VERSION 5.8 ;
BUSBITCHARS "[]" ;
DIVIDERCHAR "/" ;

UNITS
  DATABASE MICRONS 1000 ;
END UNITS
MANUFACTURINGGRID 0.001 ;

SITE NSFET
  CLASS CORE ;
  SIZE 0.050 BY 0.168 ;
  SYMMETRY X Y ;
END NSFET

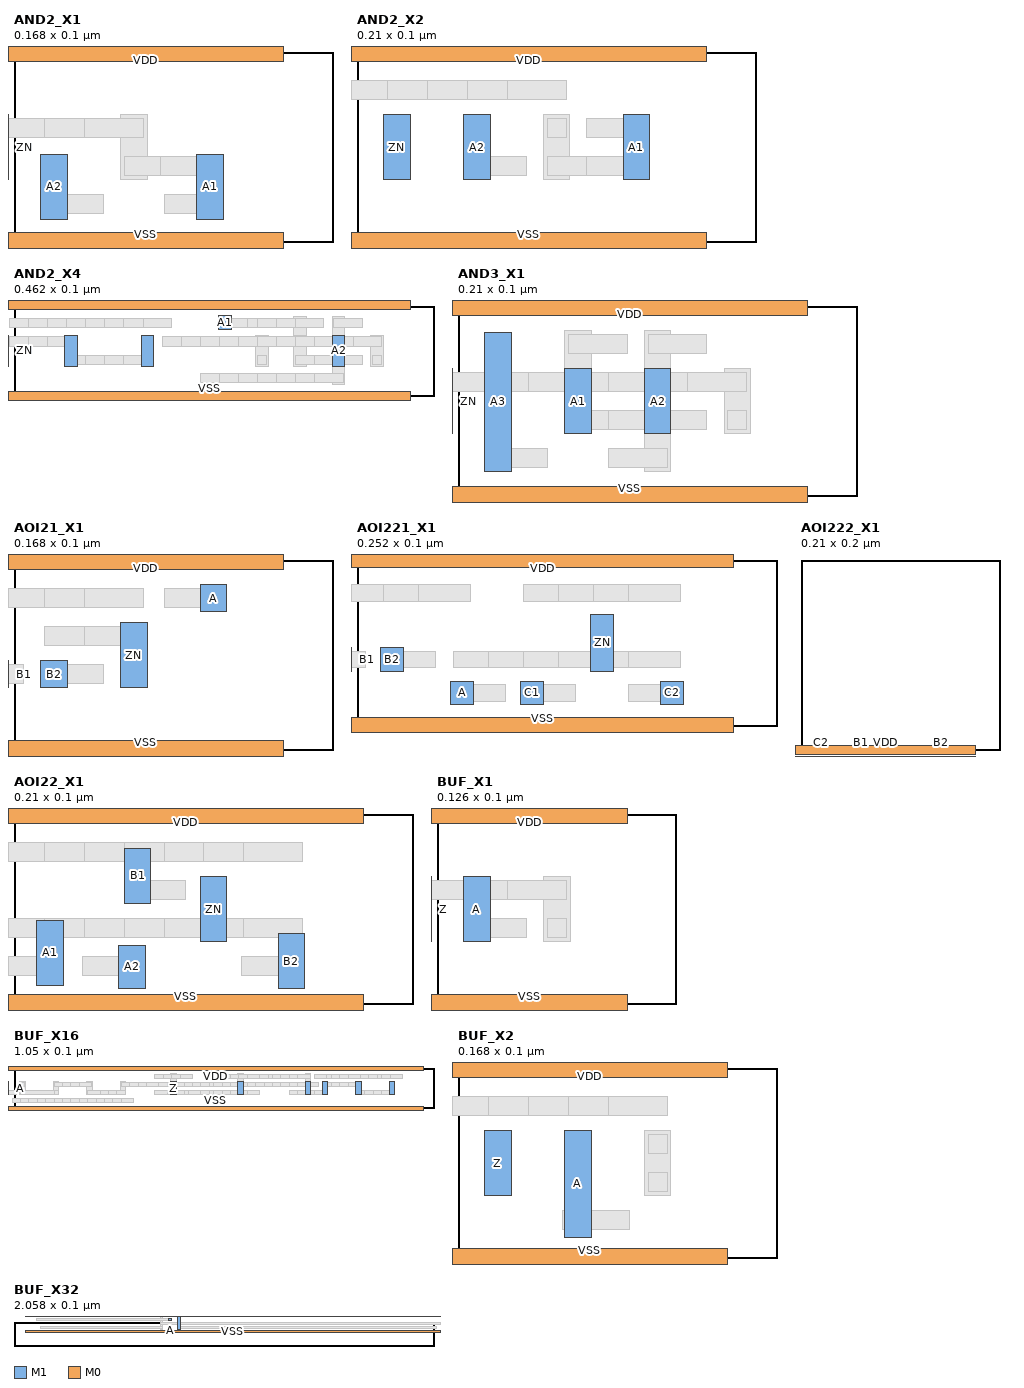
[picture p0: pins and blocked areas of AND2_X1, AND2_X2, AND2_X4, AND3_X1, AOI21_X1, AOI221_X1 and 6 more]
MACRO AND2_X1
  CLASS CORE ;
  FOREIGN AND2_X1 0 0 ;
  ORIGIN -0.0210 0.0000 ;
  SIZE 0.1680 BY 0.1000 ;
  SITE NSFET ;
  SYMMETRY X Y ;
  PIN ZN
    DIRECTION OUTPUT ;
    USE SIGNAL ;
    PORT
      LAYER M1 ;
        RECT -0.0070 0.0330 0.0070 0.0670 ;
    END
  END ZN
  PIN A1
    DIRECTION INPUT ;
    USE SIGNAL ;
    PORT
      LAYER M1 ;
        RECT 0.1170 0.0120 0.1310 0.0460 ;
    END
  END A1
  PIN A2
    DIRECTION INPUT ;
    USE SIGNAL ;
    PORT
      LAYER M1 ;
        RECT 0.0350 0.0120 0.0490 0.0460 ;
    END
  END A2
  PIN VDD
    DIRECTION INOUT ;
    USE POWER ;
    PORT
      LAYER M0 ;
        RECT -0.0370 0.0950 0.1630 0.1050 ;
    END
  END VDD
  PIN VSS
    DIRECTION INOUT ;
    USE GROUND ;
    PORT
      LAYER M0 ;
        RECT -0.0370 -0.0050 0.1630 0.0050 ;
    END
  END VSS
  OBS
    LAYER M1 ;
      RECT 0.0770 0.0330 0.0910 0.0670 ;
    LAYER M0 ;
      RECT 0.0160 0.0550 0.0470 0.0650 ;
      RECT 0.0370 0.0550 0.0680 0.0650 ;
      RECT 0.0580 0.0550 0.0890 0.0650 ;
      RECT 0.0790 0.0350 0.1100 0.0450 ;
      RECT 0.1000 0.0350 0.1310 0.0450 ;
      RECT -0.0050 0.0550 0.0050 0.0650 ;
      RECT -0.0050 0.0350 0.0050 0.0450 ;
      RECT 0.0370 0.0150 0.0680 0.0250 ;
      RECT 0.0980 0.0350 0.1290 0.0450 ;
      RECT 0.1000 0.0150 0.1310 0.0250 ;
  END
END AND2_X1

MACRO AND2_X2
  CLASS CORE ;
  FOREIGN AND2_X2 0 0 ;
  ORIGIN -0.0210 0.0000 ;
  SIZE 0.2100 BY 0.1000 ;
  SITE NSFET ;
  SYMMETRY X Y ;
  PIN A1
    DIRECTION INPUT ;
    USE SIGNAL ;
    PORT
      LAYER M1 ;
        RECT 0.1610 0.0330 0.1750 0.0670 ;
    END
  END A1
  PIN A2
    DIRECTION INPUT ;
    USE SIGNAL ;
    PORT
      LAYER M1 ;
        RECT 0.0770 0.0330 0.0910 0.0670 ;
    END
  END A2
  PIN ZN
    DIRECTION OUTPUT ;
    USE SIGNAL ;
    PORT
      LAYER M1 ;
        RECT 0.0350 0.0330 0.0490 0.0670 ;
    END
  END ZN
  PIN VSS
    DIRECTION INOUT ;
    USE GROUND ;
    PORT
      LAYER M0 ;
        RECT -0.0370 -0.0050 0.2050 0.0050 ;
    END
  END VSS
  PIN VDD
    DIRECTION INOUT ;
    USE POWER ;
    PORT
      LAYER M0 ;
        RECT -0.0370 0.0950 0.2050 0.1050 ;
    END
  END VDD
  OBS
    LAYER M1 ;
      RECT 0.1190 0.0330 0.1330 0.0670 ;
    LAYER M0 ;
      RECT 0.0160 0.0750 0.0470 0.0850 ;
      RECT 0.0370 0.0750 0.0680 0.0850 ;
      RECT 0.0580 0.0750 0.0890 0.0850 ;
      RECT 0.0790 0.0750 0.1100 0.0850 ;
      RECT 0.1000 0.0750 0.1310 0.0850 ;
      RECT 0.1210 0.0350 0.1520 0.0450 ;
      RECT 0.1420 0.0350 0.1730 0.0450 ;
      RECT 0.0370 0.0550 0.0470 0.0650 ;
      RECT 0.0370 0.0350 0.0470 0.0450 ;
      RECT 0.1210 0.0550 0.1310 0.0650 ;
      RECT 0.1420 0.0550 0.1730 0.0650 ;
      RECT 0.0790 0.0350 0.1100 0.0450 ;
  END
END AND2_X2

MACRO AND2_X4
  CLASS CORE ;
  FOREIGN AND2_X4 0 0 ;
  ORIGIN -0.0210 0.0000 ;
  SIZE 0.4620 BY 0.1000 ;
  SITE NSFET ;
  SYMMETRY X Y ;
  PIN ZN
    DIRECTION OUTPUT ;
    USE SIGNAL ;
    PORT
      LAYER M1 ;
        RECT -0.0070 0.0330 0.0070 0.0670 ;
        RECT 0.0770 0.0330 0.0910 0.0670 ;
        RECT 0.1610 0.0330 0.1750 0.0670 ;
    END
  END ZN
  PIN A1
    DIRECTION INPUT ;
    USE SIGNAL ;
    PORT
      LAYER M1 ;
        RECT 0.2460 0.0730 0.2600 0.0890 ;
    END
  END A1
  PIN A2
    DIRECTION INPUT ;
    USE SIGNAL ;
    PORT
      LAYER M1 ;
        RECT 0.3710 0.0330 0.3850 0.0670 ;
    END
  END A2
  PIN VDD
    DIRECTION INOUT ;
    USE POWER ;
    PORT
      LAYER M0 ;
        RECT -0.0370 0.0950 0.4570 0.1050 ;
    END
  END VDD
  PIN VSS
    DIRECTION INOUT ;
    USE GROUND ;
    PORT
      LAYER M0 ;
        RECT -0.0370 -0.0050 0.4570 0.0050 ;
    END
  END VSS
  OBS
    LAYER M1 ;
      RECT 0.2870 0.0330 0.3010 0.0670 ;
      RECT 0.4130 0.0330 0.4270 0.0670 ;
      RECT 0.3290 0.0530 0.3430 0.0870 ;
      RECT 0.3290 0.0330 0.3430 0.0670 ;
      RECT 0.3710 0.0530 0.3850 0.0870 ;
      RECT 0.3710 0.0130 0.3850 0.0470 ;
    LAYER M0 ;
      RECT -0.0050 0.0550 0.0260 0.0650 ;
      RECT 0.0160 0.0550 0.0470 0.0650 ;
      RECT 0.0370 0.0550 0.0680 0.0650 ;
      RECT 0.0580 0.0550 0.0890 0.0650 ;
      RECT 0.0790 0.0350 0.1100 0.0450 ;
      RECT 0.1000 0.0350 0.1310 0.0450 ;
      RECT 0.1210 0.0350 0.1520 0.0450 ;
      RECT 0.1420 0.0350 0.1730 0.0450 ;
      RECT 0.0160 0.0750 0.0470 0.0850 ;
      RECT 0.0370 0.0750 0.0680 0.0850 ;
      RECT 0.0580 0.0750 0.0890 0.0850 ;
      RECT 0.0790 0.0750 0.1100 0.0850 ;
      RECT 0.1000 0.0750 0.1310 0.0850 ;
      RECT 0.1210 0.0750 0.1520 0.0850 ;
      RECT 0.1420 0.0750 0.1730 0.0850 ;
      RECT 0.1630 0.0750 0.1940 0.0850 ;
      RECT 0.1840 0.0550 0.2150 0.0650 ;
      RECT 0.2050 0.0550 0.2360 0.0650 ;
      RECT 0.2260 0.0550 0.2570 0.0650 ;
      RECT 0.2470 0.0550 0.2780 0.0650 ;
      RECT 0.2680 0.0550 0.2990 0.0650 ;
      RECT 0.2890 0.0550 0.3200 0.0650 ;
      RECT 0.3100 0.0550 0.3410 0.0650 ;
      RECT 0.3310 0.0550 0.3620 0.0650 ;
      RECT 0.3520 0.0550 0.3830 0.0650 ;
      RECT 0.3730 0.0550 0.4040 0.0650 ;
      RECT 0.3940 0.0550 0.4250 0.0650 ;
      RECT 0.2680 0.0750 0.2990 0.0850 ;
      RECT 0.2890 0.0750 0.3200 0.0850 ;
      RECT 0.3100 0.0750 0.3410 0.0850 ;
      RECT 0.3310 0.0750 0.3620 0.0850 ;
      RECT 0.3310 0.0350 0.3620 0.0450 ;
      RECT 0.3520 0.0350 0.3830 0.0450 ;
      RECT 0.3730 0.0350 0.4040 0.0450 ;
      RECT 0.3730 0.0750 0.4040 0.0850 ;
      RECT 0.2260 0.0150 0.2570 0.0250 ;
      RECT 0.2470 0.0150 0.2780 0.0250 ;
      RECT 0.2680 0.0150 0.2990 0.0250 ;
      RECT 0.2890 0.0150 0.3200 0.0250 ;
      RECT 0.3100 0.0150 0.3410 0.0250 ;
      RECT 0.3310 0.0150 0.3620 0.0250 ;
      RECT 0.3520 0.0150 0.3830 0.0250 ;
      RECT 0.1630 0.0550 0.1730 0.0650 ;
      RECT -0.0050 0.0350 0.0050 0.0450 ;
      RECT 0.2890 0.0350 0.2990 0.0450 ;
      RECT 0.4150 0.0350 0.4250 0.0450 ;
      RECT 0.2470 0.0750 0.2780 0.0850 ;
  END
END AND2_X4

MACRO AND3_X1
  CLASS CORE ;
  FOREIGN AND3_X1 0 0 ;
  ORIGIN -0.0210 0.0000 ;
  SIZE 0.2100 BY 0.1000 ;
  SITE NSFET ;
  SYMMETRY X Y ;
  PIN A3
    DIRECTION INPUT ;
    USE SIGNAL ;
    PORT
      LAYER M1 ;
        RECT 0.0350 0.0130 0.0490 0.0860 ;
    END
  END A3
  PIN ZN
    DIRECTION OUTPUT ;
    USE SIGNAL ;
    PORT
      LAYER M1 ;
        RECT -0.0070 0.0330 0.0070 0.0670 ;
    END
  END ZN
  PIN A2
    DIRECTION INPUT ;
    USE SIGNAL ;
    PORT
      LAYER M1 ;
        RECT 0.1190 0.0330 0.1330 0.0670 ;
    END
  END A2
  PIN A1
    DIRECTION INPUT ;
    USE SIGNAL ;
    PORT
      LAYER M1 ;
        RECT 0.0770 0.0330 0.0910 0.0670 ;
    END
  END A1
  PIN VDD
    DIRECTION INOUT ;
    USE POWER ;
    PORT
      LAYER M0 ;
        RECT -0.0370 0.0950 0.2050 0.1050 ;
    END
  END VDD
  PIN VSS
    DIRECTION INOUT ;
    USE GROUND ;
    PORT
      LAYER M0 ;
        RECT -0.0370 -0.0050 0.2050 0.0050 ;
    END
  END VSS
  OBS
    LAYER M1 ;
      RECT 0.1610 0.0330 0.1750 0.0670 ;
      RECT 0.0770 0.0530 0.0910 0.0870 ;
      RECT 0.1190 0.0530 0.1330 0.0870 ;
      RECT 0.1190 0.0130 0.1330 0.0470 ;
    LAYER M0 ;
      RECT 0.0160 0.0550 0.0470 0.0650 ;
      RECT 0.0370 0.0550 0.0680 0.0650 ;
      RECT 0.0580 0.0550 0.0890 0.0650 ;
      RECT 0.0790 0.0550 0.1100 0.0650 ;
      RECT 0.1000 0.0550 0.1310 0.0650 ;
      RECT 0.1210 0.0550 0.1520 0.0650 ;
      RECT 0.1420 0.0550 0.1730 0.0650 ;
      RECT 0.0790 0.0750 0.1100 0.0850 ;
      RECT 0.0790 0.0350 0.1100 0.0450 ;
      RECT 0.1000 0.0350 0.1310 0.0450 ;
      RECT 0.1210 0.0350 0.1520 0.0450 ;
      RECT 0.1210 0.0750 0.1520 0.0850 ;
      RECT 0.1000 0.0150 0.1310 0.0250 ;
      RECT -0.0050 0.0550 0.0050 0.0650 ;
      RECT -0.0050 0.0350 0.0050 0.0450 ;
      RECT 0.1630 0.0350 0.1730 0.0450 ;
      RECT 0.0370 0.0150 0.0680 0.0250 ;
  END
END AND3_X1

MACRO AOI21_X1
  CLASS CORE ;
  FOREIGN AOI21_X1 0 0 ;
  ORIGIN -0.0210 0.0000 ;
  SIZE 0.1680 BY 0.1000 ;
  SITE NSFET ;
  SYMMETRY X Y ;
  PIN B1
    DIRECTION INPUT ;
    USE SIGNAL ;
    PORT
      LAYER M1 ;
        RECT -0.0070 0.0330 0.0070 0.0470 ;
    END
  END B1
  PIN B2
    DIRECTION INPUT ;
    USE SIGNAL ;
    PORT
      LAYER M1 ;
        RECT 0.0350 0.0330 0.0490 0.0470 ;
    END
  END B2
  PIN ZN
    DIRECTION OUTPUT ;
    USE SIGNAL ;
    PORT
      LAYER M1 ;
        RECT 0.0770 0.0330 0.0910 0.0670 ;
    END
  END ZN
  PIN A
    DIRECTION INPUT ;
    USE SIGNAL ;
    PORT
      LAYER M1 ;
        RECT 0.1190 0.0730 0.1330 0.0870 ;
    END
  END A
  PIN VDD
    DIRECTION INOUT ;
    USE POWER ;
    PORT
      LAYER M0 ;
        RECT -0.0370 0.0950 0.1630 0.1050 ;
    END
  END VDD
  PIN VSS
    DIRECTION INOUT ;
    USE GROUND ;
    PORT
      LAYER M0 ;
        RECT -0.0370 -0.0050 0.1630 0.0050 ;
    END
  END VSS
  OBS
    LAYER M0 ;
      RECT -0.0050 0.0750 0.0260 0.0850 ;
      RECT 0.0160 0.0750 0.0470 0.0850 ;
      RECT 0.0370 0.0750 0.0680 0.0850 ;
      RECT 0.0580 0.0750 0.0890 0.0850 ;
      RECT 0.0370 0.0550 0.0680 0.0650 ;
      RECT 0.0580 0.0550 0.0890 0.0650 ;
      RECT 0.0790 0.0350 0.0890 0.0450 ;
      RECT -0.0050 0.0350 0.0260 0.0450 ;
      RECT 0.0370 0.0350 0.0680 0.0450 ;
      RECT 0.1000 0.0750 0.1310 0.0850 ;
  END
END AOI21_X1

MACRO AOI221_X1
  CLASS CORE ;
  FOREIGN AOI221_X1 0 0 ;
  ORIGIN -0.0210 0.0000 ;
  SIZE 0.2520 BY 0.1000 ;
  SITE NSFET ;
  SYMMETRY X Y ;
  PIN B1
    DIRECTION INPUT ;
    USE SIGNAL ;
    PORT
      LAYER M1 ;
        RECT -0.0070 0.0330 0.0070 0.0470 ;
    END
  END B1
  PIN B2
    DIRECTION INPUT ;
    USE SIGNAL ;
    PORT
      LAYER M1 ;
        RECT 0.0350 0.0330 0.0490 0.0470 ;
    END
  END B2
  PIN ZN
    DIRECTION OUTPUT ;
    USE SIGNAL ;
    PORT
      LAYER M1 ;
        RECT 0.1610 0.0330 0.1750 0.0670 ;
    END
  END ZN
  PIN A
    DIRECTION INPUT ;
    USE SIGNAL ;
    PORT
      LAYER M1 ;
        RECT 0.0770 0.0130 0.0910 0.0270 ;
    END
  END A
  PIN C1
    DIRECTION INPUT ;
    USE SIGNAL ;
    PORT
      LAYER M1 ;
        RECT 0.1190 0.0130 0.1330 0.0270 ;
    END
  END C1
  PIN C2
    DIRECTION INPUT ;
    USE SIGNAL ;
    PORT
      LAYER M1 ;
        RECT 0.2030 0.0130 0.2170 0.0270 ;
    END
  END C2
  PIN VSS
    DIRECTION INOUT ;
    USE GROUND ;
    PORT
      LAYER M0 ;
        RECT -0.0370 -0.0050 0.2470 0.0050 ;
    END
  END VSS
  PIN VDD
    DIRECTION INOUT ;
    USE POWER ;
    PORT
      LAYER M0 ;
        RECT -0.0370 0.0950 0.2470 0.1050 ;
    END
  END VDD
  OBS
    LAYER M0 ;
      RECT -0.0050 0.0750 0.0260 0.0850 ;
      RECT 0.0160 0.0750 0.0470 0.0850 ;
      RECT 0.0370 0.0750 0.0680 0.0850 ;
      RECT 0.0580 0.0750 0.0890 0.0850 ;
      RECT 0.1210 0.0750 0.1520 0.0850 ;
      RECT 0.1420 0.0750 0.1730 0.0850 ;
      RECT 0.1630 0.0750 0.1940 0.0850 ;
      RECT 0.1840 0.0750 0.2150 0.0850 ;
      RECT 0.0790 0.0350 0.1100 0.0450 ;
      RECT 0.1000 0.0350 0.1310 0.0450 ;
      RECT 0.1210 0.0350 0.1520 0.0450 ;
      RECT 0.1420 0.0350 0.1730 0.0450 ;
      RECT 0.1630 0.0350 0.1940 0.0450 ;
      RECT 0.1840 0.0350 0.2150 0.0450 ;
      RECT 0.1630 0.0550 0.1730 0.0650 ;
      RECT -0.0050 0.0350 0.0260 0.0450 ;
      RECT 0.0370 0.0350 0.0680 0.0450 ;
      RECT 0.0790 0.0150 0.1100 0.0250 ;
      RECT 0.1210 0.0150 0.1520 0.0250 ;
      RECT 0.1840 0.0150 0.2150 0.0250 ;
  END
END AOI221_X1

MACRO AOI222_X1
  CLASS CORE ;
  FOREIGN AOI222_X1 0 0 ;
  ORIGIN -0.0210 -0.1000 ;
  SIZE 0.2100 BY 0.2000 ;
  SITE NSFET ;
  SYMMETRY X Y ;
  PIN ZN
    DIRECTION OUTPUT ;
    USE SIGNAL ;
    PORT
      LAYER M1 ;
        RECT 0.0350 -0.0070 0.0490 0.0270 ;
        RECT 0.0350 -0.0270 0.0490 0.0070 ;
    END
  END ZN
  PIN A2
    DIRECTION INPUT ;
    USE SIGNAL ;
    PORT
      LAYER M1 ;
        RECT -0.0070 -0.0470 0.0070 -0.0130 ;
    END
  END A2
  PIN A1
    DIRECTION INPUT ;
    USE SIGNAL ;
    PORT
      LAYER M1 ;
        RECT 0.1610 -0.0470 0.1750 -0.0130 ;
    END
  END A1
  PIN C1
    DIRECTION INPUT ;
    USE SIGNAL ;
    PORT
      LAYER M1 ;
        RECT -0.0070 0.0520 0.0070 0.0860 ;
    END
  END C1
  PIN C2
    DIRECTION INPUT ;
    USE SIGNAL ;
    PORT
      LAYER M1 ;
        RECT 0.0350 0.0520 0.0490 0.0860 ;
    END
  END C2
  PIN B1
    DIRECTION INPUT ;
    USE SIGNAL ;
    PORT
      LAYER M1 ;
        RECT 0.0770 0.0520 0.0910 0.0860 ;
    END
  END B1
  PIN B2
    DIRECTION INPUT ;
    USE SIGNAL ;
    PORT
      LAYER M1 ;
        RECT 0.1610 0.0520 0.1750 0.0860 ;
    END
  END B2
  PIN VSS
    DIRECTION INOUT ;
    USE GROUND ;
    PORT
      LAYER M0 ;
        RECT -0.0370 -0.0050 0.2050 0.0050 ;
    END
  END VSS
  PIN VDD
    DIRECTION INOUT ;
    USE POWER ;
    PORT
      LAYER M0 ;
        RECT -0.0370 -0.1050 0.2050 -0.0950 ;
    END
  END VDD
  PIN VDD
    DIRECTION INOUT ;
    USE POWER ;
    PORT
      LAYER M0 ;
        RECT -0.0370 0.0950 0.2050 0.1050 ;
    END
  END VDD
  OBS
    LAYER M1 ;
      RECT 0.1190 0.0330 0.1330 0.0670 ;
      RECT 0.1190 0.0130 0.1330 0.0470 ;
      RECT 0.1190 -0.0070 0.1330 0.0270 ;
      RECT 0.1190 -0.0270 0.1330 0.0070 ;
      RECT 0.1190 -0.0470 0.1330 -0.0130 ;
      RECT 0.1190 -0.0670 0.1330 -0.0330 ;
      RECT 0.0350 -0.0470 0.0490 -0.0130 ;
      RECT 0.0350 -0.0670 0.0490 -0.0330 ;
      RECT 0.0350 -0.0870 0.0490 -0.0530 ;
    LAYER M0 ;
      RECT -0.0050 0.0750 0.0260 0.0850 ;
      RECT 0.0160 0.0750 0.0470 0.0850 ;
      RECT 0.0370 0.0750 0.0680 0.0850 ;
      RECT 0.0580 0.0750 0.0890 0.0850 ;
      RECT 0.0790 0.0750 0.1100 0.0850 ;
      RECT 0.1000 0.0750 0.1310 0.0850 ;
      RECT 0.1210 0.0750 0.1520 0.0850 ;
      RECT 0.1420 0.0750 0.1730 0.0850 ;
      RECT 0.0370 -0.0650 0.0680 -0.0550 ;
      RECT 0.0580 -0.0650 0.0890 -0.0550 ;
      RECT 0.0790 -0.0650 0.1100 -0.0550 ;
      RECT 0.1000 -0.0650 0.1310 -0.0550 ;
      RECT -0.0050 0.0150 0.0260 0.0250 ;
      RECT 0.0160 0.0150 0.0470 0.0250 ;
      RECT 0.0370 0.0150 0.0680 0.0250 ;
      RECT 0.0580 0.0150 0.0890 0.0250 ;
      RECT 0.0790 0.0150 0.1100 0.0250 ;
      RECT 0.1000 0.0150 0.1310 0.0250 ;
      RECT 0.1210 0.0150 0.1520 0.0250 ;
      RECT 0.1420 0.0150 0.1730 0.0250 ;
      RECT 0.0370 -0.0850 0.0680 -0.0750 ;
      RECT 0.0580 -0.0850 0.0890 -0.0750 ;
      RECT 0.1210 0.0550 0.1310 0.0650 ;
      RECT 0.0370 -0.0250 0.0470 -0.0150 ;
      RECT -0.0060 0.0550 0.0260 0.0650 ;
      RECT 0.0360 0.0550 0.0680 0.0650 ;
      RECT 0.1420 0.0550 0.1740 0.0650 ;
      RECT 0.0780 0.0550 0.1100 0.0650 ;
      RECT -0.0070 -0.0450 0.0690 -0.0350 ;
      RECT 0.0990 -0.0450 0.1750 -0.0350 ;
  END
END AOI222_X1

MACRO AOI22_X1
  CLASS CORE ;
  FOREIGN AOI22_X1 0 0 ;
  ORIGIN -0.0210 0.0000 ;
  SIZE 0.2100 BY 0.1000 ;
  SITE NSFET ;
  SYMMETRY X Y ;
  PIN A1
    DIRECTION INPUT ;
    USE SIGNAL ;
    PORT
      LAYER M1 ;
        RECT 0.0330 0.0100 0.0470 0.0440 ;
    END
  END A1
  PIN A2
    DIRECTION INPUT ;
    USE SIGNAL ;
    PORT
      LAYER M1 ;
        RECT 0.0760 0.0080 0.0900 0.0310 ;
    END
  END A2
  PIN B1
    DIRECTION INPUT ;
    USE SIGNAL ;
    PORT
      LAYER M1 ;
        RECT 0.0790 0.0530 0.0930 0.0820 ;
    END
  END B1
  PIN B2
    DIRECTION INPUT ;
    USE SIGNAL ;
    PORT
      LAYER M1 ;
        RECT 0.1600 0.0080 0.1740 0.0370 ;
    END
  END B2
  PIN ZN
    DIRECTION OUTPUT ;
    USE SIGNAL ;
    PORT
      LAYER M1 ;
        RECT 0.1190 0.0330 0.1330 0.0670 ;
    END
  END ZN
  PIN VSS
    DIRECTION INOUT ;
    USE GROUND ;
    PORT
      LAYER M0 ;
        RECT -0.0370 -0.0050 0.2050 0.0050 ;
    END
  END VSS
  PIN VDD
    DIRECTION INOUT ;
    USE POWER ;
    PORT
      LAYER M0 ;
        RECT -0.0370 0.0950 0.2050 0.1050 ;
    END
  END VDD
  OBS
    LAYER M0 ;
      RECT -0.0050 0.0750 0.0260 0.0850 ;
      RECT 0.0160 0.0750 0.0470 0.0850 ;
      RECT 0.0370 0.0750 0.0680 0.0850 ;
      RECT 0.0580 0.0750 0.0890 0.0850 ;
      RECT 0.0790 0.0750 0.1100 0.0850 ;
      RECT 0.1000 0.0750 0.1310 0.0850 ;
      RECT 0.1210 0.0750 0.1520 0.0850 ;
      RECT 0.1420 0.0750 0.1730 0.0850 ;
      RECT -0.0050 0.0350 0.0260 0.0450 ;
      RECT 0.0160 0.0350 0.0470 0.0450 ;
      RECT 0.0370 0.0350 0.0680 0.0450 ;
      RECT 0.0580 0.0350 0.0890 0.0450 ;
      RECT 0.0790 0.0350 0.1100 0.0450 ;
      RECT 0.1000 0.0350 0.1310 0.0450 ;
      RECT 0.1210 0.0350 0.1520 0.0450 ;
      RECT 0.1420 0.0350 0.1730 0.0450 ;
      RECT 0.1210 0.0550 0.1310 0.0650 ;
      RECT 0.0140 0.0150 0.0460 0.0250 ;
      RECT 0.0570 0.0150 0.0890 0.0250 ;
      RECT 0.1410 0.0150 0.1730 0.0250 ;
      RECT 0.0790 0.0550 0.1110 0.0650 ;
  END
END AOI22_X1

MACRO BUF_X1
  CLASS CORE ;
  FOREIGN BUF_X1 0 0 ;
  ORIGIN -0.0210 0.0000 ;
  SIZE 0.1260 BY 0.1000 ;
  SITE NSFET ;
  SYMMETRY X Y ;
  PIN Z
    DIRECTION OUTPUT ;
    USE SIGNAL ;
    PORT
      LAYER M1 ;
        RECT -0.0070 0.0330 0.0070 0.0670 ;
    END
  END Z
  PIN A
    DIRECTION INPUT ;
    USE SIGNAL ;
    PORT
      LAYER M1 ;
        RECT 0.0350 0.0330 0.0490 0.0670 ;
    END
  END A
  PIN VSS
    DIRECTION INOUT ;
    USE GROUND ;
    PORT
      LAYER M0 ;
        RECT -0.0370 -0.0050 0.1210 0.0050 ;
    END
  END VSS
  PIN VDD
    DIRECTION INOUT ;
    USE POWER ;
    PORT
      LAYER M0 ;
        RECT -0.0370 0.0950 0.1210 0.1050 ;
    END
  END VDD
  OBS
    LAYER M1 ;
      RECT 0.0770 0.0330 0.0910 0.0670 ;
    LAYER M0 ;
      RECT 0.0160 0.0550 0.0470 0.0650 ;
      RECT 0.0370 0.0550 0.0680 0.0650 ;
      RECT 0.0580 0.0550 0.0890 0.0650 ;
      RECT -0.0050 0.0550 0.0050 0.0650 ;
      RECT -0.0050 0.0350 0.0050 0.0450 ;
      RECT 0.0790 0.0350 0.0890 0.0450 ;
      RECT 0.0370 0.0350 0.0680 0.0450 ;
  END
END BUF_X1

MACRO BUF_X16
  CLASS CORE ;
  FOREIGN BUF_X16 0 0 ;
  ORIGIN -0.0210 0.0000 ;
  SIZE 1.0500 BY 0.1000 ;
  SITE NSFET ;
  SYMMETRY X Y ;
  PIN Z
    DIRECTION OUTPUT ;
    USE SIGNAL ;
    PORT
      LAYER M1 ;
        RECT 0.4130 0.0330 0.4270 0.0670 ;
        RECT 0.5810 0.0330 0.5950 0.0670 ;
        RECT 0.7490 0.0330 0.7630 0.0670 ;
        RECT 0.7910 0.0330 0.8050 0.0670 ;
        RECT 0.8750 0.0330 0.8890 0.0670 ;
        RECT 0.9590 0.0330 0.9730 0.0670 ;
        RECT 0.4130 0.0330 0.4270 0.0670 ;
        RECT 0.5810 0.0330 0.5950 0.0670 ;
        RECT 0.7490 0.0330 0.7630 0.0670 ;
        RECT 0.7910 0.0330 0.8050 0.0670 ;
        RECT 0.8750 0.0330 0.8890 0.0670 ;
        RECT 0.9590 0.0330 0.9730 0.0670 ;
    END
  END Z
  PIN A
    DIRECTION INPUT ;
    USE SIGNAL ;
    PORT
      LAYER M1 ;
        RECT -0.0070 0.0330 0.0070 0.0670 ;
    END
  END A
  PIN VSS
    DIRECTION INOUT ;
    USE GROUND ;
    PORT
      LAYER M0 ;
        RECT -0.0370 -0.0050 1.0450 0.0050 ;
    END
  END VSS
  PIN VDD
    DIRECTION INOUT ;
    USE POWER ;
    PORT
      LAYER M0 ;
        RECT -0.0370 0.0950 1.0450 0.1050 ;
    END
  END VDD
  OBS
    LAYER M1 ;
      RECT 0.0350 0.0330 0.0490 0.0670 ;
      RECT 0.1190 0.0330 0.1330 0.0670 ;
      RECT 0.2030 0.0330 0.2170 0.0670 ;
      RECT 0.2870 0.0330 0.3010 0.0670 ;
      RECT 0.4130 0.0530 0.4270 0.0870 ;
      RECT 0.5810 0.0530 0.5950 0.0870 ;
      RECT 0.7490 0.0530 0.7630 0.0870 ;
      RECT 0.0350 0.0330 0.0490 0.0670 ;
      RECT 0.1190 0.0330 0.1330 0.0670 ;
      RECT 0.2030 0.0330 0.2170 0.0670 ;
      RECT 0.2870 0.0330 0.3010 0.0670 ;
      RECT 0.4130 0.0530 0.4270 0.0870 ;
      RECT 0.5810 0.0530 0.5950 0.0870 ;
      RECT 0.7490 0.0530 0.7630 0.0870 ;
    LAYER M0 ;
      RECT 0.7720 0.0750 0.8030 0.0850 ;
      RECT 0.7930 0.0750 0.8240 0.0850 ;
      RECT 0.8140 0.0750 0.8450 0.0850 ;
      RECT 0.8350 0.0750 0.8660 0.0850 ;
      RECT 0.8560 0.0750 0.8870 0.0850 ;
      RECT 0.8770 0.0750 0.9080 0.0850 ;
      RECT 0.8980 0.0750 0.9290 0.0850 ;
      RECT 0.9190 0.0750 0.9500 0.0850 ;
      RECT 0.9400 0.0750 0.9710 0.0850 ;
      RECT 0.9610 0.0750 0.9920 0.0850 ;
      RECT 0.1210 0.0550 0.1520 0.0650 ;
      RECT 0.1420 0.0550 0.1730 0.0650 ;
      RECT 0.1630 0.0550 0.1940 0.0650 ;
      RECT 0.1840 0.0550 0.2150 0.0650 ;
      RECT 0.2890 0.0550 0.3200 0.0650 ;
      RECT 0.3100 0.0550 0.3410 0.0650 ;
      RECT 0.3310 0.0550 0.3620 0.0650 ;
      RECT 0.3520 0.0550 0.3830 0.0650 ;
      RECT 0.3730 0.0550 0.4040 0.0650 ;
      RECT 0.3940 0.0550 0.4250 0.0650 ;
      RECT 0.4150 0.0550 0.4460 0.0650 ;
      RECT 0.4360 0.0550 0.4670 0.0650 ;
      RECT 0.4570 0.0550 0.4880 0.0650 ;
      RECT 0.4780 0.0550 0.5090 0.0650 ;
      RECT 0.4990 0.0550 0.5300 0.0650 ;
      RECT 0.5200 0.0550 0.5510 0.0650 ;
      RECT 0.5410 0.0550 0.5720 0.0650 ;
      RECT 0.5620 0.0550 0.5930 0.0650 ;
      RECT 0.5830 0.0550 0.6140 0.0650 ;
      RECT 0.6040 0.0550 0.6350 0.0650 ;
      RECT 0.6250 0.0550 0.6560 0.0650 ;
      RECT 0.6460 0.0550 0.6770 0.0650 ;
      RECT 0.6670 0.0550 0.6980 0.0650 ;
      RECT 0.6880 0.0550 0.7190 0.0650 ;
      RECT 0.7090 0.0550 0.7400 0.0650 ;
      RECT 0.7300 0.0550 0.7610 0.0650 ;
      RECT 0.7510 0.0550 0.7820 0.0650 ;
      RECT 0.2050 0.0350 0.2360 0.0450 ;
      RECT 0.2260 0.0350 0.2570 0.0450 ;
      RECT 0.2470 0.0350 0.2780 0.0450 ;
      RECT 0.2680 0.0350 0.2990 0.0450 ;
      RECT 0.3730 0.0750 0.4040 0.0850 ;
      RECT 0.3940 0.0750 0.4250 0.0850 ;
      RECT 0.4150 0.0750 0.4460 0.0850 ;
      RECT 0.4360 0.0750 0.4670 0.0850 ;
      RECT 0.5410 0.0750 0.5720 0.0850 ;
      RECT 0.5620 0.0750 0.5930 0.0850 ;
      RECT 0.5830 0.0750 0.6140 0.0850 ;
      RECT 0.6040 0.0750 0.6350 0.0850 ;
      RECT 0.6250 0.0750 0.6560 0.0850 ;
      RECT 0.6460 0.0750 0.6770 0.0850 ;
      RECT 0.6670 0.0750 0.6980 0.0850 ;
      RECT 0.6880 0.0750 0.7190 0.0850 ;
      RECT 0.7090 0.0750 0.7400 0.0850 ;
      RECT 0.7300 0.0750 0.7610 0.0850 ;
      RECT 0.7930 0.0550 0.8240 0.0650 ;
      RECT 0.8140 0.0550 0.8450 0.0650 ;
      RECT 0.8350 0.0550 0.8660 0.0650 ;
      RECT 0.8560 0.0550 0.8870 0.0650 ;
      RECT 0.3730 0.0350 0.4040 0.0450 ;
      RECT 0.3940 0.0350 0.4250 0.0450 ;
      RECT 0.4150 0.0350 0.4460 0.0450 ;
      RECT 0.4360 0.0350 0.4670 0.0450 ;
      RECT 0.4570 0.0350 0.4880 0.0450 ;
      RECT 0.4780 0.0350 0.5090 0.0450 ;
      RECT 0.4990 0.0350 0.5300 0.0450 ;
      RECT 0.5200 0.0350 0.5510 0.0450 ;
      RECT 0.5410 0.0350 0.5720 0.0450 ;
      RECT 0.5620 0.0350 0.5930 0.0450 ;
      RECT 0.5830 0.0350 0.6140 0.0450 ;
      RECT 0.6040 0.0350 0.6350 0.0450 ;
      RECT 0.7090 0.0350 0.7400 0.0450 ;
      RECT 0.7300 0.0350 0.7610 0.0450 ;
      RECT 0.7510 0.0350 0.7820 0.0450 ;
      RECT 0.7720 0.0350 0.8030 0.0450 ;
      RECT 0.8770 0.0350 0.9080 0.0450 ;
      RECT 0.8980 0.0350 0.9290 0.0450 ;
      RECT 0.9190 0.0350 0.9500 0.0450 ;
      RECT 0.9400 0.0350 0.9710 0.0450 ;
      RECT 0.0160 0.0150 0.0470 0.0250 ;
      RECT 0.0370 0.0150 0.0680 0.0250 ;
      RECT 0.0580 0.0150 0.0890 0.0250 ;
      RECT 0.0790 0.0150 0.1100 0.0250 ;
      RECT 0.1000 0.0150 0.1310 0.0250 ;
      RECT 0.1210 0.0150 0.1520 0.0250 ;
      RECT 0.1420 0.0150 0.1730 0.0250 ;
      RECT 0.1630 0.0150 0.1940 0.0250 ;
      RECT 0.1840 0.0150 0.2150 0.0250 ;
      RECT 0.2050 0.0150 0.2360 0.0250 ;
      RECT 0.2260 0.0150 0.2570 0.0250 ;
      RECT 0.2470 0.0150 0.2780 0.0250 ;
      RECT 0.2680 0.0150 0.2990 0.0250 ;
      RECT 0.2890 0.0150 0.3200 0.0250 ;
      RECT 0.0370 0.0550 0.0470 0.0650 ;
      RECT 0.0370 0.0350 0.0470 0.0450 ;
      RECT 0.1210 0.0350 0.1310 0.0450 ;
      RECT 0.9610 0.0550 0.9710 0.0650 ;
      RECT 0.9190 0.0750 0.9500 0.0850 ;
      RECT 0.9400 0.0750 0.9710 0.0850 ;
      RECT 0.9610 0.0750 0.9920 0.0850 ;
      RECT 0.4990 0.0550 0.5300 0.0650 ;
      RECT 0.5200 0.0550 0.5510 0.0650 ;
      RECT 0.5410 0.0550 0.5720 0.0650 ;
      RECT 0.5620 0.0550 0.5930 0.0650 ;
      RECT 0.5830 0.0550 0.6140 0.0650 ;
      RECT 0.6040 0.0550 0.6350 0.0650 ;
      RECT 0.6250 0.0550 0.6560 0.0650 ;
      RECT 0.6460 0.0550 0.6770 0.0650 ;
      RECT 0.6670 0.0550 0.6980 0.0650 ;
      RECT 0.6880 0.0550 0.7190 0.0650 ;
      RECT 0.7090 0.0550 0.7400 0.0650 ;
      RECT 0.7300 0.0550 0.7610 0.0650 ;
      RECT 0.7510 0.0550 0.7820 0.0650 ;
      RECT 0.5410 0.0750 0.5720 0.0850 ;
      RECT 0.5620 0.0750 0.5930 0.0850 ;
      RECT 0.5830 0.0750 0.6140 0.0850 ;
      RECT 0.7930 0.0750 0.8240 0.0850 ;
      RECT 0.7720 0.0750 0.8030 0.0850 ;
      RECT 0.3730 0.0750 0.4040 0.0850 ;
      RECT 0.3940 0.0750 0.4250 0.0850 ;
      RECT 0.4150 0.0750 0.4460 0.0850 ;
      RECT 0.4360 0.0750 0.4670 0.0850 ;
      RECT 0.0370 0.0550 0.0470 0.0650 ;
      RECT 0.8140 0.0750 0.8450 0.0850 ;
      RECT 0.8350 0.0750 0.8660 0.0850 ;
      RECT 0.4780 0.0550 0.5090 0.0650 ;
      RECT 0.4570 0.0550 0.4880 0.0650 ;
      RECT 0.4360 0.0550 0.4670 0.0650 ;
      RECT 0.4150 0.0550 0.4460 0.0650 ;
      RECT 0.3940 0.0550 0.4250 0.0650 ;
      RECT 0.3730 0.0550 0.4040 0.0650 ;
      RECT 0.0370 0.0350 0.1320 0.0450 ;
      RECT -0.0090 0.0350 0.0270 0.0450 ;
      RECT 0.4990 0.0350 0.5300 0.0450 ;
      RECT 0.5200 0.0350 0.5510 0.0450 ;
      RECT 0.5410 0.0350 0.5720 0.0450 ;
      RECT 0.5620 0.0350 0.5930 0.0450 ;
      RECT 0.5830 0.0350 0.6140 0.0450 ;
      RECT 0.6040 0.0350 0.6350 0.0450 ;
      RECT 0.7090 0.0350 0.7400 0.0450 ;
      RECT 0.7300 0.0350 0.7610 0.0450 ;
      RECT 0.7510 0.0350 0.7820 0.0450 ;
      RECT 0.7720 0.0350 0.8030 0.0450 ;
      RECT 0.8770 0.0350 0.9080 0.0450 ;
      RECT 0.8980 0.0350 0.9290 0.0450 ;
      RECT 0.9190 0.0350 0.9500 0.0450 ;
      RECT 0.9400 0.0350 0.9710 0.0450 ;
      RECT 0.0160 0.0150 0.0470 0.0250 ;
      RECT 0.0370 0.0150 0.0680 0.0250 ;
      RECT 0.0580 0.0150 0.0890 0.0250 ;
      RECT 0.0790 0.0150 0.1100 0.0250 ;
      RECT 0.1000 0.0150 0.1310 0.0250 ;
      RECT 0.1210 0.0150 0.1520 0.0250 ;
      RECT 0.1420 0.0150 0.1730 0.0250 ;
      RECT 0.1630 0.0150 0.1940 0.0250 ;
      RECT 0.1840 0.0150 0.2150 0.0250 ;
      RECT 0.2050 0.0150 0.2360 0.0250 ;
      RECT 0.2260 0.0150 0.2570 0.0250 ;
      RECT 0.2470 0.0150 0.2780 0.0250 ;
      RECT 0.2680 0.0150 0.2990 0.0250 ;
      RECT 0.2890 0.0150 0.3200 0.0250 ;
      RECT 0.1210 0.0350 0.1310 0.0450 ;
      RECT 0.4360 0.0350 0.4670 0.0450 ;
      RECT 0.4150 0.0350 0.4460 0.0450 ;
      RECT 0.3940 0.0350 0.4250 0.0450 ;
      RECT 0.3730 0.0350 0.4040 0.0450 ;
      RECT 0.6460 0.0750 0.6770 0.0850 ;
      RECT 0.6670 0.0750 0.6980 0.0850 ;
      RECT 0.6880 0.0750 0.7190 0.0850 ;
      RECT 0.7090 0.0750 0.7400 0.0850 ;
      RECT 0.7300 0.0750 0.7610 0.0850 ;
      RECT 0.7930 0.0550 0.8240 0.0650 ;
      RECT 0.8140 0.0550 0.8450 0.0650 ;
      RECT 0.8350 0.0550 0.8660 0.0650 ;
      RECT 0.8560 0.0550 0.8870 0.0650 ;
      RECT 0.9610 0.0550 0.9710 0.0650 ;
      RECT 0.8980 0.0750 0.9290 0.0850 ;
      RECT 0.8770 0.0750 0.9080 0.0850 ;
      RECT 0.8560 0.0750 0.8870 0.0850 ;
      RECT 0.1210 0.0550 0.1520 0.0650 ;
      RECT 0.1420 0.0550 0.1730 0.0650 ;
      RECT 0.1630 0.0550 0.1940 0.0650 ;
      RECT 0.1840 0.0550 0.2150 0.0650 ;
      RECT 0.2890 0.0550 0.3200 0.0650 ;
      RECT 0.2680 0.0350 0.2990 0.0450 ;
      RECT 0.2470 0.0350 0.2780 0.0450 ;
      RECT 0.2260 0.0350 0.2570 0.0450 ;
      RECT 0.2050 0.0350 0.2360 0.0450 ;
      RECT 0.3100 0.0550 0.3410 0.0650 ;
      RECT 0.3310 0.0550 0.3620 0.0650 ;
      RECT 0.6250 0.0750 0.6560 0.0850 ;
      RECT 0.4780 0.0350 0.5090 0.0450 ;
      RECT 0.3520 0.0550 0.3830 0.0650 ;
      RECT 0.6040 0.0750 0.6350 0.0850 ;
      RECT 0.4570 0.0350 0.4880 0.0450 ;
  END
END BUF_X16

MACRO BUF_X2
  CLASS CORE ;
  FOREIGN BUF_X2 0 0 ;
  ORIGIN -0.0210 0.0000 ;
  SIZE 0.1680 BY 0.1000 ;
  SITE NSFET ;
  SYMMETRY X Y ;
  PIN Z
    DIRECTION OUTPUT ;
    USE SIGNAL ;
    PORT
      LAYER M1 ;
        RECT 0.0350 0.0330 0.0490 0.0670 ;
    END
  END Z
  PIN A
    DIRECTION INPUT ;
    USE SIGNAL ;
    PORT
      LAYER M1 ;
        RECT 0.0770 0.0110 0.0910 0.0670 ;
    END
  END A
  PIN VDD
    DIRECTION INOUT ;
    USE POWER ;
    PORT
      LAYER M0 ;
        RECT -0.0370 0.0950 0.1630 0.1050 ;
    END
  END VDD
  PIN VSS
    DIRECTION INOUT ;
    USE GROUND ;
    PORT
      LAYER M0 ;
        RECT -0.0370 -0.0050 0.1630 0.0050 ;
    END
  END VSS
  OBS
    LAYER M1 ;
      RECT 0.1190 0.0330 0.1330 0.0670 ;
    LAYER M0 ;
      RECT 0.0160 0.0750 0.0470 0.0850 ;
      RECT 0.0370 0.0750 0.0680 0.0850 ;
      RECT 0.0580 0.0750 0.0890 0.0850 ;
      RECT 0.0790 0.0750 0.1100 0.0850 ;
      RECT 0.1000 0.0750 0.1310 0.0850 ;
      RECT 0.0370 0.0550 0.0470 0.0650 ;
      RECT 0.0370 0.0350 0.0470 0.0450 ;
      RECT 0.1210 0.0550 0.1310 0.0650 ;
      RECT 0.1210 0.0350 0.1310 0.0450 ;
      RECT 0.0370 0.0550 0.0470 0.0650 ;
      RECT 0.0370 0.0350 0.0470 0.0450 ;
      RECT 0.1210 0.0350 0.1310 0.0450 ;
      RECT 0.0760 0.0150 0.1110 0.0250 ;
  END
END BUF_X2

MACRO BUF_X32
  CLASS CORE ;
  FOREIGN BUF_X32 0 0 ;
  ORIGIN 0.0360 0.0350 ;
  SIZE 2.0580 BY 0.1000 ;
  SITE NSFET ;
  SYMMETRY X Y ;
  PIN A
    DIRECTION INPUT ;
    USE SIGNAL ;
    PORT
      LAYER M1 ;
        RECT 0.7220 0.0880 0.7360 0.1020 ;
    END
  END A
  PIN Z
    DIRECTION OUTPUT ;
    USE SIGNAL ;
    PORT
      LAYER M1 ;
        RECT 0.7640 0.0480 0.7780 0.1220 ;
    END
  END Z
  PIN VDD
    DIRECTION INOUT ;
    USE POWER ;
    PORT
      LAYER M0 ;
        RECT 0.0200 0.1300 2.1100 0.1400 ;
    END
  END VDD
  PIN VSS
    DIRECTION INOUT ;
    USE GROUND ;
    PORT
      LAYER M0 ;
        RECT 0.0200 0.0300 2.1100 0.0400 ;
    END
  END VSS
  OBS
    LAYER M1 ;
      RECT 0.6800 0.0480 0.6940 0.1230 ;
    LAYER M0 ;
      RECT 0.7660 0.0500 2.0360 0.0600 ;
      RECT 0.0730 0.0900 0.7340 0.1000 ;
      RECT 0.6800 0.0700 2.0570 0.0800 ;
      RECT 0.7660 0.1100 2.0360 0.1200 ;
      RECT 0.0940 0.0500 0.6920 0.0600 ;
      RECT 0.0940 0.1100 0.6920 0.1200 ;
  END
END BUF_X32

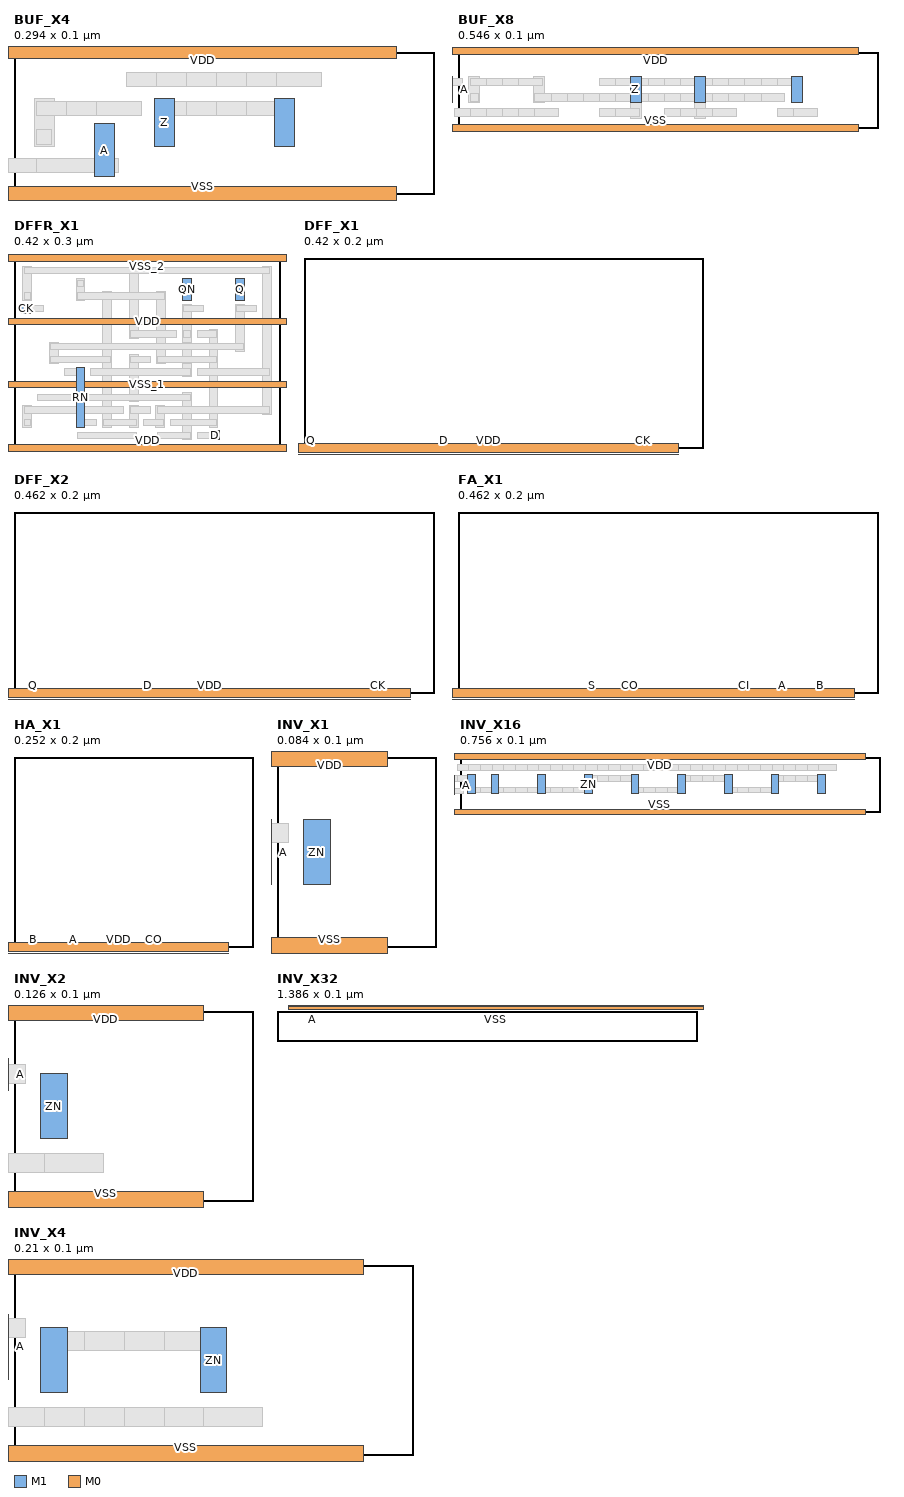
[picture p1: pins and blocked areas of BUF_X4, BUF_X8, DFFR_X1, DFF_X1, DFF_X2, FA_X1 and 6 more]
MACRO BUF_X4
  CLASS CORE ;
  FOREIGN BUF_X4 0 0 ;
  ORIGIN -0.0210 0.0000 ;
  SIZE 0.2940 BY 0.1000 ;
  SITE NSFET ;
  SYMMETRY X Y ;
  PIN Z
    DIRECTION OUTPUT ;
    USE SIGNAL ;
    PORT
      LAYER M1 ;
        RECT 0.1190 0.0330 0.1330 0.0670 ;
        RECT 0.2030 0.0330 0.2170 0.0670 ;
    END
  END Z
  PIN A
    DIRECTION INPUT ;
    USE SIGNAL ;
    PORT
      LAYER M1 ;
        RECT 0.0770 0.0120 0.0910 0.0490 ;
    END
  END A
  PIN VSS
    DIRECTION INOUT ;
    USE GROUND ;
    PORT
      LAYER M0 ;
        RECT -0.0370 -0.0050 0.2890 0.0050 ;
    END
  END VSS
  PIN VDD
    DIRECTION INOUT ;
    USE POWER ;
    PORT
      LAYER M0 ;
        RECT -0.0370 0.0950 0.2890 0.1050 ;
    END
  END VDD
  OBS
    LAYER M1 ;
      RECT 0.0350 0.0330 0.0490 0.0670 ;
    LAYER M0 ;
      RECT 0.1000 0.0750 0.1310 0.0850 ;
      RECT 0.1210 0.0750 0.1520 0.0850 ;
      RECT 0.1420 0.0750 0.1730 0.0850 ;
      RECT 0.1630 0.0750 0.1940 0.0850 ;
      RECT 0.1840 0.0750 0.2150 0.0850 ;
      RECT 0.2050 0.0750 0.2360 0.0850 ;
      RECT 0.0370 0.0550 0.0680 0.0650 ;
      RECT 0.0580 0.0550 0.0890 0.0650 ;
      RECT 0.0790 0.0550 0.1100 0.0650 ;
      RECT 0.1210 0.0550 0.1520 0.0650 ;
      RECT 0.1420 0.0550 0.1730 0.0650 ;
      RECT 0.1630 0.0550 0.1940 0.0650 ;
      RECT 0.1840 0.0550 0.2150 0.0650 ;
      RECT 0.0160 0.0150 0.0470 0.0250 ;
      RECT 0.0370 0.0150 0.0680 0.0250 ;
      RECT 0.0370 0.0350 0.0470 0.0450 ;
      RECT 0.1210 0.0350 0.1310 0.0450 ;
      RECT 0.2050 0.0350 0.2150 0.0450 ;
      RECT 0.0160 0.0150 0.0470 0.0250 ;
      RECT 0.0370 0.0150 0.0940 0.0250 ;
  END
END BUF_X4

MACRO BUF_X8
  CLASS CORE ;
  FOREIGN BUF_X8 0 0 ;
  ORIGIN -0.0210 0.0000 ;
  SIZE 0.5460 BY 0.1000 ;
  SITE NSFET ;
  SYMMETRY X Y ;
  PIN Z
    DIRECTION OUTPUT ;
    USE SIGNAL ;
    PORT
      LAYER M1 ;
        RECT 0.2450 0.0330 0.2590 0.0670 ;
        RECT 0.3290 0.0330 0.3430 0.0670 ;
        RECT 0.4550 0.0330 0.4690 0.0670 ;
        RECT 0.2450 0.0330 0.2590 0.0670 ;
        RECT 0.3290 0.0330 0.3430 0.0670 ;
        RECT 0.4550 0.0330 0.4690 0.0670 ;
    END
  END Z
  PIN A
    DIRECTION INPUT ;
    USE SIGNAL ;
    PORT
      LAYER M1 ;
        RECT -0.0070 0.0330 0.0070 0.0670 ;
    END
  END A
  PIN VSS
    DIRECTION INOUT ;
    USE GROUND ;
    PORT
      LAYER M0 ;
        RECT -0.0370 -0.0050 0.5410 0.0050 ;
    END
  END VSS
  PIN VDD
    DIRECTION INOUT ;
    USE POWER ;
    PORT
      LAYER M0 ;
        RECT -0.0370 0.0950 0.5410 0.1050 ;
    END
  END VDD
  OBS
    LAYER M1 ;
      RECT 0.0350 0.0330 0.0490 0.0670 ;
      RECT 0.1190 0.0330 0.1330 0.0670 ;
      RECT 0.2450 0.0130 0.2590 0.0470 ;
      RECT 0.3290 0.0130 0.3430 0.0470 ;
      RECT 0.2450 0.0130 0.2590 0.0470 ;
      RECT 0.3290 0.0130 0.3430 0.0470 ;
    LAYER M0 ;
      RECT 0.0370 0.0550 0.0680 0.0650 ;
      RECT 0.0580 0.0550 0.0890 0.0650 ;
      RECT 0.0790 0.0550 0.1100 0.0650 ;
      RECT 0.1000 0.0550 0.1310 0.0650 ;
      RECT 0.1210 0.0350 0.1520 0.0450 ;
      RECT 0.1420 0.0350 0.1730 0.0450 ;
      RECT 0.1630 0.0350 0.1940 0.0450 ;
      RECT 0.1840 0.0350 0.2150 0.0450 ;
      RECT 0.2050 0.0350 0.2360 0.0450 ;
      RECT 0.2260 0.0350 0.2570 0.0450 ;
      RECT 0.2470 0.0350 0.2780 0.0450 ;
      RECT 0.2680 0.0350 0.2990 0.0450 ;
      RECT 0.2890 0.0350 0.3200 0.0450 ;
      RECT 0.3100 0.0350 0.3410 0.0450 ;
      RECT 0.3310 0.0350 0.3620 0.0450 ;
      RECT 0.3520 0.0350 0.3830 0.0450 ;
      RECT 0.3730 0.0350 0.4040 0.0450 ;
      RECT 0.3940 0.0350 0.4250 0.0450 ;
      RECT 0.4150 0.0350 0.4460 0.0450 ;
      RECT 0.4360 0.0150 0.4670 0.0250 ;
      RECT 0.4570 0.0150 0.4880 0.0250 ;
      RECT 0.2050 0.0550 0.2360 0.0650 ;
      RECT 0.2260 0.0550 0.2570 0.0650 ;
      RECT 0.2470 0.0550 0.2780 0.0650 ;
      RECT 0.2680 0.0550 0.2990 0.0650 ;
      RECT 0.2890 0.0550 0.3200 0.0650 ;
      RECT 0.3100 0.0550 0.3410 0.0650 ;
      RECT 0.3310 0.0550 0.3620 0.0650 ;
      RECT 0.3520 0.0550 0.3830 0.0650 ;
      RECT 0.3730 0.0550 0.4040 0.0650 ;
      RECT 0.3940 0.0550 0.4250 0.0650 ;
      RECT 0.4150 0.0550 0.4460 0.0650 ;
      RECT 0.4360 0.0550 0.4670 0.0650 ;
      RECT 0.2050 0.0150 0.2360 0.0250 ;
      RECT 0.2260 0.0150 0.2570 0.0250 ;
      RECT 0.2890 0.0150 0.3200 0.0250 ;
      RECT 0.3100 0.0150 0.3410 0.0250 ;
      RECT 0.3310 0.0150 0.3620 0.0250 ;
      RECT 0.3520 0.0150 0.3830 0.0250 ;
      RECT 0.0160 0.0150 0.0470 0.0250 ;
      RECT 0.0370 0.0150 0.0680 0.0250 ;
      RECT 0.0580 0.0150 0.0890 0.0250 ;
      RECT 0.0790 0.0150 0.1100 0.0250 ;
      RECT 0.1000 0.0150 0.1310 0.0250 ;
      RECT 0.1210 0.0150 0.1520 0.0250 ;
      RECT 0.0370 0.0350 0.0470 0.0450 ;
      RECT 0.4570 0.0350 0.4670 0.0450 ;
      RECT -0.0060 0.0550 0.0270 0.0650 ;
      RECT 0.2050 0.0550 0.2360 0.0650 ;
      RECT 0.2260 0.0550 0.2570 0.0650 ;
      RECT 0.2470 0.0550 0.2780 0.0650 ;
      RECT 0.2680 0.0550 0.2990 0.0650 ;
      RECT 0.2890 0.0550 0.3200 0.0650 ;
      RECT 0.3100 0.0550 0.3410 0.0650 ;
      RECT 0.3310 0.0550 0.3620 0.0650 ;
      RECT 0.3520 0.0550 0.3830 0.0650 ;
      RECT 0.3730 0.0550 0.4040 0.0650 ;
      RECT 0.3940 0.0550 0.4250 0.0650 ;
      RECT 0.4150 0.0550 0.4460 0.0650 ;
      RECT 0.4360 0.0550 0.4670 0.0650 ;
      RECT 0.4570 0.0350 0.4670 0.0450 ;
  END
END BUF_X8

MACRO DFFR_X1
  CLASS CORE ;
  FOREIGN DFFR_X1 0 0 ;
  ORIGIN 0.0000 0.0000 ;
  SIZE 0.4200 BY 0.3000 ;
  SITE NSFET ;
  SYMMETRY X Y ;
  PIN D
    DIRECTION INPUT ;
    USE SIGNAL ;
    PORT
      LAYER M1 ;
        RECT 0.3100 0.0130 0.3240 0.0270 ;
    END
  END D
  PIN RN
    DIRECTION INPUT ;
    USE SIGNAL ;
    PORT
      LAYER M1 ;
        RECT 0.0980 0.0330 0.1120 0.1270 ;
    END
  END RN
  PIN Q
    DIRECTION OUTPUT ;
    USE SIGNAL ;
    PORT
      LAYER M1 ;
        RECT 0.3500 0.2330 0.3640 0.2670 ;
    END
  END Q
  PIN QN
    DIRECTION OUTPUT ;
    USE SIGNAL ;
    PORT
      LAYER M1 ;
        RECT 0.2660 0.2330 0.2800 0.2670 ;
    END
  END QN
  PIN CK
    DIRECTION INPUT ;
    USE CLOCK ;
    PORT
      LAYER M1 ;
        RECT 0.0120 0.2130 0.0260 0.2270 ;
    END
  END CK
  PIN VSS_2
    DIRECTION INOUT ;
    USE GROUND ;
    PORT
      LAYER M0 ;
        RECT -0.0160 0.2950 0.4360 0.3050 ;
    END
  END VSS_2
  PIN VDD
    DIRECTION INOUT ;
    USE POWER ;
    PORT
      LAYER M0 ;
        RECT -0.0160 0.1950 0.4360 0.2050 ;
    END
  END VDD
  PIN VDD
    DIRECTION INOUT ;
    USE POWER ;
    PORT
      LAYER M0 ;
        RECT -0.0160 -0.0050 0.4360 0.0050 ;
    END
  END VDD
  PIN VSS_1
    DIRECTION INOUT ;
    USE GROUND ;
    PORT
      LAYER M0 ;
        RECT -0.0160 0.0950 0.4360 0.1050 ;
    END
  END VSS_1
  OBS
    LAYER M1 ;
      RECT 0.1400 0.0330 0.1540 0.2470 ;
      RECT 0.2660 0.1130 0.2800 0.2270 ;
      RECT 0.0560 0.1330 0.0700 0.1670 ;
      RECT 0.2660 0.1330 0.2800 0.1670 ;
      RECT 0.3500 0.1530 0.3640 0.2270 ;
      RECT 0.2250 0.1330 0.2390 0.2470 ;
      RECT 0.1820 0.1730 0.1960 0.2870 ;
      RECT 0.3080 0.0330 0.3220 0.1870 ;
      RECT 0.1820 0.0330 0.1960 0.0670 ;
      RECT 0.1820 0.0730 0.1960 0.1470 ;
      RECT 0.3920 0.0530 0.4060 0.2870 ;
      RECT 0.0140 0.0330 0.0280 0.0670 ;
      RECT 0.0140 0.2330 0.0280 0.2870 ;
      RECT 0.2240 0.0330 0.2380 0.0670 ;
      RECT 0.2660 0.0130 0.2800 0.0870 ;
      RECT 0.0980 0.2330 0.1120 0.2670 ;
    LAYER M0 ;
      RECT 0.2890 0.0150 0.3220 0.0250 ;
      RECT 0.1420 0.0350 0.1940 0.0450 ;
      RECT 0.2680 0.1750 0.2780 0.1850 ;
      RECT 0.1210 0.1150 0.2780 0.1250 ;
      RECT 0.0580 0.1350 0.1520 0.1450 ;
      RECT 0.1840 0.1750 0.2570 0.1850 ;
      RECT 0.2270 0.1350 0.3200 0.1450 ;
      RECT 0.2890 0.1750 0.3200 0.1850 ;
      RECT 0.0790 0.1150 0.1100 0.1250 ;
      RECT 0.3520 0.2150 0.3830 0.2250 ;
      RECT 0.0580 0.1550 0.3620 0.1650 ;
      RECT 0.1840 0.1350 0.2150 0.1450 ;
      RECT 0.2890 0.1150 0.4040 0.1250 ;
      RECT 0.0160 0.0550 0.1730 0.0650 ;
      RECT 0.0160 0.0350 0.0260 0.0450 ;
      RECT 0.2680 0.2150 0.2990 0.2250 ;
      RECT 0.0980 0.0350 0.1310 0.0450 ;
      RECT 0.1840 0.0550 0.2150 0.0650 ;
      RECT 0.2470 0.0350 0.3200 0.0450 ;
      RECT 0.3520 0.2550 0.3620 0.2650 ;
      RECT 0.2680 0.2350 0.2780 0.2450 ;
      RECT 0.3520 0.2350 0.3620 0.2450 ;
      RECT 0.2680 0.2550 0.2780 0.2650 ;
      RECT 0.0160 0.2350 0.0260 0.2450 ;
      RECT 0.2260 0.0150 0.2780 0.0250 ;
      RECT 0.1000 0.2550 0.1100 0.2650 ;
      RECT 0.2050 0.0350 0.2360 0.0450 ;
      RECT 0.2260 0.0550 0.4040 0.0650 ;
      RECT 0.0140 0.2150 0.0470 0.2250 ;
      RECT 0.1000 0.2350 0.2370 0.2450 ;
      RECT 0.0160 0.2750 0.4040 0.2850 ;
      RECT 0.0370 0.0750 0.2780 0.0850 ;
      RECT 0.1000 0.0150 0.1940 0.0250 ;
  END
END DFFR_X1

MACRO DFF_X1
  CLASS CORE ;
  FOREIGN DFF_X1 0 0 ;
  ORIGIN -0.0210 -0.1000 ;
  SIZE 0.4200 BY 0.2000 ;
  SITE NSFET ;
  SYMMETRY X Y ;
  PIN Q
    DIRECTION OUTPUT ;
    USE SIGNAL ;
    PORT
      LAYER M1 ;
        RECT -0.0070 0.0330 0.0070 0.0670 ;
        RECT -0.0070 0.0330 0.0070 0.0670 ;
    END
  END Q
  PIN QN
    DIRECTION OUTPUT ;
    USE SIGNAL ;
    PORT
      LAYER M1 ;
        RECT -0.0070 -0.0670 0.0070 -0.0330 ;
        RECT -0.0070 -0.0670 0.0070 -0.0330 ;
    END
  END QN
  PIN D
    DIRECTION INPUT ;
    USE SIGNAL ;
    PORT
      LAYER M1 ;
        RECT 0.1610 0.0490 0.1750 0.0830 ;
    END
  END D
  PIN CK
    DIRECTION INPUT ;
    USE CLOCK ;
    PORT
      LAYER M1 ;
        RECT 0.3710 -0.0870 0.3850 -0.0730 ;
    END
  END CK
  PIN VDD
    DIRECTION INOUT ;
    USE POWER ;
    PORT
      LAYER M0 ;
        RECT -0.0370 0.0950 0.4150 0.1050 ;
    END
  END VDD
  PIN VDD
    DIRECTION INOUT ;
    USE POWER ;
    PORT
      LAYER M0 ;
        RECT -0.0370 -0.1050 0.4150 -0.0950 ;
    END
  END VDD
  PIN VSS
    DIRECTION INOUT ;
    USE GROUND ;
    PORT
      LAYER M0 ;
        RECT -0.0370 -0.0050 0.4150 0.0050 ;
    END
  END VSS
  OBS
    LAYER M1 ;
      RECT 0.0770 0.0330 0.0910 0.0670 ;
      RECT 0.0770 0.0130 0.0910 0.0470 ;
      RECT 0.0770 -0.0070 0.0910 0.0270 ;
      RECT 0.0770 -0.0270 0.0910 0.0070 ;
      RECT 0.0350 -0.0070 0.0490 0.0270 ;
      RECT 0.0350 -0.0270 0.0490 0.0070 ;
      RECT 0.0350 -0.0470 0.0490 -0.0130 ;
      RECT 0.1610 -0.0670 0.1750 -0.0330 ;
      RECT 0.2030 0.0330 0.2170 0.0670 ;
      RECT 0.2030 0.0130 0.2170 0.0470 ;
      RECT 0.2030 -0.0070 0.2170 0.0270 ;
      RECT 0.2030 -0.0270 0.2170 0.0070 ;
      RECT 0.2030 -0.0470 0.2170 -0.0130 ;
      RECT 0.2030 -0.0670 0.2170 -0.0330 ;
      RECT 0.2030 -0.0870 0.2170 -0.0530 ;
      RECT 0.2870 -0.0670 0.3010 -0.0330 ;
      RECT 0.1610 -0.0070 0.1750 0.0270 ;
      RECT 0.1610 -0.0270 0.1750 0.0070 ;
      RECT 0.2450 0.0330 0.2590 0.0670 ;
      RECT 0.2450 0.0130 0.2590 0.0470 ;
      RECT 0.2450 -0.0070 0.2590 0.0270 ;
      RECT 0.2450 -0.0270 0.2590 0.0070 ;
      RECT 0.2450 -0.0470 0.2590 -0.0130 ;
      RECT 0.2450 -0.0670 0.2590 -0.0330 ;
      RECT 0.3710 -0.0470 0.3850 -0.0130 ;
      RECT 0.3710 -0.0670 0.3850 -0.0330 ;
      RECT 0.2870 0.0530 0.3010 0.0870 ;
      RECT 0.2870 0.0330 0.3010 0.0670 ;
      RECT 0.2870 0.0130 0.3010 0.0470 ;
      RECT 0.3290 -0.0070 0.3430 0.0270 ;
      RECT 0.3290 -0.0270 0.3430 0.0070 ;
      RECT 0.3290 -0.0470 0.3430 -0.0130 ;
      RECT 0.3290 -0.0670 0.3430 -0.0330 ;
      RECT 0.3290 -0.0870 0.3430 -0.0530 ;
      RECT 0.3710 0.0330 0.3850 0.0670 ;
      RECT 0.0770 0.0330 0.0910 0.0670 ;
      RECT 0.0770 0.0130 0.0910 0.0470 ;
      RECT 0.0770 -0.0070 0.0910 0.0270 ;
      RECT 0.0770 -0.0270 0.0910 0.0070 ;
      RECT 0.0350 -0.0070 0.0490 0.0270 ;
      RECT 0.0350 -0.0270 0.0490 0.0070 ;
      RECT 0.0350 -0.0470 0.0490 -0.0130 ;
      RECT 0.1610 -0.0670 0.1750 -0.0330 ;
      RECT 0.2030 0.0330 0.2170 0.0670 ;
      RECT 0.2030 0.0130 0.2170 0.0470 ;
      RECT 0.2030 -0.0070 0.2170 0.0270 ;
      RECT 0.2030 -0.0270 0.2170 0.0070 ;
      RECT 0.2030 -0.0470 0.2170 -0.0130 ;
      RECT 0.2030 -0.0670 0.2170 -0.0330 ;
      RECT 0.2030 -0.0870 0.2170 -0.0530 ;
      RECT 0.2870 -0.0670 0.3010 -0.0330 ;
      RECT 0.1610 -0.0070 0.1750 0.0270 ;
      RECT 0.1610 -0.0270 0.1750 0.0070 ;
      RECT 0.2450 0.0330 0.2590 0.0670 ;
      RECT 0.2450 0.0130 0.2590 0.0470 ;
      RECT 0.2450 -0.0070 0.2590 0.0270 ;
      RECT 0.2450 -0.0270 0.2590 0.0070 ;
      RECT 0.2450 -0.0470 0.2590 -0.0130 ;
      RECT 0.2450 -0.0670 0.2590 -0.0330 ;
      RECT 0.3710 -0.0470 0.3850 -0.0130 ;
      RECT 0.3710 -0.0670 0.3850 -0.0330 ;
      RECT 0.2870 0.0530 0.3010 0.0870 ;
      RECT 0.2870 0.0330 0.3010 0.0670 ;
      RECT 0.2870 0.0130 0.3010 0.0470 ;
      RECT 0.3290 -0.0070 0.3430 0.0270 ;
      RECT 0.3290 -0.0270 0.3430 0.0070 ;
      RECT 0.3290 -0.0470 0.3430 -0.0130 ;
      RECT 0.3290 -0.0670 0.3430 -0.0330 ;
      RECT 0.3290 -0.0870 0.3430 -0.0530 ;
      RECT 0.3710 0.0330 0.3850 0.0670 ;
    LAYER M0 ;
      RECT 0.0160 0.0550 0.0470 0.0650 ;
      RECT 0.0370 0.0550 0.0680 0.0650 ;
      RECT 0.0580 0.0550 0.0890 0.0650 ;
      RECT 0.0790 -0.0250 0.1100 -0.0150 ;
      RECT 0.0370 0.0150 0.0680 0.0250 ;
      RECT 0.0160 -0.0450 0.0470 -0.0350 ;
      RECT 0.0370 -0.0450 0.0680 -0.0350 ;
      RECT 0.0580 -0.0450 0.0890 -0.0350 ;
      RECT 0.0790 -0.0450 0.1100 -0.0350 ;
      RECT 0.1000 -0.0450 0.1310 -0.0350 ;
      RECT 0.1210 -0.0450 0.1520 -0.0350 ;
      RECT 0.1420 -0.0450 0.1730 -0.0350 ;
      RECT 0.1840 0.0550 0.2150 0.0650 ;
      RECT 0.2050 0.0350 0.2360 0.0450 ;
      RECT 0.1840 -0.0450 0.2150 -0.0350 ;
      RECT 0.2050 -0.0450 0.2360 -0.0350 ;
      RECT 0.2260 -0.0450 0.2570 -0.0350 ;
      RECT 0.2470 -0.0450 0.2780 -0.0350 ;
      RECT 0.2680 -0.0450 0.2990 -0.0350 ;
      RECT 0.1420 -0.0850 0.1730 -0.0750 ;
      RECT 0.1630 -0.0850 0.1940 -0.0750 ;
      RECT 0.1840 -0.0850 0.2150 -0.0750 ;
      RECT 0.2260 0.0550 0.2570 0.0650 ;
      RECT 0.1630 0.0150 0.1940 0.0250 ;
      RECT 0.1420 -0.0250 0.1730 -0.0150 ;
      RECT 0.1630 -0.0250 0.1940 -0.0150 ;
      RECT 0.1840 -0.0250 0.2150 -0.0150 ;
      RECT 0.2050 -0.0250 0.2360 -0.0150 ;
      RECT 0.2260 -0.0250 0.2570 -0.0150 ;
      RECT 0.2470 -0.0250 0.2780 -0.0150 ;
      RECT 0.2680 -0.0250 0.2990 -0.0150 ;
      RECT 0.2890 -0.0250 0.3200 -0.0150 ;
      RECT 0.3100 -0.0250 0.3410 -0.0150 ;
      RECT 0.3310 -0.0250 0.3620 -0.0150 ;
      RECT 0.3520 -0.0250 0.3830 -0.0150 ;
      RECT 0.1840 -0.0650 0.2150 -0.0550 ;
      RECT 0.2050 -0.0650 0.2360 -0.0550 ;
      RECT 0.2260 -0.0650 0.2570 -0.0550 ;
      RECT 0.2050 0.0750 0.2360 0.0850 ;
      RECT 0.2260 0.0750 0.2570 0.0850 ;
      RECT 0.2470 0.0750 0.2780 0.0850 ;
      RECT 0.2680 0.0750 0.2990 0.0850 ;
      RECT 0.2050 0.0150 0.2360 0.0250 ;
      RECT 0.2260 0.0150 0.2570 0.0250 ;
      RECT 0.2470 0.0150 0.2780 0.0250 ;
      RECT 0.2680 0.0150 0.2990 0.0250 ;
      RECT 0.2890 0.0150 0.3200 0.0250 ;
      RECT 0.3100 0.0150 0.3410 0.0250 ;
      RECT 0.3310 0.0150 0.3620 0.0250 ;
      RECT 0.2260 -0.0850 0.2570 -0.0750 ;
      RECT 0.2470 -0.0850 0.2780 -0.0750 ;
      RECT 0.2680 -0.0850 0.2990 -0.0750 ;
      RECT 0.2890 -0.0850 0.3200 -0.0750 ;
      RECT 0.3100 -0.0850 0.3410 -0.0750 ;
      RECT 0.2680 0.0550 0.2990 0.0650 ;
      RECT 0.2890 0.0550 0.3200 0.0650 ;
      RECT 0.3100 0.0550 0.3410 0.0650 ;
      RECT 0.3310 0.0550 0.3620 0.0650 ;
      RECT 0.3520 0.0550 0.3830 0.0650 ;
      RECT 0.0790 0.0350 0.0890 0.0450 ;
      RECT 0.0790 0.0150 0.0890 0.0250 ;
      RECT 0.1630 -0.0650 0.1730 -0.0550 ;
      RECT 0.2890 -0.0650 0.2990 -0.0550 ;
      RECT 0.3730 -0.0450 0.3830 -0.0350 ;
      RECT 0.3730 -0.0650 0.3830 -0.0550 ;
      RECT 0.3730 0.0350 0.3830 0.0450 ;
      RECT -0.0050 0.0550 0.0050 0.0650 ;
      RECT -0.0050 0.0350 0.0050 0.0450 ;
      RECT -0.0050 -0.0450 0.0050 -0.0350 ;
      RECT -0.0050 -0.0650 0.0050 -0.0550 ;
      RECT 0.0160 0.0550 0.0470 0.0650 ;
      RECT 0.0370 0.0550 0.0680 0.0650 ;
      RECT 0.0580 0.0550 0.0890 0.0650 ;
      RECT 0.0370 0.0150 0.0680 0.0250 ;
      RECT 0.1840 0.0550 0.2150 0.0650 ;
      RECT 0.2050 0.0350 0.2360 0.0450 ;
      RECT 0.2260 0.0550 0.2570 0.0650 ;
      RECT 0.1630 0.0150 0.1940 0.0250 ;
      RECT 0.2050 0.0750 0.2360 0.0850 ;
      RECT 0.2260 0.0750 0.2570 0.0850 ;
      RECT 0.2470 0.0750 0.2780 0.0850 ;
      RECT 0.2680 0.0750 0.2990 0.0850 ;
      RECT 0.2050 0.0150 0.2360 0.0250 ;
      RECT 0.2260 0.0150 0.2570 0.0250 ;
      RECT 0.2470 0.0150 0.2780 0.0250 ;
      RECT 0.2680 0.0150 0.2990 0.0250 ;
      RECT 0.2890 0.0150 0.3200 0.0250 ;
      RECT 0.3100 0.0150 0.3410 0.0250 ;
      RECT 0.3310 0.0150 0.3620 0.0250 ;
      RECT 0.3510 -0.0850 0.3850 -0.0750 ;
      RECT 0.2470 -0.0450 0.2780 -0.0350 ;
      RECT 0.2680 -0.0450 0.2990 -0.0350 ;
      RECT 0.1420 -0.0850 0.1730 -0.0750 ;
      RECT 0.1630 -0.0850 0.1940 -0.0750 ;
      RECT 0.1840 -0.0850 0.2150 -0.0750 ;
      RECT 0.1420 -0.0250 0.1730 -0.0150 ;
      RECT 0.1630 -0.0250 0.1940 -0.0150 ;
      RECT 0.1840 -0.0250 0.2150 -0.0150 ;
      RECT 0.2050 -0.0250 0.2360 -0.0150 ;
      RECT 0.2260 -0.0250 0.2570 -0.0150 ;
      RECT 0.2470 -0.0250 0.2780 -0.0150 ;
      RECT 0.2680 -0.0250 0.2990 -0.0150 ;
      RECT 0.2890 -0.0250 0.3200 -0.0150 ;
      RECT 0.3100 -0.0250 0.3410 -0.0150 ;
      RECT 0.3310 -0.0250 0.3620 -0.0150 ;
      RECT 0.3520 -0.0250 0.3830 -0.0150 ;
      RECT 0.1840 -0.0650 0.2150 -0.0550 ;
      RECT 0.2050 -0.0650 0.2360 -0.0550 ;
      RECT 0.2260 -0.0650 0.2570 -0.0550 ;
      RECT 0.2260 -0.0850 0.2570 -0.0750 ;
      RECT 0.2470 -0.0850 0.2780 -0.0750 ;
      RECT 0.2680 -0.0850 0.2990 -0.0750 ;
      RECT 0.2890 -0.0850 0.3200 -0.0750 ;
      RECT 0.3100 -0.0850 0.3410 -0.0750 ;
      RECT 0.1630 -0.0650 0.1730 -0.0550 ;
      RECT 0.2890 -0.0650 0.2990 -0.0550 ;
      RECT 0.3730 -0.0450 0.3830 -0.0350 ;
      RECT 0.3730 -0.0650 0.3830 -0.0550 ;
      RECT -0.0050 -0.0450 0.0050 -0.0350 ;
      RECT -0.0050 -0.0650 0.0050 -0.0550 ;
      RECT 0.2050 -0.0450 0.2360 -0.0350 ;
      RECT 0.1840 -0.0450 0.2150 -0.0350 ;
      RECT 0.1420 -0.0450 0.1730 -0.0350 ;
      RECT 0.1210 -0.0450 0.1520 -0.0350 ;
      RECT 0.0580 -0.0450 0.1310 -0.0350 ;
      RECT 0.0790 -0.0450 0.1100 -0.0350 ;
      RECT 0.0580 -0.0450 0.0890 -0.0350 ;
      RECT 0.0370 -0.0450 0.0680 -0.0350 ;
      RECT 0.0160 -0.0450 0.0470 -0.0350 ;
      RECT 0.0790 -0.0250 0.1100 -0.0150 ;
      RECT -0.0050 0.0350 0.0050 0.0450 ;
      RECT -0.0050 0.0550 0.0050 0.0650 ;
      RECT 0.3730 0.0350 0.3830 0.0450 ;
      RECT 0.0790 0.0150 0.0890 0.0250 ;
      RECT 0.0790 0.0350 0.0890 0.0450 ;
      RECT 0.1420 0.0550 0.1730 0.0650 ;
      RECT 0.3520 0.0550 0.3830 0.0650 ;
      RECT 0.3310 0.0550 0.3620 0.0650 ;
      RECT 0.3100 0.0550 0.3410 0.0650 ;
      RECT 0.2890 0.0550 0.3200 0.0650 ;
      RECT 0.2680 0.0550 0.2990 0.0650 ;
      RECT 0.2260 -0.0450 0.2570 -0.0350 ;
  END
END DFF_X1

MACRO DFF_X2
  CLASS CORE ;
  FOREIGN DFF_X2 0 0 ;
  ORIGIN -0.0210 -0.1000 ;
  SIZE 0.4620 BY 0.2000 ;
  SITE NSFET ;
  SYMMETRY X Y ;
  PIN D
    DIRECTION INPUT ;
    USE SIGNAL ;
    PORT
      LAYER M1 ;
        RECT 0.1610 0.0330 0.1750 0.0670 ;
    END
  END D
  PIN Q
    DIRECTION OUTPUT ;
    USE SIGNAL ;
    PORT
      LAYER M1 ;
        RECT 0.0350 0.0330 0.0490 0.0670 ;
    END
  END Q
  PIN QN
    DIRECTION OUTPUT ;
    USE SIGNAL ;
    PORT
      LAYER M1 ;
        RECT 0.0350 -0.0670 0.0490 -0.0330 ;
    END
  END QN
  PIN CK
    DIRECTION INPUT ;
    USE CLOCK ;
    PORT
      LAYER M1 ;
        RECT 0.4140 -0.0270 0.4280 -0.0130 ;
    END
  END CK
  PIN VDD
    DIRECTION INOUT ;
    USE POWER ;
    PORT
      LAYER M0 ;
        RECT -0.0370 -0.1050 0.4570 -0.0950 ;
    END
  END VDD
  PIN VDD
    DIRECTION INOUT ;
    USE POWER ;
    PORT
      LAYER M0 ;
        RECT -0.0370 0.0950 0.4570 0.1050 ;
    END
  END VDD
  PIN VSS
    DIRECTION INOUT ;
    USE GROUND ;
    PORT
      LAYER M0 ;
        RECT -0.0370 -0.0050 0.4570 0.0050 ;
    END
  END VSS
  OBS
    LAYER M1 ;
      RECT 0.0770 -0.0070 0.0910 0.0270 ;
      RECT 0.0770 -0.0270 0.0910 0.0070 ;
      RECT 0.0770 -0.0470 0.0910 -0.0130 ;
      RECT 0.2030 -0.0670 0.2170 -0.0330 ;
      RECT 0.2450 0.0330 0.2590 0.0670 ;
      RECT 0.2450 0.0130 0.2590 0.0470 ;
      RECT 0.2450 -0.0070 0.2590 0.0270 ;
      RECT 0.2450 -0.0270 0.2590 0.0070 ;
      RECT 0.2450 -0.0470 0.2590 -0.0130 ;
      RECT 0.2450 -0.0670 0.2590 -0.0330 ;
      RECT 0.2450 -0.0870 0.2590 -0.0530 ;
      RECT 0.3290 -0.0670 0.3430 -0.0330 ;
      RECT 0.2030 -0.0070 0.2170 0.0270 ;
      RECT 0.2030 -0.0270 0.2170 0.0070 ;
      RECT 0.2870 0.0330 0.3010 0.0670 ;
      RECT 0.2870 0.0130 0.3010 0.0470 ;
      RECT 0.2870 -0.0070 0.3010 0.0270 ;
      RECT 0.2870 -0.0270 0.3010 0.0070 ;
      RECT 0.2870 -0.0470 0.3010 -0.0130 ;
      RECT 0.2870 -0.0670 0.3010 -0.0330 ;
      RECT 0.4130 -0.0670 0.4270 -0.0330 ;
      RECT 0.3290 0.0530 0.3430 0.0870 ;
      RECT 0.3290 0.0330 0.3430 0.0670 ;
      RECT 0.3710 0.0130 0.3850 0.0470 ;
      RECT 0.3710 -0.0070 0.3850 0.0270 ;
      RECT 0.3710 -0.0270 0.3850 0.0070 ;
      RECT 0.3710 -0.0470 0.3850 -0.0130 ;
      RECT 0.3710 -0.0670 0.3850 -0.0330 ;
      RECT 0.3710 -0.0870 0.3850 -0.0530 ;
      RECT 0.4130 0.0330 0.4270 0.0670 ;
      RECT 0.1190 0.0330 0.1330 0.0670 ;
      RECT 0.1190 0.0130 0.1330 0.0470 ;
      RECT 0.1190 -0.0070 0.1330 0.0270 ;
      RECT 0.1190 -0.0270 0.1330 0.0070 ;
    LAYER M0 ;
      RECT 0.0790 0.0150 0.1100 0.0250 ;
      RECT 0.0160 -0.0250 0.0470 -0.0150 ;
      RECT 0.0370 -0.0250 0.0680 -0.0150 ;
      RECT 0.0580 -0.0250 0.0890 -0.0150 ;
      RECT 0.0790 -0.0450 0.1100 -0.0350 ;
      RECT 0.1000 -0.0450 0.1310 -0.0350 ;
      RECT 0.1210 -0.0450 0.1520 -0.0350 ;
      RECT 0.1420 -0.0450 0.1730 -0.0350 ;
      RECT 0.1630 -0.0450 0.1940 -0.0350 ;
      RECT 0.1840 -0.0450 0.2150 -0.0350 ;
      RECT 0.2260 0.0550 0.2570 0.0650 ;
      RECT 0.2470 0.0150 0.2780 0.0250 ;
      RECT 0.2260 -0.0450 0.2570 -0.0350 ;
      RECT 0.2470 -0.0450 0.2780 -0.0350 ;
      RECT 0.2680 -0.0450 0.2990 -0.0350 ;
      RECT 0.2890 -0.0450 0.3200 -0.0350 ;
      RECT 0.3100 -0.0450 0.3410 -0.0350 ;
      RECT 0.1840 -0.0850 0.2150 -0.0750 ;
      RECT 0.2050 -0.0850 0.2360 -0.0750 ;
      RECT 0.2260 -0.0850 0.2570 -0.0750 ;
      RECT 0.2680 0.0550 0.2990 0.0650 ;
      RECT 0.2050 0.0150 0.2360 0.0250 ;
      RECT 0.1840 -0.0250 0.2150 -0.0150 ;
      RECT 0.2050 -0.0250 0.2360 -0.0150 ;
      RECT 0.2260 -0.0250 0.2570 -0.0150 ;
      RECT 0.2470 -0.0250 0.2780 -0.0150 ;
      RECT 0.2680 -0.0250 0.2990 -0.0150 ;
      RECT 0.2890 -0.0250 0.3200 -0.0150 ;
      RECT 0.3100 -0.0250 0.3410 -0.0150 ;
      RECT 0.3310 -0.0250 0.3620 -0.0150 ;
      RECT 0.3520 -0.0450 0.3830 -0.0350 ;
      RECT 0.3730 -0.0450 0.4040 -0.0350 ;
      RECT 0.3940 -0.0450 0.4250 -0.0350 ;
      RECT 0.2260 -0.0650 0.2570 -0.0550 ;
      RECT 0.2470 -0.0650 0.2780 -0.0550 ;
      RECT 0.2680 -0.0650 0.2990 -0.0550 ;
      RECT 0.2470 0.0750 0.2780 0.0850 ;
      RECT 0.2680 0.0750 0.2990 0.0850 ;
      RECT 0.2890 0.0750 0.3200 0.0850 ;
      RECT 0.3100 0.0750 0.3410 0.0850 ;
      RECT 0.2470 0.0350 0.2780 0.0450 ;
      RECT 0.2680 0.0350 0.2990 0.0450 ;
      RECT 0.2890 0.0350 0.3200 0.0450 ;
      RECT 0.3100 0.0350 0.3410 0.0450 ;
      RECT 0.3310 0.0350 0.3620 0.0450 ;
      RECT 0.3520 0.0350 0.3830 0.0450 ;
      RECT 0.3730 0.0350 0.4040 0.0450 ;
      RECT 0.2680 -0.0850 0.2990 -0.0750 ;
      RECT 0.2890 -0.0850 0.3200 -0.0750 ;
      RECT 0.3100 -0.0850 0.3410 -0.0750 ;
      RECT 0.3310 -0.0850 0.3620 -0.0750 ;
      RECT 0.3520 -0.0850 0.3830 -0.0750 ;
      RECT 0.3100 0.0550 0.3410 0.0650 ;
      RECT 0.3310 0.0550 0.3620 0.0650 ;
      RECT 0.3520 0.0550 0.3830 0.0650 ;
      RECT 0.3730 0.0550 0.4040 0.0650 ;
      RECT 0.3940 0.0550 0.4250 0.0650 ;
      RECT 0.0160 0.0750 0.0470 0.0850 ;
      RECT 0.0370 0.0750 0.0680 0.0850 ;
      RECT 0.0580 0.0750 0.0890 0.0850 ;
      RECT 0.0790 0.0750 0.1100 0.0850 ;
      RECT 0.1000 0.0750 0.1310 0.0850 ;
      RECT 0.1210 -0.0250 0.1520 -0.0150 ;
      RECT 0.2050 -0.0650 0.2150 -0.0550 ;
      RECT 0.3310 -0.0650 0.3410 -0.0550 ;
      RECT 0.4150 -0.0650 0.4250 -0.0550 ;
      RECT 0.4150 0.0350 0.4250 0.0450 ;
      RECT 0.1210 0.0550 0.1310 0.0650 ;
      RECT 0.1210 0.0150 0.1310 0.0250 ;
      RECT 0.0370 0.0550 0.0470 0.0650 ;
      RECT 0.0370 0.0350 0.0470 0.0450 ;
      RECT 0.0370 -0.0450 0.0470 -0.0350 ;
      RECT 0.0370 -0.0650 0.0470 -0.0550 ;
      RECT 0.1630 0.0550 0.1940 0.0650 ;
      RECT 0.3940 -0.0250 0.4280 -0.0150 ;
  END
END DFF_X2

MACRO FA_X1
  CLASS CORE ;
  FOREIGN FA_X1 0 0 ;
  ORIGIN -0.0210 -0.1000 ;
  SIZE 0.4620 BY 0.2000 ;
  SITE NSFET ;
  SYMMETRY X Y ;
  PIN B
    DIRECTION INPUT ;
    USE SIGNAL ;
    PORT
      LAYER M1 ;
        RECT 0.0350 -0.0070 0.0490 0.0270 ;
        RECT 0.4130 0.0130 0.4270 0.0470 ;
        RECT 0.4130 -0.0070 0.4270 0.0270 ;
        RECT 0.0350 -0.0070 0.0490 0.0270 ;
        RECT 0.4130 0.0130 0.4270 0.0470 ;
        RECT 0.4130 -0.0070 0.4270 0.0270 ;
    END
  END B
  PIN CI
    DIRECTION INPUT ;
    USE SIGNAL ;
    PORT
      LAYER M1 ;
        RECT 0.3290 0.0130 0.3430 0.0470 ;
        RECT 0.3290 0.0130 0.3430 0.0470 ;
    END
  END CI
  PIN A
    DIRECTION INPUT ;
    USE SIGNAL ;
    PORT
      LAYER M1 ;
        RECT 0.0770 -0.0070 0.0910 0.0270 ;
        RECT 0.0770 -0.0270 0.0910 0.0070 ;
        RECT 0.3710 -0.0070 0.3850 0.0270 ;
        RECT 0.3710 -0.0270 0.3850 0.0070 ;
        RECT 0.0770 -0.0070 0.0910 0.0270 ;
        RECT 0.0770 -0.0270 0.0910 0.0070 ;
        RECT 0.3710 -0.0070 0.3850 0.0270 ;
        RECT 0.3710 -0.0270 0.3850 0.0070 ;
    END
  END A
  PIN S
    DIRECTION OUTPUT ;
    USE SIGNAL ;
    PORT
      LAYER M1 ;
        RECT 0.1610 0.0330 0.1750 0.0670 ;
        RECT 0.1610 0.0330 0.1750 0.0670 ;
    END
  END S
  PIN CO
    DIRECTION OUTPUT ;
    USE SIGNAL ;
    PORT
      LAYER M1 ;
        RECT 0.2030 -0.0670 0.2170 -0.0330 ;
        RECT 0.2030 -0.0670 0.2170 -0.0330 ;
    END
  END CO
  PIN VDD
    DIRECTION INOUT ;
    USE POWER ;
    PORT
      LAYER M0 ;
        RECT -0.0370 0.0950 0.4570 0.1050 ;
    END
  END VDD
  PIN VSS
    DIRECTION INOUT ;
    USE GROUND ;
    PORT
      LAYER M0 ;
        RECT -0.0370 -0.0050 0.4570 0.0050 ;
    END
  END VSS
  PIN VDD
    DIRECTION INOUT ;
    USE POWER ;
    PORT
      LAYER M0 ;
        RECT -0.0370 -0.1050 0.4570 -0.0950 ;
    END
  END VDD
  OBS
    LAYER M1 ;
      RECT 0.0350 0.0530 0.0490 0.0870 ;
      RECT 0.0350 0.0330 0.0490 0.0670 ;
      RECT 0.0350 0.0130 0.0490 0.0470 ;
      RECT 0.0350 -0.0270 0.0490 0.0070 ;
      RECT 0.0350 -0.0470 0.0490 -0.0130 ;
      RECT 0.4130 -0.0270 0.4270 0.0070 ;
      RECT 0.4130 -0.0470 0.4270 -0.0130 ;
      RECT 0.4130 -0.0670 0.4270 -0.0330 ;
      RECT -0.0070 0.0130 0.0070 0.0470 ;
      RECT -0.0070 -0.0070 0.0070 0.0270 ;
      RECT -0.0070 -0.0270 0.0070 0.0070 ;
      RECT -0.0070 -0.0470 0.0070 -0.0130 ;
      RECT -0.0070 -0.0670 0.0070 -0.0330 ;
      RECT 0.1190 0.0330 0.1330 0.0670 ;
      RECT 0.1190 -0.0670 0.1330 -0.0330 ;
      RECT 0.1190 -0.0870 0.1330 -0.0530 ;
      RECT 0.2450 0.0330 0.2590 0.0670 ;
      RECT 0.2450 -0.0670 0.2590 -0.0330 ;
      RECT 0.2870 0.0130 0.3010 0.0470 ;
      RECT 0.2870 -0.0070 0.3010 0.0270 ;
      RECT 0.2870 -0.0270 0.3010 0.0070 ;
      RECT 0.2870 -0.0470 0.3010 -0.0130 ;
      RECT 0.2870 -0.0670 0.3010 -0.0330 ;
      RECT 0.3290 0.0330 0.3430 0.0670 ;
      RECT 0.3290 -0.0070 0.3430 0.0270 ;
      RECT 0.3290 -0.0270 0.3430 0.0070 ;
      RECT 0.0350 0.0530 0.0490 0.0870 ;
      RECT 0.0350 0.0330 0.0490 0.0670 ;
      RECT 0.0350 0.0130 0.0490 0.0470 ;
      RECT 0.0350 -0.0270 0.0490 0.0070 ;
      RECT 0.0350 -0.0470 0.0490 -0.0130 ;
      RECT 0.4130 -0.0270 0.4270 0.0070 ;
      RECT 0.4130 -0.0470 0.4270 -0.0130 ;
      RECT 0.4130 -0.0670 0.4270 -0.0330 ;
      RECT -0.0070 0.0130 0.0070 0.0470 ;
      RECT -0.0070 -0.0070 0.0070 0.0270 ;
      RECT -0.0070 -0.0270 0.0070 0.0070 ;
      RECT -0.0070 -0.0470 0.0070 -0.0130 ;
      RECT -0.0070 -0.0670 0.0070 -0.0330 ;
      RECT 0.1190 0.0330 0.1330 0.0670 ;
      RECT 0.1190 -0.0670 0.1330 -0.0330 ;
      RECT 0.1190 -0.0870 0.1330 -0.0530 ;
      RECT 0.2450 0.0330 0.2590 0.0670 ;
      RECT 0.2450 -0.0670 0.2590 -0.0330 ;
      RECT 0.2870 0.0130 0.3010 0.0470 ;
      RECT 0.2870 -0.0070 0.3010 0.0270 ;
      RECT 0.2870 -0.0270 0.3010 0.0070 ;
      RECT 0.2870 -0.0470 0.3010 -0.0130 ;
      RECT 0.2870 -0.0670 0.3010 -0.0330 ;
      RECT 0.3290 0.0330 0.3430 0.0670 ;
      RECT 0.3290 -0.0070 0.3430 0.0270 ;
      RECT 0.3290 -0.0270 0.3430 0.0070 ;
      RECT 0.0770 -0.0470 0.0910 -0.0130 ;
    LAYER M0 ;
      RECT 0.0580 -0.0460 0.0890 -0.0360 ;
      RECT 0.0790 0.0150 0.1100 0.0250 ;
      RECT 0.1000 0.0150 0.1310 0.0250 ;
      RECT 0.1210 0.0150 0.1520 0.0250 ;
      RECT 0.1420 0.0150 0.1730 0.0250 ;
      RECT 0.1630 0.0150 0.1940 0.0250 ;
      RECT 0.1840 0.0150 0.2150 0.0250 ;
      RECT 0.2050 0.0150 0.2360 0.0250 ;
      RECT 0.2260 0.0150 0.2570 0.0250 ;
      RECT 0.2470 0.0150 0.2780 0.0250 ;
      RECT 0.2680 0.0150 0.2990 0.0250 ;
      RECT 0.2890 0.0150 0.3200 0.0250 ;
      RECT 0.3100 0.0150 0.3410 0.0250 ;
      RECT 0.3310 0.0150 0.3620 0.0250 ;
      RECT 0.3520 0.0150 0.3830 0.0250 ;
      RECT -0.0050 -0.0250 0.0260 -0.0150 ;
      RECT 0.0160 -0.0250 0.0470 -0.0150 ;
      RECT 0.0370 -0.0250 0.0680 -0.0150 ;
      RECT 0.0580 -0.0250 0.0890 -0.0150 ;
      RECT 0.3730 -0.0250 0.4040 -0.0150 ;
      RECT 0.0370 0.0750 0.0680 0.0850 ;
      RECT 0.0580 0.0750 0.0890 0.0850 ;
      RECT 0.0790 0.0750 0.1100 0.0850 ;
      RECT 0.1000 0.0750 0.1310 0.0850 ;
      RECT 0.1210 0.0750 0.1520 0.0850 ;
      RECT 0.1420 0.0750 0.1730 0.0850 ;
      RECT 0.1630 0.0750 0.1940 0.0850 ;
      RECT 0.1840 0.0750 0.2150 0.0850 ;
      RECT 0.2050 0.0750 0.2360 0.0850 ;
      RECT 0.2260 0.0750 0.2570 0.0850 ;
      RECT 0.2470 0.0750 0.2780 0.0850 ;
      RECT 0.2680 0.0750 0.2990 0.0850 ;
      RECT 0.2890 0.0750 0.3200 0.0850 ;
      RECT 0.3100 0.0350 0.3410 0.0450 ;
      RECT 0.3310 0.0350 0.3620 0.0450 ;
      RECT 0.3520 0.0350 0.3830 0.0450 ;
      RECT 0.3730 0.0350 0.4040 0.0450 ;
      RECT 0.3940 0.0350 0.4250 0.0450 ;
      RECT 0.0160 -0.0450 0.0470 -0.0350 ;
      RECT 0.2890 -0.0450 0.3200 -0.0350 ;
      RECT 0.3100 -0.0450 0.3410 -0.0350 ;
      RECT 0.3310 -0.0450 0.3620 -0.0350 ;
      RECT 0.3520 -0.0450 0.3830 -0.0350 ;
      RECT 0.3730 -0.0650 0.4040 -0.0550 ;
      RECT 0.3940 -0.0650 0.4250 -0.0550 ;
      RECT -0.0050 0.0350 0.0260 0.0450 ;
      RECT 0.0160 0.0350 0.0470 0.0450 ;
      RECT 0.0370 0.0350 0.0680 0.0450 ;
      RECT 0.0580 0.0350 0.0890 0.0450 ;
      RECT 0.0790 0.0350 0.1100 0.0450 ;
      RECT 0.1000 0.0350 0.1310 0.0450 ;
      RECT -0.0050 -0.0650 0.0260 -0.0550 ;
      RECT 0.0160 -0.0650 0.0470 -0.0550 ;
      RECT 0.0370 -0.0650 0.0680 -0.0550 ;
      RECT 0.0580 -0.0650 0.0890 -0.0550 ;
      RECT 0.0790 -0.0650 0.1100 -0.0550 ;
      RECT 0.1000 -0.0650 0.1310 -0.0550 ;
      RECT 0.1210 -0.0850 0.1520 -0.0750 ;
      RECT 0.1420 -0.0850 0.1730 -0.0750 ;
      RECT 0.1630 -0.0850 0.1940 -0.0750 ;
      RECT 0.1840 -0.0850 0.2150 -0.0750 ;
      RECT 0.2050 -0.0850 0.2360 -0.0750 ;
      RECT 0.2260 -0.0850 0.2570 -0.0750 ;
      RECT 0.2470 -0.0850 0.2780 -0.0750 ;
      RECT 0.1840 0.0550 0.2150 0.0650 ;
      RECT 0.2050 0.0550 0.2360 0.0650 ;
      RECT 0.2260 0.0550 0.2570 0.0650 ;
      RECT 0.2470 0.0350 0.2780 0.0450 ;
      RECT 0.2680 0.0350 0.2990 0.0450 ;
      RECT 0.2470 -0.0650 0.2780 -0.0550 ;
      RECT 0.2680 -0.0650 0.2990 -0.0550 ;
      RECT 0.2890 -0.0850 0.3200 -0.0750 ;
      RECT 0.3100 -0.0850 0.3410 -0.0750 ;
      RECT 0.3310 -0.0850 0.3620 -0.0750 ;
      RECT 0.3520 -0.0850 0.3830 -0.0750 ;
      RECT -0.0050 -0.0850 0.0260 -0.0750 ;
      RECT 0.0160 -0.0850 0.0470 -0.0750 ;
      RECT 0.0370 -0.0850 0.0680 -0.0750 ;
      RECT 0.0580 -0.0850 0.0890 -0.0750 ;
      RECT 0.2680 0.0550 0.2990 0.0650 ;
      RECT 0.2890 0.0550 0.3200 0.0650 ;
      RECT 0.3100 0.0550 0.3410 0.0650 ;
      RECT 0.1000 -0.0250 0.1310 -0.0150 ;
      RECT 0.1210 -0.0250 0.1520 -0.0150 ;
      RECT 0.1420 -0.0250 0.1730 -0.0150 ;
      RECT 0.1630 -0.0250 0.1940 -0.0150 ;
      RECT 0.1840 -0.0250 0.2150 -0.0150 ;
      RECT 0.2050 -0.0250 0.2360 -0.0150 ;
      RECT 0.2260 -0.0250 0.2570 -0.0150 ;
      RECT 0.2470 -0.0250 0.2780 -0.0150 ;
      RECT 0.2680 -0.0250 0.2990 -0.0150 ;
      RECT 0.2890 -0.0250 0.3200 -0.0150 ;
      RECT 0.3100 -0.0250 0.3410 -0.0150 ;
      RECT 0.2050 -0.0450 0.2150 -0.0350 ;
      RECT 0.2050 -0.0650 0.2150 -0.0550 ;
      RECT 0.1210 0.0550 0.1310 0.0650 ;
      RECT 0.1210 -0.0450 0.1310 -0.0350 ;
      RECT 0.2470 -0.0450 0.2570 -0.0350 ;
      RECT 0.1630 0.0550 0.1730 0.0650 ;
      RECT 0.1630 0.0350 0.1730 0.0450 ;
      RECT 0.1210 0.0750 0.1520 0.0850 ;
      RECT 0.1420 0.0750 0.1730 0.0850 ;
      RECT 0.1630 0.0750 0.1940 0.0850 ;
      RECT 0.1840 0.0750 0.2150 0.0850 ;
      RECT 0.2050 0.0750 0.2360 0.0850 ;
      RECT 0.2260 0.0750 0.2570 0.0850 ;
      RECT 0.2470 0.0750 0.2780 0.0850 ;
      RECT 0.2680 0.0750 0.2990 0.0850 ;
      RECT 0.2890 0.0750 0.3200 0.0850 ;
      RECT 0.3100 0.0350 0.3410 0.0450 ;
      RECT 0.3310 0.0350 0.3620 0.0450 ;
      RECT 0.3520 0.0350 0.3830 0.0450 ;
      RECT 0.3730 0.0350 0.4040 0.0450 ;
      RECT 0.3940 0.0350 0.4250 0.0450 ;
      RECT -0.0050 0.0350 0.0260 0.0450 ;
      RECT 0.0160 0.0350 0.0470 0.0450 ;
      RECT 0.0370 0.0350 0.0680 0.0450 ;
      RECT 0.0580 0.0350 0.0890 0.0450 ;
      RECT 0.0790 0.0350 0.1100 0.0450 ;
      RECT 0.1000 0.0350 0.1310 0.0450 ;
      RECT 0.1840 0.0550 0.2150 0.0650 ;
      RECT 0.2050 0.0550 0.2360 0.0650 ;
      RECT 0.2260 0.0550 0.2570 0.0650 ;
      RECT 0.2470 0.0350 0.2780 0.0450 ;
      RECT 0.2680 0.0350 0.2990 0.0450 ;
      RECT 0.2680 0.0550 0.2990 0.0650 ;
      RECT 0.2890 0.0550 0.3200 0.0650 ;
      RECT 0.3100 0.0550 0.3410 0.0650 ;
      RECT 0.1210 0.0550 0.1310 0.0650 ;
      RECT 0.1630 0.0550 0.1730 0.0650 ;
      RECT 0.1630 0.0350 0.1730 0.0450 ;
      RECT 0.1000 0.0750 0.1310 0.0850 ;
      RECT 0.0790 0.0750 0.1100 0.0850 ;
      RECT 0.0580 0.0750 0.0890 0.0850 ;
      RECT 0.1420 -0.0850 0.1730 -0.0750 ;
      RECT 0.1630 -0.0850 0.1940 -0.0750 ;
      RECT 0.1840 -0.0850 0.2150 -0.0750 ;
      RECT 0.2050 -0.0850 0.2360 -0.0750 ;
      RECT 0.2260 -0.0850 0.2570 -0.0750 ;
      RECT 0.2470 -0.0850 0.2780 -0.0750 ;
      RECT 0.2470 -0.0650 0.2780 -0.0550 ;
      RECT 0.2680 -0.0650 0.2990 -0.0550 ;
      RECT 0.2890 -0.0850 0.3200 -0.0750 ;
      RECT 0.3100 -0.0850 0.3410 -0.0750 ;
      RECT 0.3310 -0.0850 0.3620 -0.0750 ;
      RECT 0.3520 -0.0850 0.3830 -0.0750 ;
      RECT -0.0050 -0.0850 0.0260 -0.0750 ;
      RECT 0.0160 -0.0850 0.0470 -0.0750 ;
      RECT 0.0370 -0.0850 0.0680 -0.0750 ;
      RECT 0.0580 -0.0850 0.0890 -0.0750 ;
      RECT 0.1000 -0.0250 0.1310 -0.0150 ;
      RECT 0.1210 -0.0250 0.1520 -0.0150 ;
      RECT 0.1420 -0.0250 0.1730 -0.0150 ;
      RECT 0.1630 -0.0250 0.1940 -0.0150 ;
      RECT 0.1840 -0.0250 0.2150 -0.0150 ;
      RECT 0.2050 -0.0250 0.2360 -0.0150 ;
      RECT 0.2260 -0.0250 0.2570 -0.0150 ;
      RECT 0.2470 -0.0250 0.2780 -0.0150 ;
      RECT 0.2680 -0.0250 0.2990 -0.0150 ;
      RECT 0.2890 -0.0250 0.3200 -0.0150 ;
      RECT 0.3100 -0.0250 0.3410 -0.0150 ;
      RECT 0.2050 -0.0450 0.2150 -0.0350 ;
      RECT 0.2050 -0.0650 0.2150 -0.0550 ;
      RECT 0.1210 -0.0450 0.1310 -0.0350 ;
      RECT 0.2470 -0.0450 0.2570 -0.0350 ;
      RECT 0.1210 -0.0850 0.1520 -0.0750 ;
      RECT 0.1000 -0.0650 0.1310 -0.0550 ;
      RECT 0.0790 -0.0650 0.1100 -0.0550 ;
      RECT 0.0580 -0.0650 0.0890 -0.0550 ;
      RECT 0.0370 -0.0650 0.0680 -0.0550 ;
      RECT 0.0160 -0.0650 0.0470 -0.0550 ;
      RECT 0.1210 0.0150 0.1520 0.0250 ;
      RECT 0.1000 0.0150 0.1310 0.0250 ;
      RECT 0.0790 0.0150 0.1100 0.0250 ;
      RECT -0.0050 -0.0650 0.0260 -0.0550 ;
      RECT 0.1420 0.0150 0.1730 0.0250 ;
      RECT 0.1630 0.0150 0.1940 0.0250 ;
      RECT 0.1840 0.0150 0.2150 0.0250 ;
      RECT 0.2050 0.0150 0.2360 0.0250 ;
      RECT 0.2260 0.0150 0.2570 0.0250 ;
      RECT 0.2470 0.0150 0.2780 0.0250 ;
      RECT 0.3940 -0.0650 0.4250 -0.0550 ;
      RECT 0.3730 -0.0650 0.4040 -0.0550 ;
      RECT 0.3520 -0.0650 0.3830 -0.0550 ;
      RECT 0.3310 -0.0450 0.3620 -0.0350 ;
      RECT 0.3100 -0.0450 0.3410 -0.0350 ;
      RECT 0.2890 -0.0450 0.3200 -0.0350 ;
      RECT 0.0160 -0.0450 0.0470 -0.0350 ;
      RECT 0.2680 0.0150 0.2990 0.0250 ;
      RECT 0.2890 0.0150 0.3200 0.0250 ;
      RECT 0.3100 0.0150 0.3410 0.0250 ;
      RECT 0.3310 0.0150 0.3620 0.0250 ;
      RECT 0.3520 0.0150 0.3830 0.0250 ;
      RECT -0.0050 -0.0250 0.0260 -0.0150 ;
      RECT 0.0160 -0.0250 0.0470 -0.0150 ;
      RECT 0.0370 -0.0250 0.0680 -0.0150 ;
      RECT 0.0580 -0.0250 0.0890 -0.0150 ;
      RECT 0.3730 -0.0250 0.4040 -0.0150 ;
      RECT 0.0370 0.0750 0.0680 0.0850 ;
  END
END FA_X1

MACRO HA_X1
  CLASS CORE ;
  FOREIGN HA_X1 0 0 ;
  ORIGIN -0.0210 -0.1000 ;
  SIZE 0.2520 BY 0.2000 ;
  SITE NSFET ;
  SYMMETRY X Y ;
  PIN A
    DIRECTION INPUT ;
    USE SIGNAL ;
    PORT
      LAYER M1 ;
        RECT 0.1610 -0.0270 0.1750 0.0070 ;
        RECT 0.1610 -0.0070 0.1750 0.0270 ;
        RECT 0.0770 -0.0270 0.0910 0.0070 ;
        RECT 0.0770 -0.0070 0.0910 0.0270 ;
    END
  END A
  PIN B
    DIRECTION INPUT ;
    USE SIGNAL ;
    PORT
      LAYER M1 ;
        RECT 0.0350 -0.0270 0.0490 0.0070 ;
        RECT 0.0350 -0.0070 0.0490 0.0270 ;
    END
  END B
  PIN CO
    DIRECTION OUTPUT ;
    USE SIGNAL ;
    PORT
      LAYER M1 ;
        RECT 0.1610 0.0330 0.1750 0.0670 ;
    END
  END CO
  PIN S
    DIRECTION OUTPUT ;
    USE SIGNAL ;
    PORT
      LAYER M1 ;
        RECT 0.0770 0.0330 0.0910 0.0670 ;
    END
  END S
  PIN VSS
    DIRECTION INOUT ;
    USE GROUND ;
    PORT
      LAYER M0 ;
        RECT -0.0370 -0.0050 0.2470 0.0050 ;
    END
  END VSS
  PIN VDD
    DIRECTION INOUT ;
    USE POWER ;
    PORT
      LAYER M0 ;
        RECT -0.0370 -0.1050 0.2470 -0.0950 ;
    END
  END VDD
  PIN VDD
    DIRECTION INOUT ;
    USE POWER ;
    PORT
      LAYER M0 ;
        RECT -0.0370 0.0950 0.2470 0.1050 ;
    END
  END VDD
  OBS
    LAYER M1 ;
      RECT 0.0770 -0.0670 0.0910 -0.0330 ;
      RECT 0.0770 -0.0470 0.0910 -0.0130 ;
      RECT 0.2030 -0.0670 0.2170 -0.0330 ;
      RECT 0.2030 -0.0470 0.2170 -0.0130 ;
      RECT 0.2030 -0.0270 0.2170 0.0070 ;
      RECT 0.2030 -0.0070 0.2170 0.0270 ;
      RECT -0.0070 -0.0670 0.0070 -0.0330 ;
      RECT -0.0070 -0.0470 0.0070 -0.0130 ;
      RECT -0.0070 -0.0270 0.0070 0.0070 ;
      RECT -0.0070 -0.0070 0.0070 0.0270 ;
    LAYER M0 ;
      RECT 0.0790 0.0550 0.0890 0.0650 ;
      RECT 0.2050 -0.0450 0.2150 -0.0350 ;
      RECT 0.2050 -0.0250 0.2150 -0.0150 ;
      RECT -0.0050 -0.0650 0.0050 -0.0550 ;
      RECT -0.0050 -0.0250 0.0050 -0.0150 ;
      RECT 0.1630 0.0350 0.1730 0.0450 ;
      RECT 0.1630 0.0550 0.1730 0.0650 ;
      RECT 0.0580 -0.0650 0.0890 -0.0550 ;
      RECT 0.1630 -0.0250 0.1940 -0.0150 ;
      RECT 0.1420 0.0150 0.1730 0.0250 ;
      RECT 0.1210 0.0150 0.1520 0.0250 ;
      RECT 0.1000 0.0150 0.1310 0.0250 ;
      RECT 0.0790 0.0150 0.1100 0.0250 ;
      RECT 0.1210 -0.0250 0.1520 -0.0150 ;
      RECT 0.1000 -0.0250 0.1310 -0.0150 ;
      RECT 0.0790 -0.0250 0.1100 -0.0150 ;
      RECT 0.0580 -0.0250 0.0890 -0.0150 ;
      RECT 0.0370 -0.0250 0.0680 -0.0150 ;
      RECT 0.0160 -0.0250 0.0470 -0.0150 ;
      RECT 0.0370 0.0150 0.0680 0.0250 ;
      RECT 0.1000 0.0350 0.1310 0.0450 ;
      RECT 0.0790 0.0350 0.1100 0.0450 ;
      RECT 0.0580 0.0350 0.0890 0.0450 ;
      RECT 0.0370 0.0350 0.0680 0.0450 ;
      RECT 0.0160 0.0350 0.0470 0.0450 ;
      RECT -0.0050 0.0350 0.0260 0.0450 ;
      RECT 0.1840 -0.0650 0.2150 -0.0550 ;
      RECT 0.1630 -0.0650 0.1940 -0.0550 ;
      RECT 0.1420 -0.0650 0.1730 -0.0550 ;
      RECT 0.1210 -0.0650 0.1520 -0.0550 ;
      RECT 0.1840 0.0150 0.2150 0.0250 ;
      RECT 0.0580 -0.0450 0.0890 -0.0350 ;
      RECT 0.0370 -0.0450 0.0680 -0.0350 ;
      RECT 0.0160 -0.0450 0.0470 -0.0350 ;
      RECT -0.0050 -0.0450 0.0260 -0.0350 ;
      RECT -0.0050 0.0150 0.0260 0.0250 ;
      RECT 0.1000 0.0750 0.1310 0.0850 ;
      RECT 0.0790 0.0750 0.1100 0.0850 ;
      RECT 0.0580 0.0750 0.0890 0.0850 ;
      RECT 0.0370 0.0750 0.0680 0.0850 ;
  END
END HA_X1

MACRO INV_X1
  CLASS CORE ;
  FOREIGN INV_X1 0 0 ;
  ORIGIN -0.0210 0.0000 ;
  SIZE 0.0840 BY 0.1000 ;
  SITE NSFET ;
  SYMMETRY X Y ;
  PIN ZN
    DIRECTION OUTPUT ;
    USE SIGNAL ;
    PORT
      LAYER M1 ;
        RECT 0.0350 0.0330 0.0490 0.0670 ;
    END
  END ZN
  PIN A
    DIRECTION INPUT ;
    USE SIGNAL ;
    PORT
      LAYER M1 ;
        RECT -0.0070 0.0330 0.0070 0.0670 ;
    END
  END A
  PIN VDD
    DIRECTION INOUT ;
    USE POWER ;
    PORT
      LAYER M0 ;
        RECT -0.0370 0.0950 0.0790 0.1050 ;
    END
  END VDD
  PIN VSS
    DIRECTION INOUT ;
    USE GROUND ;
    PORT
      LAYER M0 ;
        RECT -0.0370 -0.0050 0.0790 0.0050 ;
    END
  END VSS
  OBS
    LAYER M0 ;
      RECT 0.0370 0.0550 0.0470 0.0650 ;
      RECT 0.0370 0.0350 0.0470 0.0450 ;
      RECT -0.0060 0.0550 0.0270 0.0650 ;
  END
END INV_X1

MACRO INV_X16
  CLASS CORE ;
  FOREIGN INV_X16 0 0 ;
  ORIGIN -0.0210 0.0000 ;
  SIZE 0.7560 BY 0.1000 ;
  SITE NSFET ;
  SYMMETRY X Y ;
  PIN A
    DIRECTION INPUT ;
    USE SIGNAL ;
    PORT
      LAYER M1 ;
        RECT -0.0070 0.0310 0.0070 0.0650 ;
    END
  END A
  PIN ZN
    DIRECTION OUTPUT ;
    USE SIGNAL ;
    PORT
      LAYER M1 ;
        RECT 0.0350 0.0330 0.0490 0.0670 ;
        RECT 0.0770 0.0330 0.0910 0.0670 ;
        RECT 0.1610 0.0330 0.1750 0.0670 ;
        RECT 0.2450 0.0330 0.2590 0.0670 ;
        RECT 0.3290 0.0330 0.3430 0.0670 ;
        RECT 0.4130 0.0330 0.4270 0.0670 ;
        RECT 0.4970 0.0330 0.5110 0.0670 ;
        RECT 0.5810 0.0330 0.5950 0.0670 ;
        RECT 0.6650 0.0330 0.6790 0.0670 ;
    END
  END ZN
  PIN VSS
    DIRECTION INOUT ;
    USE GROUND ;
    PORT
      LAYER M0 ;
        RECT -0.0370 -0.0050 0.7510 0.0050 ;
    END
  END VSS
  PIN VDD
    DIRECTION INOUT ;
    USE POWER ;
    PORT
      LAYER M0 ;
        RECT -0.0370 0.0950 0.7510 0.1050 ;
    END
  END VDD
  OBS
    LAYER M0 ;
      RECT -0.0050 0.0550 0.0260 0.0650 ;
      RECT 0.0160 0.0550 0.0470 0.0650 ;
      RECT 0.2470 0.0550 0.2780 0.0650 ;
      RECT 0.2680 0.0550 0.2990 0.0650 ;
      RECT 0.2890 0.0550 0.3200 0.0650 ;
      RECT 0.3100 0.0550 0.3410 0.0650 ;
      RECT 0.4150 0.0550 0.4460 0.0650 ;
      RECT 0.4360 0.0550 0.4670 0.0650 ;
      RECT 0.4570 0.0550 0.4880 0.0650 ;
      RECT 0.4780 0.0550 0.5090 0.0650 ;
      RECT 0.5830 0.0550 0.6140 0.0650 ;
      RECT 0.6040 0.0550 0.6350 0.0650 ;
      RECT 0.6250 0.0550 0.6560 0.0650 ;
      RECT 0.6460 0.0550 0.6770 0.0650 ;
      RECT 0.0370 0.0350 0.0680 0.0450 ;
      RECT 0.0580 0.0350 0.0890 0.0450 ;
      RECT 0.0790 0.0350 0.1100 0.0450 ;
      RECT 0.1000 0.0350 0.1310 0.0450 ;
      RECT 0.1210 0.0350 0.1520 0.0450 ;
      RECT 0.1420 0.0350 0.1730 0.0450 ;
      RECT 0.1630 0.0350 0.1940 0.0450 ;
      RECT 0.1840 0.0350 0.2150 0.0450 ;
      RECT 0.2050 0.0350 0.2360 0.0450 ;
      RECT 0.2260 0.0350 0.2570 0.0450 ;
      RECT 0.3310 0.0350 0.3620 0.0450 ;
      RECT 0.3520 0.0350 0.3830 0.0450 ;
      RECT 0.3730 0.0350 0.4040 0.0450 ;
      RECT 0.3940 0.0350 0.4250 0.0450 ;
      RECT 0.4990 0.0350 0.5300 0.0450 ;
      RECT 0.5200 0.0350 0.5510 0.0450 ;
      RECT 0.5410 0.0350 0.5720 0.0450 ;
      RECT 0.5620 0.0350 0.5930 0.0450 ;
      RECT 0.0160 0.0750 0.0470 0.0850 ;
      RECT 0.0370 0.0750 0.0680 0.0850 ;
      RECT 0.0580 0.0750 0.0890 0.0850 ;
      RECT 0.0790 0.0750 0.1100 0.0850 ;
      RECT 0.1000 0.0750 0.1310 0.0850 ;
      RECT 0.1210 0.0750 0.1520 0.0850 ;
      RECT 0.1420 0.0750 0.1730 0.0850 ;
      RECT 0.1630 0.0750 0.1940 0.0850 ;
      RECT 0.1840 0.0750 0.2150 0.0850 ;
      RECT 0.2050 0.0750 0.2360 0.0850 ;
      RECT 0.2260 0.0750 0.2570 0.0850 ;
      RECT 0.2470 0.0750 0.2780 0.0850 ;
      RECT 0.2680 0.0750 0.2990 0.0850 ;
      RECT 0.2890 0.0750 0.3200 0.0850 ;
      RECT 0.3100 0.0750 0.3410 0.0850 ;
      RECT 0.3310 0.0750 0.3620 0.0850 ;
      RECT 0.3520 0.0750 0.3830 0.0850 ;
      RECT 0.3730 0.0750 0.4040 0.0850 ;
      RECT 0.3940 0.0750 0.4250 0.0850 ;
      RECT 0.4150 0.0750 0.4460 0.0850 ;
      RECT 0.4360 0.0750 0.4670 0.0850 ;
      RECT 0.4570 0.0750 0.4880 0.0850 ;
      RECT 0.4780 0.0750 0.5090 0.0850 ;
      RECT 0.4990 0.0750 0.5300 0.0850 ;
      RECT 0.5200 0.0750 0.5510 0.0850 ;
      RECT 0.5410 0.0750 0.5720 0.0850 ;
      RECT 0.5620 0.0750 0.5930 0.0850 ;
      RECT 0.5830 0.0750 0.6140 0.0850 ;
      RECT 0.6040 0.0750 0.6350 0.0850 ;
      RECT 0.6250 0.0750 0.6560 0.0850 ;
      RECT 0.6460 0.0750 0.6770 0.0850 ;
      RECT 0.6670 0.0750 0.6980 0.0850 ;
      RECT 0.0790 0.0550 0.0890 0.0650 ;
      RECT 0.1630 0.0550 0.1730 0.0650 ;
      RECT 0.6670 0.0350 0.6770 0.0450 ;
      RECT -0.0060 0.0330 0.0270 0.0430 ;
  END
END INV_X16

MACRO INV_X2
  CLASS CORE ;
  FOREIGN INV_X2 0 0 ;
  ORIGIN -0.0210 0.0000 ;
  SIZE 0.1260 BY 0.1000 ;
  SITE NSFET ;
  SYMMETRY X Y ;
  PIN A
    DIRECTION INPUT ;
    USE SIGNAL ;
    PORT
      LAYER M1 ;
        RECT -0.0070 0.0580 0.0070 0.0750 ;
    END
  END A
  PIN ZN
    DIRECTION OUTPUT ;
    USE SIGNAL ;
    PORT
      LAYER M1 ;
        RECT 0.0350 0.0330 0.0490 0.0670 ;
    END
  END ZN
  PIN VSS
    DIRECTION INOUT ;
    USE GROUND ;
    PORT
      LAYER M0 ;
        RECT -0.0370 -0.0050 0.1210 0.0050 ;
    END
  END VSS
  PIN VDD
    DIRECTION INOUT ;
    USE POWER ;
    PORT
      LAYER M0 ;
        RECT -0.0370 0.0950 0.1210 0.1050 ;
    END
  END VDD
  OBS
    LAYER M0 ;
      RECT 0.0160 0.0150 0.0470 0.0250 ;
      RECT 0.0370 0.0150 0.0680 0.0250 ;
      RECT 0.0370 0.0550 0.0470 0.0650 ;
      RECT 0.0370 0.0350 0.0470 0.0450 ;
      RECT -0.0050 0.0620 0.0270 0.0720 ;
  END
END INV_X2

MACRO INV_X32
  CLASS CORE ;
  FOREIGN INV_X32 0 0 ;
  ORIGIN 0.0270 0.0550 ;
  SIZE 1.3860 BY 0.1000 ;
  SITE NSFET ;
  SYMMETRY X Y ;
  PIN A
    DIRECTION INPUT ;
    USE SIGNAL ;
    PORT
      LAYER M1 ;
        RECT 0.0830 0.0680 0.0970 0.1420 ;
    END
  END A
  PIN ZN
    DIRECTION OUTPUT ;
    USE SIGNAL ;
    PORT
      LAYER M1 ;
        RECT 0.1250 0.0680 0.1390 0.1420 ;
    END
  END ZN
  PIN VSS
    DIRECTION INOUT ;
    USE GROUND ;
    PORT
      LAYER M0 ;
        RECT 0.0110 0.0500 1.4290 0.0600 ;
    END
  END VSS
  PIN VDD
    DIRECTION INOUT ;
    USE POWER ;
    PORT
      LAYER M0 ;
        RECT 0.0110 0.1500 1.4290 0.1600 ;
    END
  END VDD
  OBS
    LAYER M1 ;
      RECT 0.0410 0.0680 0.0550 0.1420 ;
    LAYER M0 ;
      RECT 0.0360 0.0700 1.3970 0.0800 ;
      RECT 0.0430 0.1100 1.3970 0.1200 ;
      RECT 0.0430 0.1300 1.3970 0.1400 ;
      RECT 0.0360 0.0900 1.3970 0.1000 ;
  END
END INV_X32

MACRO INV_X4
  CLASS CORE ;
  FOREIGN INV_X4 0 0 ;
  ORIGIN -0.0210 0.0000 ;
  SIZE 0.2100 BY 0.1000 ;
  SITE NSFET ;
  SYMMETRY X Y ;
  PIN ZN
    DIRECTION OUTPUT ;
    USE SIGNAL ;
    PORT
      LAYER M1 ;
        RECT 0.0350 0.0330 0.0490 0.0670 ;
        RECT 0.1190 0.0330 0.1330 0.0670 ;
    END
  END ZN
  PIN A
    DIRECTION INPUT ;
    USE SIGNAL ;
    PORT
      LAYER M1 ;
        RECT -0.0070 0.0400 0.0070 0.0740 ;
    END
  END A
  PIN VDD
    DIRECTION INOUT ;
    USE POWER ;
    PORT
      LAYER M0 ;
        RECT -0.0370 0.0950 0.2050 0.1050 ;
    END
  END VDD
  PIN VSS
    DIRECTION INOUT ;
    USE GROUND ;
    PORT
      LAYER M0 ;
        RECT -0.0370 -0.0050 0.2050 0.0050 ;
    END
  END VSS
  OBS
    LAYER M0 ;
      RECT 0.0370 0.0550 0.0680 0.0650 ;
      RECT 0.0580 0.0550 0.0890 0.0650 ;
      RECT 0.0790 0.0550 0.1100 0.0650 ;
      RECT 0.1000 0.0550 0.1310 0.0650 ;
      RECT 0.0160 0.0150 0.0470 0.0250 ;
      RECT 0.0370 0.0150 0.0680 0.0250 ;
      RECT 0.0580 0.0150 0.0890 0.0250 ;
      RECT 0.0790 0.0150 0.1100 0.0250 ;
      RECT 0.1000 0.0150 0.1310 0.0250 ;
      RECT 0.1210 0.0150 0.1520 0.0250 ;
      RECT 0.0370 0.0350 0.0470 0.0450 ;
      RECT 0.1210 0.0350 0.1310 0.0450 ;
      RECT -0.0060 0.0620 0.0270 0.0720 ;
  END
END INV_X4

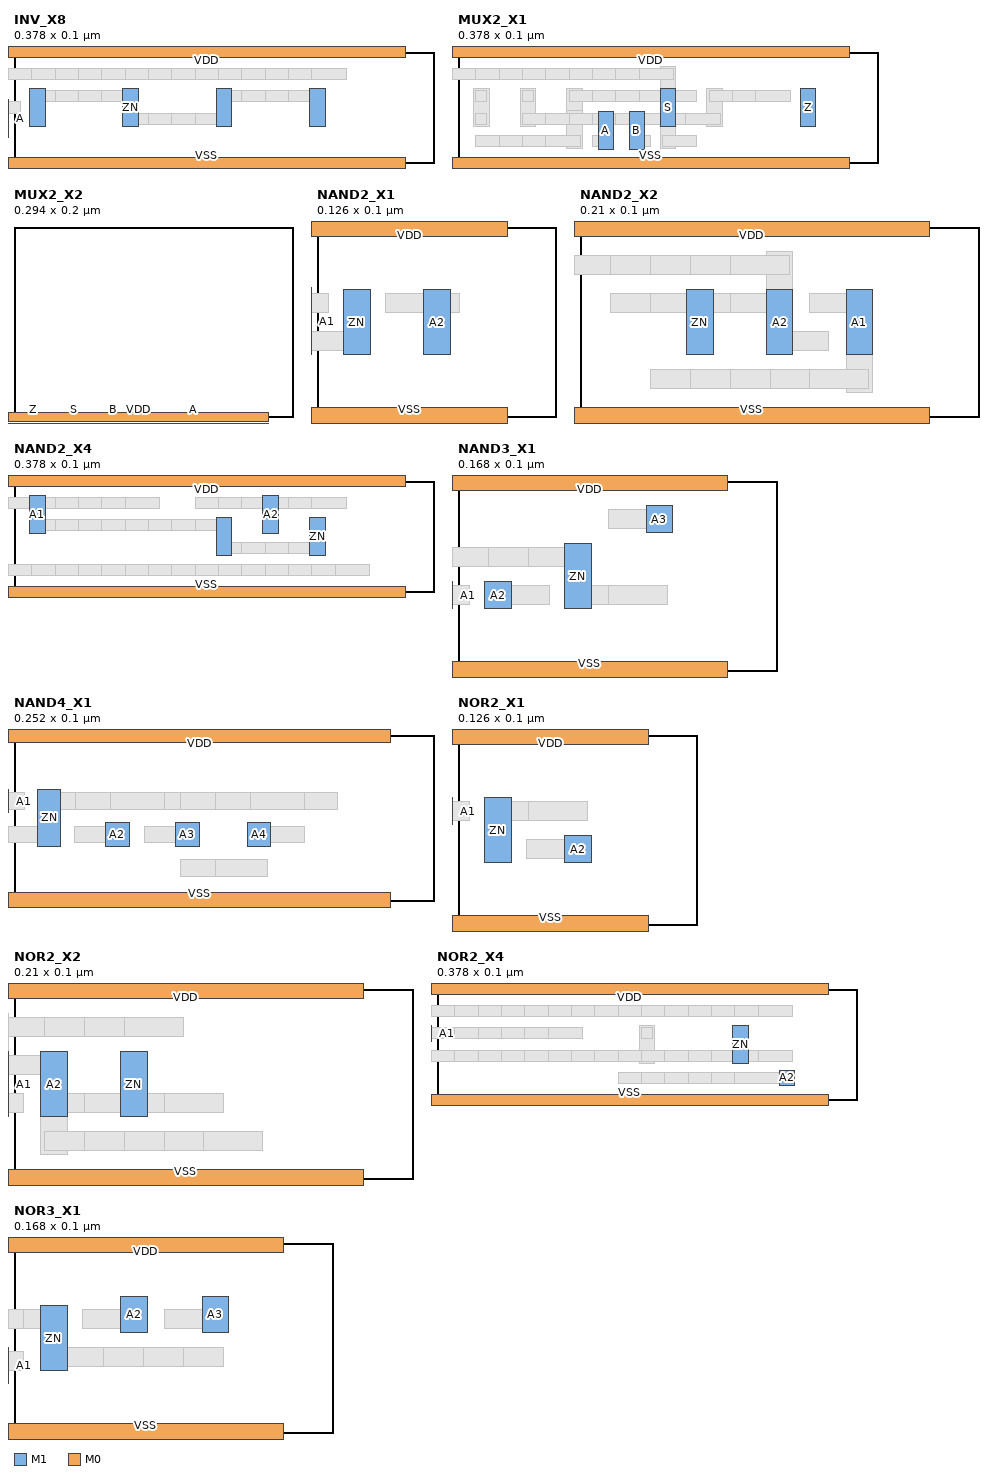
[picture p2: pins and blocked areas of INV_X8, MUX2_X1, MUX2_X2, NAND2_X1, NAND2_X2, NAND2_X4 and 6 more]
MACRO INV_X8
  CLASS CORE ;
  FOREIGN INV_X8 0 0 ;
  ORIGIN -0.0210 0.0000 ;
  SIZE 0.3780 BY 0.1000 ;
  SITE NSFET ;
  SYMMETRY X Y ;
  PIN A
    DIRECTION INPUT ;
    USE SIGNAL ;
    PORT
      LAYER M1 ;
        RECT -0.0070 0.0230 0.0070 0.0570 ;
    END
  END A
  PIN ZN
    DIRECTION OUTPUT ;
    USE SIGNAL ;
    PORT
      LAYER M1 ;
        RECT 0.0350 0.0330 0.0490 0.0670 ;
        RECT 0.1190 0.0330 0.1330 0.0670 ;
        RECT 0.2030 0.0330 0.2170 0.0670 ;
        RECT 0.2870 0.0330 0.3010 0.0670 ;
    END
  END ZN
  PIN VDD
    DIRECTION INOUT ;
    USE POWER ;
    PORT
      LAYER M0 ;
        RECT -0.0370 0.0950 0.3730 0.1050 ;
    END
  END VDD
  PIN VSS
    DIRECTION INOUT ;
    USE GROUND ;
    PORT
      LAYER M0 ;
        RECT -0.0370 -0.0050 0.3730 0.0050 ;
    END
  END VSS
  OBS
    LAYER M0 ;
      RECT -0.0060 0.0450 0.0270 0.0550 ;
      RECT 0.0370 0.0550 0.0680 0.0650 ;
      RECT 0.0580 0.0550 0.0890 0.0650 ;
      RECT 0.0790 0.0550 0.1100 0.0650 ;
      RECT 0.1000 0.0550 0.1310 0.0650 ;
      RECT 0.2050 0.0550 0.2360 0.0650 ;
      RECT 0.2260 0.0550 0.2570 0.0650 ;
      RECT 0.2470 0.0550 0.2780 0.0650 ;
      RECT 0.2680 0.0550 0.2990 0.0650 ;
      RECT 0.1210 0.0350 0.1520 0.0450 ;
      RECT 0.1420 0.0350 0.1730 0.0450 ;
      RECT 0.1630 0.0350 0.1940 0.0450 ;
      RECT 0.1840 0.0350 0.2150 0.0450 ;
      RECT 0.0160 0.0750 0.0470 0.0850 ;
      RECT 0.0370 0.0750 0.0680 0.0850 ;
      RECT 0.0580 0.0750 0.0890 0.0850 ;
      RECT 0.0790 0.0750 0.1100 0.0850 ;
      RECT 0.1000 0.0750 0.1310 0.0850 ;
      RECT 0.1210 0.0750 0.1520 0.0850 ;
      RECT 0.1420 0.0750 0.1730 0.0850 ;
      RECT 0.1630 0.0750 0.1940 0.0850 ;
      RECT 0.1840 0.0750 0.2150 0.0850 ;
      RECT 0.2050 0.0750 0.2360 0.0850 ;
      RECT 0.2260 0.0750 0.2570 0.0850 ;
      RECT 0.2470 0.0750 0.2780 0.0850 ;
      RECT 0.2680 0.0750 0.2990 0.0850 ;
      RECT 0.2890 0.0750 0.3200 0.0850 ;
      RECT 0.0370 0.0350 0.0470 0.0450 ;
      RECT 0.2890 0.0350 0.2990 0.0450 ;
  END
END INV_X8

MACRO MUX2_X1
  CLASS CORE ;
  FOREIGN MUX2_X1 0 0 ;
  ORIGIN -0.0210 0.0000 ;
  SIZE 0.3780 BY 0.1000 ;
  SITE NSFET ;
  SYMMETRY X Y ;
  PIN S
    DIRECTION INPUT ;
    USE SIGNAL ;
    PORT
      LAYER M1 ;
        RECT 0.2030 0.0330 0.2170 0.0670 ;
        RECT 0.2030 0.0330 0.2170 0.0670 ;
    END
  END S
  PIN Z
    DIRECTION OUTPUT ;
    USE SIGNAL ;
    PORT
      LAYER M1 ;
        RECT 0.3290 0.0330 0.3430 0.0670 ;
        RECT 0.3290 0.0330 0.3430 0.0670 ;
    END
  END Z
  PIN A
    DIRECTION INPUT ;
    USE SIGNAL ;
    PORT
      LAYER M1 ;
        RECT 0.1470 0.0120 0.1610 0.0460 ;
    END
  END A
  PIN B
    DIRECTION INPUT ;
    USE SIGNAL ;
    PORT
      LAYER M1 ;
        RECT 0.1750 0.0120 0.1890 0.0460 ;
    END
  END B
  PIN VDD
    DIRECTION INOUT ;
    USE POWER ;
    PORT
      LAYER M0 ;
        RECT -0.0370 0.0950 0.3730 0.1050 ;
    END
  END VDD
  PIN VSS
    DIRECTION INOUT ;
    USE GROUND ;
    PORT
      LAYER M0 ;
        RECT -0.0370 -0.0050 0.3730 0.0050 ;
    END
  END VSS
  OBS
    LAYER M1 ;
      RECT 0.0770 0.0330 0.0910 0.0670 ;
      RECT 0.2450 0.0330 0.2590 0.0670 ;
      RECT 0.0350 0.0330 0.0490 0.0670 ;
      RECT 0.1190 0.0330 0.1330 0.0670 ;
      RECT 0.1190 0.0130 0.1330 0.0470 ;
      RECT 0.2030 0.0530 0.2170 0.0870 ;
      RECT 0.2030 0.0130 0.2170 0.0470 ;
      RECT 0.0770 0.0330 0.0910 0.0670 ;
      RECT 0.2450 0.0330 0.2590 0.0670 ;
      RECT 0.0350 0.0330 0.0490 0.0670 ;
      RECT 0.1190 0.0330 0.1330 0.0670 ;
      RECT 0.1190 0.0130 0.1330 0.0470 ;
      RECT 0.2030 0.0530 0.2170 0.0870 ;
      RECT 0.2030 0.0130 0.2170 0.0470 ;
    LAYER M0 ;
      RECT 0.2470 0.0550 0.2780 0.0650 ;
      RECT 0.2680 0.0550 0.2990 0.0650 ;
      RECT 0.2890 0.0550 0.3200 0.0650 ;
      RECT 0.0790 0.0350 0.1100 0.0450 ;
      RECT 0.1000 0.0350 0.1310 0.0450 ;
      RECT 0.1210 0.0350 0.1520 0.0450 ;
      RECT 0.1420 0.0350 0.1730 0.0450 ;
      RECT 0.1630 0.0350 0.1940 0.0450 ;
      RECT 0.1840 0.0350 0.2150 0.0450 ;
      RECT 0.2050 0.0350 0.2360 0.0450 ;
      RECT 0.2260 0.0350 0.2570 0.0450 ;
      RECT 0.1210 0.0550 0.1520 0.0650 ;
      RECT 0.1420 0.0550 0.1730 0.0650 ;
      RECT 0.1630 0.0550 0.1940 0.0650 ;
      RECT 0.1840 0.0550 0.2150 0.0650 ;
      RECT 0.2050 0.0550 0.2360 0.0650 ;
      RECT 0.0370 0.0150 0.0680 0.0250 ;
      RECT 0.0580 0.0150 0.0890 0.0250 ;
      RECT 0.0790 0.0150 0.1100 0.0250 ;
      RECT 0.1000 0.0150 0.1310 0.0250 ;
      RECT 0.0160 0.0750 0.0470 0.0850 ;
      RECT 0.0370 0.0750 0.0680 0.0850 ;
      RECT 0.0580 0.0750 0.0890 0.0850 ;
      RECT 0.0790 0.0750 0.1100 0.0850 ;
      RECT 0.1000 0.0750 0.1310 0.0850 ;
      RECT 0.1210 0.0750 0.1520 0.0850 ;
      RECT 0.1420 0.0750 0.1730 0.0850 ;
      RECT 0.1630 0.0750 0.1940 0.0850 ;
      RECT 0.1840 0.0750 0.2150 0.0850 ;
      RECT 0.2050 0.0150 0.2360 0.0250 ;
      RECT 0.0790 0.0550 0.0890 0.0650 ;
      RECT 0.0370 0.0550 0.0470 0.0650 ;
      RECT 0.0370 0.0350 0.0470 0.0450 ;
      RECT 0.3310 0.0550 0.3410 0.0650 ;
      RECT 0.3310 0.0350 0.3410 0.0450 ;
      RECT 0.2470 0.0550 0.2780 0.0650 ;
      RECT 0.2680 0.0550 0.2990 0.0650 ;
      RECT 0.2890 0.0550 0.3200 0.0650 ;
      RECT 0.0790 0.0350 0.1100 0.0450 ;
      RECT 0.1000 0.0350 0.1310 0.0450 ;
      RECT 0.1210 0.0350 0.1520 0.0450 ;
      RECT 0.1420 0.0350 0.1730 0.0450 ;
      RECT 0.1630 0.0350 0.1940 0.0450 ;
      RECT 0.1840 0.0350 0.2150 0.0450 ;
      RECT 0.2050 0.0350 0.2360 0.0450 ;
      RECT 0.2260 0.0350 0.2570 0.0450 ;
      RECT 0.1210 0.0550 0.1520 0.0650 ;
      RECT 0.1420 0.0550 0.1730 0.0650 ;
      RECT 0.1630 0.0550 0.1940 0.0650 ;
      RECT 0.1840 0.0550 0.2150 0.0650 ;
      RECT 0.2050 0.0550 0.2360 0.0650 ;
      RECT 0.0370 0.0150 0.0680 0.0250 ;
      RECT 0.0580 0.0150 0.0890 0.0250 ;
      RECT 0.0790 0.0150 0.1100 0.0250 ;
      RECT 0.1000 0.0150 0.1310 0.0250 ;
      RECT 0.0160 0.0750 0.0470 0.0850 ;
      RECT 0.0370 0.0750 0.0680 0.0850 ;
      RECT 0.0580 0.0750 0.0890 0.0850 ;
      RECT 0.0790 0.0750 0.1100 0.0850 ;
      RECT 0.1000 0.0750 0.1310 0.0850 ;
      RECT 0.1210 0.0750 0.1520 0.0850 ;
      RECT 0.1420 0.0750 0.1730 0.0850 ;
      RECT 0.1630 0.0750 0.1940 0.0850 ;
      RECT 0.1840 0.0750 0.2150 0.0850 ;
      RECT 0.2050 0.0150 0.2360 0.0250 ;
      RECT 0.0790 0.0550 0.0890 0.0650 ;
      RECT 0.0370 0.0550 0.0470 0.0650 ;
      RECT 0.0370 0.0350 0.0470 0.0450 ;
      RECT 0.3310 0.0550 0.3410 0.0650 ;
      RECT 0.3310 0.0350 0.3410 0.0450 ;
      RECT 0.1420 0.0150 0.1600 0.0250 ;
      RECT 0.1750 0.0150 0.1940 0.0250 ;
  END
END MUX2_X1

MACRO MUX2_X2
  CLASS CORE ;
  FOREIGN MUX2_X2 0 0 ;
  ORIGIN -0.0210 -0.1000 ;
  SIZE 0.2940 BY 0.2000 ;
  SITE NSFET ;
  SYMMETRY X Y ;
  PIN S
    DIRECTION INPUT ;
    USE SIGNAL ;
    PORT
      LAYER M1 ;
        RECT 0.0770 -0.0070 0.0910 0.0270 ;
        RECT 0.0770 -0.0070 0.0910 0.0270 ;
    END
  END S
  PIN B
    DIRECTION INPUT ;
    USE SIGNAL ;
    PORT
      LAYER M1 ;
        RECT 0.1190 0.0330 0.1330 0.0670 ;
        RECT 0.1190 0.0330 0.1330 0.0670 ;
        RECT 0.2450 0.0130 0.2590 0.0270 ;
    END
  END B
  PIN A
    DIRECTION INPUT ;
    USE SIGNAL ;
    PORT
      LAYER M1 ;
        RECT 0.2030 0.0130 0.2170 0.0270 ;
    END
  END A
  PIN Z
    DIRECTION OUTPUT ;
    USE SIGNAL ;
    PORT
      LAYER M1 ;
        RECT 0.0350 -0.0670 0.0490 -0.0330 ;
        RECT 0.0350 -0.0670 0.0490 -0.0330 ;
    END
  END Z
  PIN VDD
    DIRECTION INOUT ;
    USE POWER ;
    PORT
      LAYER M0 ;
        RECT -0.0370 -0.1050 0.2890 -0.0950 ;
    END
  END VDD
  PIN VSS
    DIRECTION INOUT ;
    USE GROUND ;
    PORT
      LAYER M0 ;
        RECT -0.0370 -0.0050 0.2890 0.0050 ;
    END
  END VSS
  PIN VDD
    DIRECTION INOUT ;
    USE POWER ;
    PORT
      LAYER M0 ;
        RECT -0.0370 0.0950 0.2890 0.1050 ;
    END
  END VDD
  OBS
    LAYER M1 ;
      RECT 0.0350 0.0130 0.0490 0.0470 ;
      RECT 0.0350 -0.0070 0.0490 0.0270 ;
      RECT 0.0350 -0.0270 0.0490 0.0070 ;
      RECT 0.0770 0.0330 0.0910 0.0670 ;
      RECT 0.2450 0.0330 0.2590 0.0670 ;
      RECT 0.1610 -0.0070 0.1750 0.0270 ;
      RECT 0.1610 -0.0270 0.1750 0.0070 ;
      RECT 0.1610 -0.0470 0.1750 -0.0130 ;
      RECT 0.1610 -0.0670 0.1750 -0.0330 ;
      RECT 0.1190 0.0130 0.1330 0.0470 ;
      RECT 0.0770 -0.0270 0.0910 0.0070 ;
      RECT 0.0350 0.0130 0.0490 0.0470 ;
      RECT 0.0350 -0.0070 0.0490 0.0270 ;
      RECT 0.0350 -0.0270 0.0490 0.0070 ;
      RECT 0.0770 0.0330 0.0910 0.0670 ;
      RECT 0.2450 0.0330 0.2590 0.0670 ;
      RECT 0.1610 -0.0070 0.1750 0.0270 ;
      RECT 0.1610 -0.0270 0.1750 0.0070 ;
      RECT 0.1610 -0.0470 0.1750 -0.0130 ;
      RECT 0.1610 -0.0670 0.1750 -0.0330 ;
      RECT 0.1190 0.0130 0.1330 0.0470 ;
      RECT 0.0770 -0.0270 0.0910 0.0070 ;
    LAYER M0 ;
      RECT 0.0370 0.0350 0.0680 0.0450 ;
      RECT 0.0580 0.0350 0.0890 0.0450 ;
      RECT 0.0790 0.0350 0.1100 0.0450 ;
      RECT 0.1000 0.0350 0.1310 0.0450 ;
      RECT 0.1210 0.0350 0.1520 0.0450 ;
      RECT 0.1420 0.0350 0.1730 0.0450 ;
      RECT 0.1630 0.0350 0.1940 0.0450 ;
      RECT 0.1840 0.0350 0.2150 0.0450 ;
      RECT 0.2050 0.0350 0.2360 0.0450 ;
      RECT 0.2260 0.0350 0.2570 0.0450 ;
      RECT 0.0160 -0.0250 0.0470 -0.0150 ;
      RECT 0.0370 -0.0250 0.0680 -0.0150 ;
      RECT 0.1210 0.0750 0.1520 0.0850 ;
      RECT 0.1420 0.0750 0.1730 0.0850 ;
      RECT 0.1630 0.0750 0.1940 0.0850 ;
      RECT 0.1840 0.0750 0.2150 0.0850 ;
      RECT 0.1420 0.0150 0.1730 0.0250 ;
      RECT 0.1210 0.0550 0.1520 0.0650 ;
      RECT 0.1420 0.0550 0.1730 0.0650 ;
      RECT 0.1630 0.0550 0.1940 0.0650 ;
      RECT 0.1840 0.0550 0.2150 0.0650 ;
      RECT 0.2050 0.0550 0.2360 0.0650 ;
      RECT 0.1000 0.0150 0.1310 0.0250 ;
      RECT 0.0580 0.0750 0.0890 0.0850 ;
      RECT 0.0790 0.0750 0.1100 0.0850 ;
      RECT 0.0580 0.0150 0.0890 0.0250 ;
      RECT 0.0790 -0.0250 0.1100 -0.0150 ;
      RECT 0.1000 -0.0250 0.1310 -0.0150 ;
      RECT 0.1210 -0.0250 0.1520 -0.0150 ;
      RECT 0.0790 0.0550 0.0890 0.0650 ;
      RECT 0.2470 0.0550 0.2570 0.0650 ;
      RECT 0.0370 0.0150 0.0470 0.0250 ;
      RECT 0.1630 -0.0250 0.1730 -0.0150 ;
      RECT 0.1630 -0.0450 0.1730 -0.0350 ;
      RECT 0.1630 -0.0650 0.1730 -0.0550 ;
      RECT 0.0370 -0.0450 0.0470 -0.0350 ;
      RECT 0.0370 -0.0650 0.0470 -0.0550 ;
      RECT 0.0370 0.0350 0.0680 0.0450 ;
      RECT 0.0580 0.0350 0.0890 0.0450 ;
      RECT 0.0790 0.0350 0.1100 0.0450 ;
      RECT 0.1000 0.0350 0.1310 0.0450 ;
      RECT 0.1210 0.0350 0.1520 0.0450 ;
      RECT 0.1420 0.0350 0.1730 0.0450 ;
      RECT 0.1630 0.0350 0.1940 0.0450 ;
      RECT 0.1840 0.0350 0.2150 0.0450 ;
      RECT 0.2050 0.0350 0.2360 0.0450 ;
      RECT 0.2260 0.0350 0.2570 0.0450 ;
      RECT 0.0160 -0.0250 0.0470 -0.0150 ;
      RECT 0.0370 -0.0250 0.0680 -0.0150 ;
      RECT 0.1210 0.0750 0.1520 0.0850 ;
      RECT 0.1420 0.0750 0.1730 0.0850 ;
      RECT 0.1630 0.0750 0.1940 0.0850 ;
      RECT 0.1840 0.0750 0.2150 0.0850 ;
      RECT 0.1420 0.0150 0.1730 0.0250 ;
      RECT 0.1210 0.0550 0.1520 0.0650 ;
      RECT 0.1420 0.0550 0.1730 0.0650 ;
      RECT 0.1630 0.0550 0.1940 0.0650 ;
      RECT 0.1840 0.0550 0.2150 0.0650 ;
      RECT 0.2050 0.0550 0.2360 0.0650 ;
      RECT 0.1000 0.0150 0.1310 0.0250 ;
      RECT 0.0580 0.0750 0.0890 0.0850 ;
      RECT 0.0790 0.0750 0.1100 0.0850 ;
      RECT 0.0580 0.0150 0.0890 0.0250 ;
      RECT 0.0790 -0.0250 0.1100 -0.0150 ;
      RECT 0.1000 -0.0250 0.1310 -0.0150 ;
      RECT 0.1210 -0.0250 0.1520 -0.0150 ;
      RECT 0.0790 0.0550 0.0890 0.0650 ;
      RECT 0.2470 0.0550 0.2570 0.0650 ;
      RECT 0.0370 0.0150 0.0470 0.0250 ;
      RECT 0.1630 -0.0250 0.1730 -0.0150 ;
      RECT 0.1630 -0.0450 0.1730 -0.0350 ;
      RECT 0.1630 -0.0650 0.1730 -0.0550 ;
      RECT 0.0370 -0.0450 0.0470 -0.0350 ;
      RECT 0.0370 -0.0650 0.0470 -0.0550 ;
      RECT 0.1840 0.0150 0.2150 0.0250 ;
      RECT 0.2260 0.0150 0.2570 0.0250 ;
  END
END MUX2_X2

MACRO NAND2_X1
  CLASS CORE ;
  FOREIGN NAND2_X1 0 0 ;
  ORIGIN -0.0210 0.0000 ;
  SIZE 0.1260 BY 0.1000 ;
  SITE NSFET ;
  SYMMETRY X Y ;
  PIN A2
    DIRECTION INPUT ;
    USE SIGNAL ;
    PORT
      LAYER M1 ;
        RECT 0.0770 0.0330 0.0910 0.0670 ;
    END
  END A2
  PIN ZN
    DIRECTION OUTPUT ;
    USE SIGNAL ;
    PORT
      LAYER M1 ;
        RECT 0.0350 0.0330 0.0490 0.0670 ;
        RECT 0.0350 0.0330 0.0490 0.0670 ;
    END
  END ZN
  PIN A1
    DIRECTION INPUT ;
    USE SIGNAL ;
    PORT
      LAYER M1 ;
        RECT -0.0070 0.0330 0.0070 0.0680 ;
    END
  END A1
  PIN VDD
    DIRECTION INOUT ;
    USE POWER ;
    PORT
      LAYER M0 ;
        RECT -0.0370 0.0950 0.1210 0.1050 ;
    END
  END VDD
  PIN VSS
    DIRECTION INOUT ;
    USE GROUND ;
    PORT
      LAYER M0 ;
        RECT -0.0370 -0.0050 0.1210 0.0050 ;
    END
  END VSS
  OBS
    LAYER M0 ;
      RECT -0.0050 0.0350 0.0260 0.0450 ;
      RECT 0.0160 0.0350 0.0470 0.0450 ;
      RECT 0.0370 0.0550 0.0470 0.0650 ;
      RECT -0.0050 0.0350 0.0260 0.0450 ;
      RECT 0.0160 0.0350 0.0470 0.0450 ;
      RECT 0.0370 0.0550 0.0470 0.0650 ;
      RECT -0.0120 0.0550 0.0270 0.0650 ;
      RECT 0.0570 0.0550 0.0960 0.0650 ;
  END
END NAND2_X1

MACRO NAND2_X2
  CLASS CORE ;
  FOREIGN NAND2_X2 0 0 ;
  ORIGIN -0.0210 0.0000 ;
  SIZE 0.2100 BY 0.1000 ;
  SITE NSFET ;
  SYMMETRY X Y ;
  PIN ZN
    DIRECTION OUTPUT ;
    USE SIGNAL ;
    PORT
      LAYER M1 ;
        RECT 0.0770 0.0330 0.0910 0.0670 ;
        RECT 0.0770 0.0330 0.0910 0.0670 ;
    END
  END ZN
  PIN A2
    DIRECTION INPUT ;
    USE SIGNAL ;
    PORT
      LAYER M1 ;
        RECT 0.1190 0.0330 0.1330 0.0670 ;
        RECT 0.1190 0.0330 0.1330 0.0670 ;
    END
  END A2
  PIN A1
    DIRECTION INPUT ;
    USE SIGNAL ;
    PORT
      LAYER M1 ;
        RECT 0.1610 0.0330 0.1750 0.0670 ;
        RECT 0.1610 0.0330 0.1750 0.0670 ;
    END
  END A1
  PIN VSS
    DIRECTION INOUT ;
    USE GROUND ;
    PORT
      LAYER M0 ;
        RECT -0.0370 -0.0050 0.2050 0.0050 ;
    END
  END VSS
  PIN VDD
    DIRECTION INOUT ;
    USE POWER ;
    PORT
      LAYER M0 ;
        RECT -0.0370 0.0950 0.2050 0.1050 ;
    END
  END VDD
  OBS
    LAYER M1 ;
      RECT 0.1190 0.0530 0.1330 0.0870 ;
      RECT 0.1610 0.0130 0.1750 0.0470 ;
      RECT 0.1190 0.0530 0.1330 0.0870 ;
      RECT 0.1610 0.0130 0.1750 0.0470 ;
    LAYER M0 ;
      RECT 0.0370 0.0550 0.0680 0.0650 ;
      RECT 0.0580 0.0550 0.0890 0.0650 ;
      RECT 0.0790 0.0550 0.1100 0.0650 ;
      RECT 0.1000 0.0550 0.1310 0.0650 ;
      RECT 0.0160 0.0750 0.0470 0.0850 ;
      RECT 0.0370 0.0750 0.0680 0.0850 ;
      RECT 0.0580 0.0750 0.0890 0.0850 ;
      RECT 0.0790 0.0750 0.1100 0.0850 ;
      RECT 0.1000 0.0750 0.1310 0.0850 ;
      RECT 0.1210 0.0350 0.1520 0.0450 ;
      RECT 0.1420 0.0550 0.1730 0.0650 ;
      RECT 0.0580 0.0150 0.0890 0.0250 ;
      RECT 0.0790 0.0150 0.1100 0.0250 ;
      RECT 0.1000 0.0150 0.1310 0.0250 ;
      RECT 0.1210 0.0150 0.1520 0.0250 ;
      RECT 0.1420 0.0150 0.1730 0.0250 ;
      RECT 0.0790 0.0350 0.0890 0.0450 ;
      RECT 0.0370 0.0550 0.0680 0.0650 ;
      RECT 0.0580 0.0550 0.0890 0.0650 ;
      RECT 0.0790 0.0550 0.1100 0.0650 ;
      RECT 0.1000 0.0550 0.1310 0.0650 ;
      RECT 0.0160 0.0750 0.0470 0.0850 ;
      RECT 0.0370 0.0750 0.0680 0.0850 ;
      RECT 0.0580 0.0750 0.0890 0.0850 ;
      RECT 0.0790 0.0750 0.1100 0.0850 ;
      RECT 0.1000 0.0750 0.1310 0.0850 ;
      RECT 0.1210 0.0350 0.1520 0.0450 ;
      RECT 0.1420 0.0550 0.1730 0.0650 ;
      RECT 0.0580 0.0150 0.0890 0.0250 ;
      RECT 0.0790 0.0150 0.1100 0.0250 ;
      RECT 0.1000 0.0150 0.1310 0.0250 ;
      RECT 0.1210 0.0150 0.1520 0.0250 ;
      RECT 0.1420 0.0150 0.1730 0.0250 ;
      RECT 0.0790 0.0350 0.0890 0.0450 ;
  END
END NAND2_X2

MACRO NAND2_X4
  CLASS CORE ;
  FOREIGN NAND2_X4 0 0 ;
  ORIGIN -0.0210 0.0000 ;
  SIZE 0.3780 BY 0.1000 ;
  SITE NSFET ;
  SYMMETRY X Y ;
  PIN A1
    DIRECTION INPUT ;
    USE SIGNAL ;
    PORT
      LAYER M1 ;
        RECT 0.0350 0.0530 0.0490 0.0870 ;
    END
  END A1
  PIN A2
    DIRECTION INPUT ;
    USE SIGNAL ;
    PORT
      LAYER M1 ;
        RECT 0.2450 0.0530 0.2590 0.0870 ;
    END
  END A2
  PIN ZN
    DIRECTION OUTPUT ;
    USE SIGNAL ;
    PORT
      LAYER M1 ;
        RECT 0.2030 0.0330 0.2170 0.0670 ;
        RECT 0.2870 0.0330 0.3010 0.0670 ;
        RECT 0.2030 0.0330 0.2170 0.0670 ;
        RECT 0.2870 0.0330 0.3010 0.0670 ;
    END
  END ZN
  PIN VSS
    DIRECTION INOUT ;
    USE GROUND ;
    PORT
      LAYER M0 ;
        RECT -0.0370 -0.0050 0.3730 0.0050 ;
    END
  END VSS
  PIN VDD
    DIRECTION INOUT ;
    USE POWER ;
    PORT
      LAYER M0 ;
        RECT -0.0370 0.0950 0.3730 0.1050 ;
    END
  END VDD
  OBS
    LAYER M0 ;
      RECT 0.0370 0.0550 0.0680 0.0650 ;
      RECT 0.0580 0.0550 0.0890 0.0650 ;
      RECT 0.0790 0.0550 0.1100 0.0650 ;
      RECT 0.1000 0.0550 0.1310 0.0650 ;
      RECT 0.1210 0.0550 0.1520 0.0650 ;
      RECT 0.1420 0.0550 0.1730 0.0650 ;
      RECT 0.1630 0.0550 0.1940 0.0650 ;
      RECT 0.1840 0.0550 0.2150 0.0650 ;
      RECT 0.2050 0.0350 0.2360 0.0450 ;
      RECT 0.2260 0.0350 0.2570 0.0450 ;
      RECT 0.2470 0.0350 0.2780 0.0450 ;
      RECT 0.2680 0.0350 0.2990 0.0450 ;
      RECT -0.0050 0.0150 0.0260 0.0250 ;
      RECT 0.0160 0.0150 0.0470 0.0250 ;
      RECT 0.0370 0.0150 0.0680 0.0250 ;
      RECT 0.0580 0.0150 0.0890 0.0250 ;
      RECT 0.0790 0.0150 0.1100 0.0250 ;
      RECT 0.1000 0.0150 0.1310 0.0250 ;
      RECT 0.1210 0.0150 0.1520 0.0250 ;
      RECT 0.1420 0.0150 0.1730 0.0250 ;
      RECT 0.1630 0.0150 0.1940 0.0250 ;
      RECT 0.1840 0.0150 0.2150 0.0250 ;
      RECT 0.2050 0.0150 0.2360 0.0250 ;
      RECT 0.2260 0.0150 0.2570 0.0250 ;
      RECT 0.2470 0.0150 0.2780 0.0250 ;
      RECT 0.2680 0.0150 0.2990 0.0250 ;
      RECT 0.2890 0.0150 0.3200 0.0250 ;
      RECT 0.3100 0.0150 0.3410 0.0250 ;
      RECT 0.1840 0.0750 0.2150 0.0850 ;
      RECT 0.2050 0.0750 0.2360 0.0850 ;
      RECT 0.2260 0.0750 0.2570 0.0850 ;
      RECT 0.2470 0.0750 0.2780 0.0850 ;
      RECT 0.2680 0.0750 0.2990 0.0850 ;
      RECT 0.2890 0.0750 0.3200 0.0850 ;
      RECT 0.0160 0.0750 0.0470 0.0850 ;
      RECT 0.0370 0.0750 0.0680 0.0850 ;
      RECT 0.0580 0.0750 0.0890 0.0850 ;
      RECT 0.0790 0.0750 0.1100 0.0850 ;
      RECT 0.1000 0.0750 0.1310 0.0850 ;
      RECT 0.1210 0.0750 0.1520 0.0850 ;
      RECT 0.2890 0.0550 0.2990 0.0650 ;
      RECT 0.0370 0.0550 0.0680 0.0650 ;
      RECT 0.0580 0.0550 0.0890 0.0650 ;
      RECT 0.0790 0.0550 0.1100 0.0650 ;
      RECT 0.1000 0.0550 0.1310 0.0650 ;
      RECT 0.1210 0.0550 0.1520 0.0650 ;
      RECT 0.1420 0.0550 0.1730 0.0650 ;
      RECT 0.1630 0.0550 0.1940 0.0650 ;
      RECT 0.1840 0.0550 0.2150 0.0650 ;
      RECT 0.2050 0.0350 0.2360 0.0450 ;
      RECT 0.2260 0.0350 0.2570 0.0450 ;
      RECT 0.2470 0.0350 0.2780 0.0450 ;
      RECT 0.2680 0.0350 0.2990 0.0450 ;
      RECT -0.0050 0.0150 0.0260 0.0250 ;
      RECT 0.0160 0.0150 0.0470 0.0250 ;
      RECT 0.0370 0.0150 0.0680 0.0250 ;
      RECT 0.0580 0.0150 0.0890 0.0250 ;
      RECT 0.0790 0.0150 0.1100 0.0250 ;
      RECT 0.1000 0.0150 0.1310 0.0250 ;
      RECT 0.1210 0.0150 0.1520 0.0250 ;
      RECT 0.1420 0.0150 0.1730 0.0250 ;
      RECT 0.1630 0.0150 0.1940 0.0250 ;
      RECT 0.1840 0.0150 0.2150 0.0250 ;
      RECT 0.2050 0.0150 0.2360 0.0250 ;
      RECT 0.2260 0.0150 0.2570 0.0250 ;
      RECT 0.2470 0.0150 0.2780 0.0250 ;
      RECT 0.2680 0.0150 0.2990 0.0250 ;
      RECT 0.2890 0.0150 0.3200 0.0250 ;
      RECT 0.3100 0.0150 0.3410 0.0250 ;
      RECT 0.1840 0.0750 0.2150 0.0850 ;
      RECT 0.2050 0.0750 0.2360 0.0850 ;
      RECT 0.2260 0.0750 0.2570 0.0850 ;
      RECT 0.2470 0.0750 0.2780 0.0850 ;
      RECT 0.2680 0.0750 0.2990 0.0850 ;
      RECT 0.2890 0.0750 0.3200 0.0850 ;
      RECT 0.0160 0.0750 0.0470 0.0850 ;
      RECT 0.0370 0.0750 0.0680 0.0850 ;
      RECT 0.0580 0.0750 0.0890 0.0850 ;
      RECT 0.0790 0.0750 0.1100 0.0850 ;
      RECT 0.1000 0.0750 0.1310 0.0850 ;
      RECT 0.1210 0.0750 0.1520 0.0850 ;
      RECT 0.2890 0.0550 0.2990 0.0650 ;
  END
END NAND2_X4

MACRO NAND3_X1
  CLASS CORE ;
  FOREIGN NAND3_X1 0 0 ;
  ORIGIN -0.0210 0.0000 ;
  SIZE 0.1680 BY 0.1000 ;
  SITE NSFET ;
  SYMMETRY X Y ;
  PIN A3
    DIRECTION INPUT ;
    USE SIGNAL ;
    PORT
      LAYER M1 ;
        RECT 0.1200 0.0730 0.1340 0.0870 ;
    END
  END A3
  PIN A2
    DIRECTION INPUT ;
    USE SIGNAL ;
    PORT
      LAYER M1 ;
        RECT 0.0350 0.0330 0.0490 0.0470 ;
    END
  END A2
  PIN ZN
    DIRECTION OUTPUT ;
    USE SIGNAL ;
    PORT
      LAYER M1 ;
        RECT 0.0770 0.0330 0.0910 0.0670 ;
        RECT 0.0770 0.0330 0.0910 0.0670 ;
    END
  END ZN
  PIN A1
    DIRECTION INPUT ;
    USE SIGNAL ;
    PORT
      LAYER M1 ;
        RECT -0.0070 0.0330 0.0070 0.0470 ;
    END
  END A1
  PIN VSS
    DIRECTION INOUT ;
    USE GROUND ;
    PORT
      LAYER M0 ;
        RECT -0.0370 -0.0050 0.1630 0.0050 ;
    END
  END VSS
  PIN VDD
    DIRECTION INOUT ;
    USE POWER ;
    PORT
      LAYER M0 ;
        RECT -0.0370 0.0950 0.1630 0.1050 ;
    END
  END VDD
  OBS
    LAYER M0 ;
      RECT -0.0050 0.0550 0.0260 0.0650 ;
      RECT 0.0160 0.0550 0.0470 0.0650 ;
      RECT 0.0370 0.0550 0.0680 0.0650 ;
      RECT 0.0580 0.0550 0.0890 0.0650 ;
      RECT 0.0790 0.0350 0.1100 0.0450 ;
      RECT 0.1000 0.0350 0.1310 0.0450 ;
      RECT -0.0050 0.0550 0.0260 0.0650 ;
      RECT 0.0160 0.0550 0.0470 0.0650 ;
      RECT 0.0370 0.0550 0.0680 0.0650 ;
      RECT 0.0580 0.0550 0.0890 0.0650 ;
      RECT 0.0790 0.0350 0.1100 0.0450 ;
      RECT 0.1000 0.0350 0.1310 0.0450 ;
      RECT -0.0050 0.0350 0.0270 0.0450 ;
      RECT 0.1000 0.0750 0.1320 0.0850 ;
      RECT 0.0370 0.0350 0.0690 0.0450 ;
  END
END NAND3_X1

MACRO NAND4_X1
  CLASS CORE ;
  FOREIGN NAND4_X1 0 0 ;
  ORIGIN -0.0210 0.0000 ;
  SIZE 0.2520 BY 0.1000 ;
  SITE NSFET ;
  SYMMETRY X Y ;
  PIN ZN
    DIRECTION OUTPUT ;
    USE SIGNAL ;
    PORT
      LAYER M1 ;
        RECT 0.0350 0.0330 0.0490 0.0670 ;
        RECT 0.0350 0.0330 0.0490 0.0670 ;
    END
  END ZN
  PIN A1
    DIRECTION INPUT ;
    USE SIGNAL ;
    PORT
      LAYER M1 ;
        RECT -0.0070 0.0530 0.0070 0.0670 ;
    END
  END A1
  PIN A4
    DIRECTION INPUT ;
    USE SIGNAL ;
    PORT
      LAYER M1 ;
        RECT 0.1610 0.0330 0.1750 0.0470 ;
    END
  END A4
  PIN A2
    DIRECTION INPUT ;
    USE SIGNAL ;
    PORT
      LAYER M1 ;
        RECT 0.0760 0.0330 0.0900 0.0470 ;
    END
  END A2
  PIN A3
    DIRECTION INPUT ;
    USE SIGNAL ;
    PORT
      LAYER M1 ;
        RECT 0.1180 0.0330 0.1320 0.0470 ;
    END
  END A3
  PIN VSS
    DIRECTION INOUT ;
    USE GROUND ;
    PORT
      LAYER M0 ;
        RECT -0.0370 -0.0050 0.2470 0.0050 ;
    END
  END VSS
  PIN VDD
    DIRECTION INOUT ;
    USE POWER ;
    PORT
      LAYER M0 ;
        RECT -0.0370 0.0950 0.2470 0.1050 ;
    END
  END VDD
  OBS
    LAYER M0 ;
      RECT 0.0370 0.0550 0.0680 0.0650 ;
      RECT 0.0580 0.0550 0.0890 0.0650 ;
      RECT 0.0790 0.0550 0.1100 0.0650 ;
      RECT 0.1000 0.0550 0.1310 0.0650 ;
      RECT 0.1210 0.0550 0.1520 0.0650 ;
      RECT 0.1420 0.0550 0.1730 0.0650 ;
      RECT 0.1630 0.0550 0.1940 0.0650 ;
      RECT 0.1840 0.0550 0.2150 0.0650 ;
      RECT -0.0050 0.0350 0.0260 0.0450 ;
      RECT 0.0160 0.0350 0.0470 0.0450 ;
      RECT 0.1210 0.0150 0.1520 0.0250 ;
      RECT 0.1420 0.0150 0.1730 0.0250 ;
      RECT 0.0570 0.0350 0.0890 0.0450 ;
      RECT 0.0370 0.0550 0.0680 0.0650 ;
      RECT 0.0580 0.0550 0.0890 0.0650 ;
      RECT 0.0790 0.0550 0.1100 0.0650 ;
      RECT 0.1000 0.0550 0.1310 0.0650 ;
      RECT 0.1210 0.0550 0.1520 0.0650 ;
      RECT 0.1420 0.0550 0.1730 0.0650 ;
      RECT 0.1630 0.0550 0.1940 0.0650 ;
      RECT 0.1840 0.0550 0.2150 0.0650 ;
      RECT -0.0050 0.0350 0.0260 0.0450 ;
      RECT 0.0160 0.0350 0.0470 0.0450 ;
      RECT 0.1210 0.0150 0.1520 0.0250 ;
      RECT 0.1420 0.0150 0.1730 0.0250 ;
      RECT 0.1630 0.0350 0.1950 0.0450 ;
      RECT -0.0050 0.0550 0.0270 0.0650 ;
      RECT 0.0790 0.0550 0.1110 0.0650 ;
      RECT 0.1630 0.0550 0.1950 0.0650 ;
      RECT 0.0990 0.0350 0.1310 0.0450 ;
  END
END NAND4_X1

MACRO NOR2_X1
  CLASS CORE ;
  FOREIGN NOR2_X1 0 0 ;
  ORIGIN -0.0210 0.0000 ;
  SIZE 0.1260 BY 0.1000 ;
  SITE NSFET ;
  SYMMETRY X Y ;
  PIN ZN
    DIRECTION OUTPUT ;
    USE SIGNAL ;
    PORT
      LAYER M1 ;
        RECT 0.0350 0.0330 0.0490 0.0670 ;
        RECT 0.0350 0.0330 0.0490 0.0670 ;
    END
  END ZN
  PIN A2
    DIRECTION INPUT ;
    USE SIGNAL ;
    PORT
      LAYER M1 ;
        RECT 0.0770 0.0330 0.0910 0.0470 ;
    END
  END A2
  PIN A1
    DIRECTION INPUT ;
    USE SIGNAL ;
    PORT
      LAYER M1 ;
        RECT -0.0070 0.0530 0.0070 0.0670 ;
    END
  END A1
  PIN VSS
    DIRECTION INOUT ;
    USE GROUND ;
    PORT
      LAYER M0 ;
        RECT -0.0370 -0.0050 0.1210 0.0050 ;
    END
  END VSS
  PIN VDD
    DIRECTION INOUT ;
    USE POWER ;
    PORT
      LAYER M0 ;
        RECT -0.0370 0.0950 0.1210 0.1050 ;
    END
  END VDD
  OBS
    LAYER M0 ;
      RECT 0.0370 0.0550 0.0680 0.0650 ;
      RECT 0.0580 0.0550 0.0890 0.0650 ;
      RECT 0.0370 0.0350 0.0470 0.0450 ;
      RECT 0.0370 0.0550 0.0680 0.0650 ;
      RECT 0.0580 0.0550 0.0890 0.0650 ;
      RECT 0.0370 0.0350 0.0470 0.0450 ;
      RECT -0.0050 0.0550 0.0270 0.0650 ;
      RECT 0.0570 0.0350 0.0890 0.0450 ;
  END
END NOR2_X1

MACRO NOR2_X2
  CLASS CORE ;
  FOREIGN NOR2_X2 0 0 ;
  ORIGIN -0.0210 0.0000 ;
  SIZE 0.2100 BY 0.1000 ;
  SITE NSFET ;
  SYMMETRY X Y ;
  PIN ZN
    DIRECTION OUTPUT ;
    USE SIGNAL ;
    PORT
      LAYER M1 ;
        RECT 0.0770 0.0330 0.0910 0.0670 ;
        RECT 0.0770 0.0330 0.0910 0.0670 ;
    END
  END ZN
  PIN A2
    DIRECTION INPUT ;
    USE SIGNAL ;
    PORT
      LAYER M1 ;
        RECT 0.0350 0.0330 0.0490 0.0670 ;
        RECT 0.0350 0.0330 0.0490 0.0670 ;
    END
  END A2
  PIN A1
    DIRECTION INPUT ;
    USE SIGNAL ;
    PORT
      LAYER M1 ;
        RECT -0.0070 0.0330 0.0070 0.0670 ;
        RECT -0.0070 0.0330 0.0070 0.0670 ;
    END
  END A1
  PIN VSS
    DIRECTION INOUT ;
    USE GROUND ;
    PORT
      LAYER M0 ;
        RECT -0.0370 -0.0050 0.2050 0.0050 ;
    END
  END VSS
  PIN VDD
    DIRECTION INOUT ;
    USE POWER ;
    PORT
      LAYER M0 ;
        RECT -0.0370 0.0950 0.2050 0.1050 ;
    END
  END VDD
  OBS
    LAYER M1 ;
      RECT 0.0350 0.0130 0.0490 0.0470 ;
      RECT -0.0070 0.0530 0.0070 0.0870 ;
      RECT 0.0350 0.0130 0.0490 0.0470 ;
      RECT -0.0070 0.0530 0.0070 0.0870 ;
    LAYER M0 ;
      RECT 0.0370 0.0350 0.0680 0.0450 ;
      RECT 0.0580 0.0350 0.0890 0.0450 ;
      RECT 0.0790 0.0350 0.1100 0.0450 ;
      RECT 0.1000 0.0350 0.1310 0.0450 ;
      RECT 0.0160 0.0550 0.0470 0.0650 ;
      RECT 0.0370 0.0150 0.0680 0.0250 ;
      RECT 0.0580 0.0150 0.0890 0.0250 ;
      RECT 0.0790 0.0150 0.1100 0.0250 ;
      RECT 0.1000 0.0150 0.1310 0.0250 ;
      RECT 0.1210 0.0150 0.1520 0.0250 ;
      RECT -0.0050 0.0750 0.0260 0.0850 ;
      RECT 0.0160 0.0750 0.0470 0.0850 ;
      RECT 0.0370 0.0750 0.0680 0.0850 ;
      RECT 0.0580 0.0750 0.0890 0.0850 ;
      RECT 0.0790 0.0750 0.1100 0.0850 ;
      RECT -0.0050 0.0350 0.0260 0.0450 ;
      RECT 0.0790 0.0550 0.0890 0.0650 ;
      RECT 0.0370 0.0350 0.0680 0.0450 ;
      RECT 0.0580 0.0350 0.0890 0.0450 ;
      RECT 0.0790 0.0350 0.1100 0.0450 ;
      RECT 0.1000 0.0350 0.1310 0.0450 ;
      RECT 0.0160 0.0550 0.0470 0.0650 ;
      RECT 0.0370 0.0150 0.0680 0.0250 ;
      RECT 0.0580 0.0150 0.0890 0.0250 ;
      RECT 0.0790 0.0150 0.1100 0.0250 ;
      RECT 0.1000 0.0150 0.1310 0.0250 ;
      RECT 0.1210 0.0150 0.1520 0.0250 ;
      RECT -0.0050 0.0750 0.0260 0.0850 ;
      RECT 0.0160 0.0750 0.0470 0.0850 ;
      RECT 0.0370 0.0750 0.0680 0.0850 ;
      RECT 0.0580 0.0750 0.0890 0.0850 ;
      RECT 0.0790 0.0750 0.1100 0.0850 ;
      RECT -0.0050 0.0350 0.0260 0.0450 ;
      RECT 0.0790 0.0550 0.0890 0.0650 ;
  END
END NOR2_X2

MACRO NOR2_X4
  CLASS CORE ;
  FOREIGN NOR2_X4 0 0 ;
  ORIGIN -0.0210 0.0000 ;
  SIZE 0.3780 BY 0.1000 ;
  SITE NSFET ;
  SYMMETRY X Y ;
  PIN A1
    DIRECTION INPUT ;
    USE SIGNAL ;
    PORT
      LAYER M1 ;
        RECT -0.0070 0.0530 0.0070 0.0670 ;
    END
  END A1
  PIN ZN
    DIRECTION OUTPUT ;
    USE SIGNAL ;
    PORT
      LAYER M1 ;
        RECT 0.2870 0.0330 0.3010 0.0670 ;
    END
  END ZN
  PIN A2
    DIRECTION INPUT ;
    USE SIGNAL ;
    PORT
      LAYER M1 ;
        RECT 0.3290 0.0130 0.3430 0.0270 ;
    END
  END A2
  PIN VSS
    DIRECTION INOUT ;
    USE GROUND ;
    PORT
      LAYER M0 ;
        RECT -0.0370 -0.0050 0.3730 0.0050 ;
    END
  END VSS
  PIN VDD
    DIRECTION INOUT ;
    USE POWER ;
    PORT
      LAYER M0 ;
        RECT -0.0370 0.0950 0.3730 0.1050 ;
    END
  END VDD
  OBS
    LAYER M1 ;
      RECT 0.2030 0.0330 0.2170 0.0670 ;
    LAYER M0 ;
      RECT -0.0050 0.0750 0.0260 0.0850 ;
      RECT 0.0160 0.0750 0.0470 0.0850 ;
      RECT 0.0370 0.0750 0.0680 0.0850 ;
      RECT 0.0580 0.0750 0.0890 0.0850 ;
      RECT 0.0790 0.0750 0.1100 0.0850 ;
      RECT 0.1000 0.0750 0.1310 0.0850 ;
      RECT 0.1210 0.0750 0.1520 0.0850 ;
      RECT 0.1420 0.0750 0.1730 0.0850 ;
      RECT 0.1630 0.0750 0.1940 0.0850 ;
      RECT 0.1840 0.0750 0.2150 0.0850 ;
      RECT 0.2050 0.0750 0.2360 0.0850 ;
      RECT 0.2260 0.0750 0.2570 0.0850 ;
      RECT 0.2470 0.0750 0.2780 0.0850 ;
      RECT 0.2680 0.0750 0.2990 0.0850 ;
      RECT 0.2890 0.0750 0.3200 0.0850 ;
      RECT 0.3100 0.0750 0.3410 0.0850 ;
      RECT -0.0050 0.0350 0.0260 0.0450 ;
      RECT 0.0160 0.0350 0.0470 0.0450 ;
      RECT 0.0370 0.0350 0.0680 0.0450 ;
      RECT 0.0580 0.0350 0.0890 0.0450 ;
      RECT 0.0790 0.0350 0.1100 0.0450 ;
      RECT 0.1000 0.0350 0.1310 0.0450 ;
      RECT 0.1210 0.0350 0.1520 0.0450 ;
      RECT 0.1420 0.0350 0.1730 0.0450 ;
      RECT 0.1630 0.0350 0.1940 0.0450 ;
      RECT 0.1840 0.0350 0.2150 0.0450 ;
      RECT 0.2050 0.0350 0.2360 0.0450 ;
      RECT 0.2260 0.0350 0.2570 0.0450 ;
      RECT 0.2470 0.0350 0.2780 0.0450 ;
      RECT 0.2680 0.0350 0.2990 0.0450 ;
      RECT 0.2890 0.0350 0.3200 0.0450 ;
      RECT 0.3100 0.0350 0.3410 0.0450 ;
      RECT -0.0050 0.0550 0.0470 0.0650 ;
      RECT 0.0370 0.0550 0.0680 0.0650 ;
      RECT 0.0580 0.0550 0.0890 0.0650 ;
      RECT 0.0790 0.0550 0.1100 0.0650 ;
      RECT 0.1000 0.0550 0.1310 0.0650 ;
      RECT 0.1210 0.0550 0.1520 0.0650 ;
      RECT 0.1840 0.0150 0.2150 0.0250 ;
      RECT 0.2050 0.0150 0.2360 0.0250 ;
      RECT 0.2260 0.0150 0.2570 0.0250 ;
      RECT 0.2470 0.0150 0.2780 0.0250 ;
      RECT 0.2680 0.0150 0.2990 0.0250 ;
      RECT 0.2890 0.0150 0.3410 0.0250 ;
      RECT 0.2050 0.0550 0.2150 0.0650 ;
      RECT 0.2890 0.0550 0.2990 0.0650 ;
  END
END NOR2_X4

MACRO NOR3_X1
  CLASS CORE ;
  FOREIGN NOR3_X1 0 0 ;
  ORIGIN -0.0210 0.0000 ;
  SIZE 0.1680 BY 0.1000 ;
  SITE NSFET ;
  SYMMETRY X Y ;
  PIN A3
    DIRECTION INPUT ;
    USE SIGNAL ;
    PORT
      LAYER M1 ;
        RECT 0.1200 0.0530 0.1340 0.0720 ;
    END
  END A3
  PIN A1
    DIRECTION INPUT ;
    USE SIGNAL ;
    PORT
      LAYER M1 ;
        RECT -0.0070 0.0260 0.0070 0.0450 ;
    END
  END A1
  PIN ZN
    DIRECTION OUTPUT ;
    USE SIGNAL ;
    PORT
      LAYER M1 ;
        RECT 0.0350 0.0330 0.0490 0.0670 ;
        RECT 0.0350 0.0330 0.0490 0.0670 ;
    END
  END ZN
  PIN A2
    DIRECTION INPUT ;
    USE SIGNAL ;
    PORT
      LAYER M1 ;
        RECT 0.0770 0.0530 0.0910 0.0720 ;
    END
  END A2
  PIN VDD
    DIRECTION INOUT ;
    USE POWER ;
    PORT
      LAYER M0 ;
        RECT -0.0370 0.0950 0.1630 0.1050 ;
    END
  END VDD
  PIN VSS
    DIRECTION INOUT ;
    USE GROUND ;
    PORT
      LAYER M0 ;
        RECT -0.0370 -0.0050 0.1630 0.0050 ;
    END
  END VSS
  OBS
    LAYER M0 ;
      RECT 0.0570 0.0550 0.0900 0.0650 ;
      RECT -0.0050 0.0330 0.0260 0.0430 ;
      RECT 0.1000 0.0550 0.1330 0.0650 ;
      RECT 0.1000 0.0350 0.1310 0.0450 ;
      RECT 0.0790 0.0350 0.1100 0.0450 ;
      RECT 0.0580 0.0350 0.0890 0.0450 ;
      RECT 0.0370 0.0350 0.0680 0.0450 ;
      RECT 0.0160 0.0550 0.0470 0.0650 ;
      RECT -0.0050 0.0550 0.0260 0.0650 ;
      RECT 0.1000 0.0350 0.1310 0.0450 ;
      RECT 0.0790 0.0350 0.1100 0.0450 ;
      RECT 0.0580 0.0350 0.0890 0.0450 ;
      RECT 0.0370 0.0350 0.0680 0.0450 ;
      RECT 0.0160 0.0550 0.0470 0.0650 ;
      RECT -0.0050 0.0550 0.0260 0.0650 ;
  END
END NOR3_X1

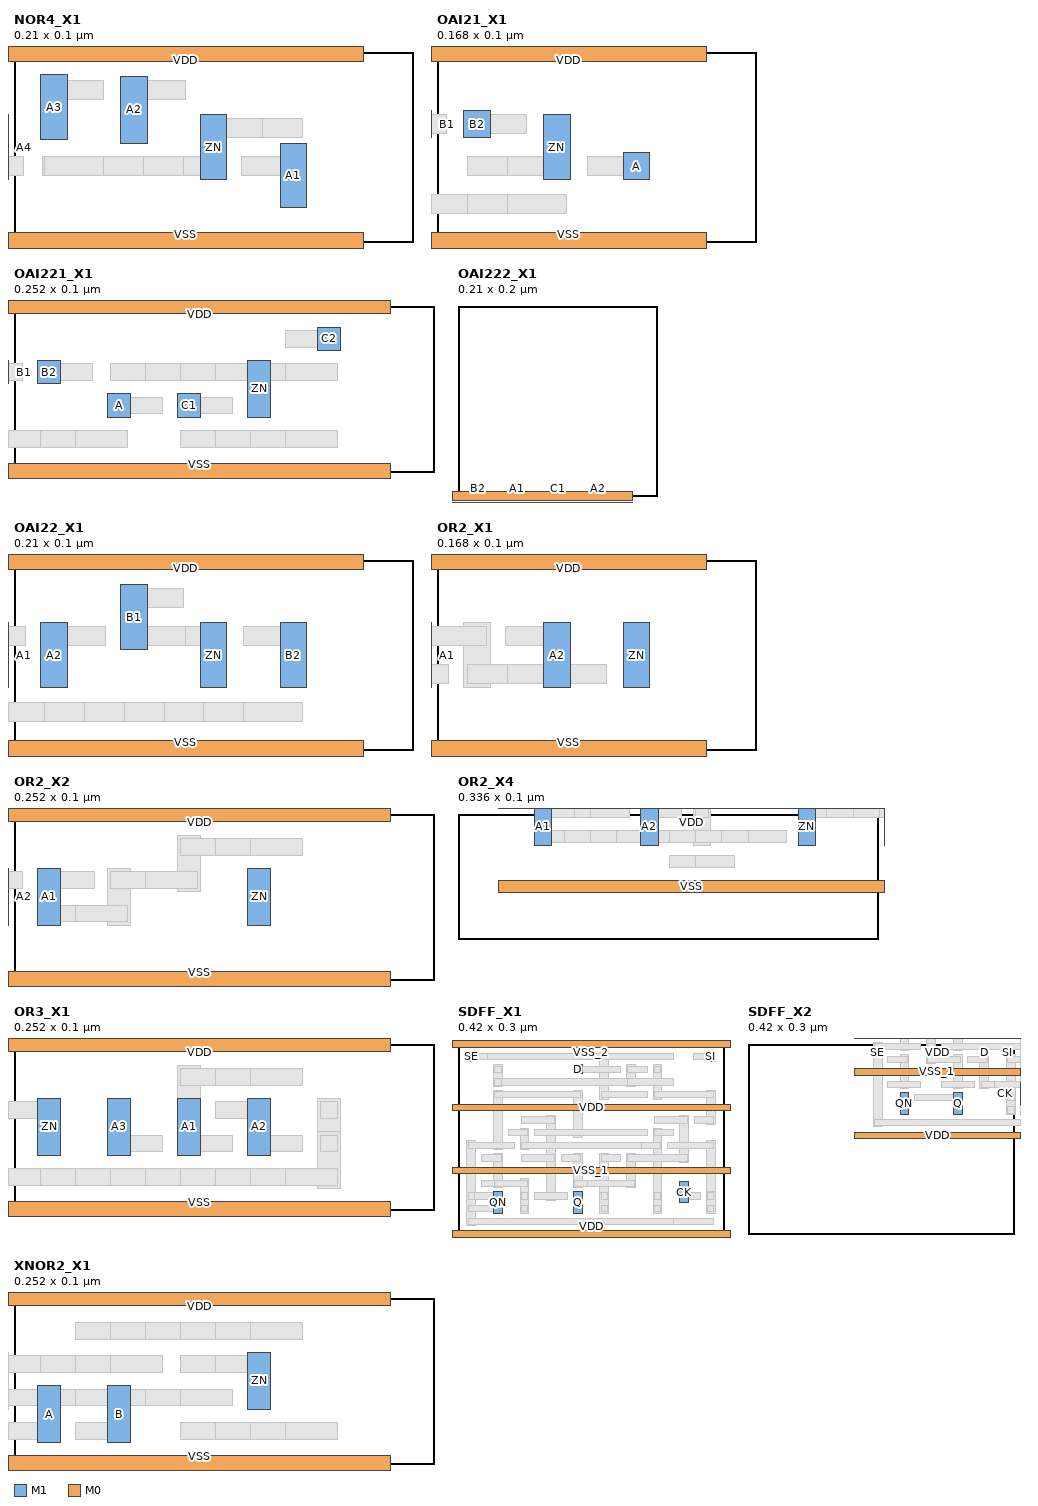
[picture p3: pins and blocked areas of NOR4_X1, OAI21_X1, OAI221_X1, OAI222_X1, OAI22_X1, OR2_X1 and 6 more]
MACRO NOR4_X1
  CLASS CORE ;
  FOREIGN NOR4_X1 0 0 ;
  ORIGIN -0.0210 0.0000 ;
  SIZE 0.2100 BY 0.1000 ;
  SITE NSFET ;
  SYMMETRY X Y ;
  PIN A1
    DIRECTION INPUT ;
    USE SIGNAL ;
    PORT
      LAYER M1 ;
        RECT 0.1610 0.0180 0.1750 0.0520 ;
    END
  END A1
  PIN A2
    DIRECTION INPUT ;
    USE SIGNAL ;
    PORT
      LAYER M1 ;
        RECT 0.0770 0.0520 0.0910 0.0870 ;
    END
  END A2
  PIN ZN
    DIRECTION OUTPUT ;
    USE SIGNAL ;
    PORT
      LAYER M1 ;
        RECT 0.1190 0.0330 0.1330 0.0670 ;
        RECT 0.1190 0.0330 0.1330 0.0670 ;
    END
  END ZN
  PIN A3
    DIRECTION INPUT ;
    USE SIGNAL ;
    PORT
      LAYER M1 ;
        RECT 0.0350 0.0540 0.0490 0.0880 ;
    END
  END A3
  PIN A4
    DIRECTION INPUT ;
    USE SIGNAL ;
    PORT
      LAYER M1 ;
        RECT -0.0070 0.0330 0.0070 0.0670 ;
    END
  END A4
  PIN VDD
    DIRECTION INOUT ;
    USE POWER ;
    PORT
      LAYER M0 ;
        RECT -0.0370 0.0950 0.2050 0.1050 ;
    END
  END VDD
  PIN VSS
    DIRECTION INOUT ;
    USE GROUND ;
    PORT
      LAYER M0 ;
        RECT -0.0370 -0.0050 0.2050 0.0050 ;
    END
  END VSS
  OBS
    LAYER M0 ;
      RECT 0.1410 0.0350 0.1740 0.0450 ;
      RECT 0.0780 0.0750 0.1110 0.0850 ;
      RECT 0.0370 0.0750 0.0680 0.0850 ;
      RECT 0.0360 0.0350 0.0690 0.0450 ;
      RECT -0.0080 0.0350 0.0260 0.0450 ;
      RECT 0.1000 0.0350 0.1310 0.0450 ;
      RECT 0.0790 0.0350 0.1100 0.0450 ;
      RECT 0.0580 0.0350 0.0890 0.0450 ;
      RECT 0.0370 0.0350 0.0680 0.0450 ;
      RECT 0.1420 0.0550 0.1730 0.0650 ;
      RECT 0.1210 0.0550 0.1520 0.0650 ;
      RECT 0.1000 0.0350 0.1310 0.0450 ;
      RECT 0.0790 0.0350 0.1100 0.0450 ;
      RECT 0.0580 0.0350 0.0890 0.0450 ;
      RECT 0.0370 0.0350 0.0680 0.0450 ;
      RECT 0.1420 0.0550 0.1730 0.0650 ;
      RECT 0.1210 0.0550 0.1520 0.0650 ;
  END
END NOR4_X1

MACRO OAI21_X1
  CLASS CORE ;
  FOREIGN OAI21_X1 0 0 ;
  ORIGIN -0.0210 0.0000 ;
  SIZE 0.1680 BY 0.1000 ;
  SITE NSFET ;
  SYMMETRY X Y ;
  PIN B1
    DIRECTION INPUT ;
    USE SIGNAL ;
    PORT
      LAYER M1 ;
        RECT -0.0070 0.0550 0.0070 0.0690 ;
    END
  END B1
  PIN B2
    DIRECTION INPUT ;
    USE SIGNAL ;
    PORT
      LAYER M1 ;
        RECT 0.0350 0.0550 0.0490 0.0690 ;
    END
  END B2
  PIN ZN
    DIRECTION OUTPUT ;
    USE SIGNAL ;
    PORT
      LAYER M1 ;
        RECT 0.0770 0.0330 0.0910 0.0670 ;
    END
  END ZN
  PIN A
    DIRECTION INPUT ;
    USE SIGNAL ;
    PORT
      LAYER M1 ;
        RECT 0.1190 0.0330 0.1330 0.0470 ;
    END
  END A
  PIN VSS
    DIRECTION INOUT ;
    USE GROUND ;
    PORT
      LAYER M0 ;
        RECT -0.0370 -0.0050 0.1630 0.0050 ;
    END
  END VSS
  PIN VDD
    DIRECTION INOUT ;
    USE POWER ;
    PORT
      LAYER M0 ;
        RECT -0.0370 0.0950 0.1630 0.1050 ;
    END
  END VDD
  OBS
    LAYER M0 ;
      RECT -0.0050 0.0150 0.0260 0.0250 ;
      RECT 0.0160 0.0150 0.0470 0.0250 ;
      RECT 0.0370 0.0150 0.0680 0.0250 ;
      RECT 0.0580 0.0150 0.0890 0.0250 ;
      RECT 0.0370 0.0350 0.0680 0.0450 ;
      RECT 0.0580 0.0350 0.0890 0.0450 ;
      RECT 0.0790 0.0550 0.0890 0.0650 ;
      RECT -0.0050 0.0570 0.0260 0.0670 ;
      RECT 0.0370 0.0570 0.0680 0.0670 ;
      RECT 0.1000 0.0350 0.1310 0.0450 ;
  END
END OAI21_X1

MACRO OAI221_X1
  CLASS CORE ;
  FOREIGN OAI221_X1 0 0 ;
  ORIGIN -0.0210 0.0000 ;
  SIZE 0.2520 BY 0.1000 ;
  SITE NSFET ;
  SYMMETRY X Y ;
  PIN B1
    DIRECTION INPUT ;
    USE SIGNAL ;
    PORT
      LAYER M1 ;
        RECT -0.0070 0.0530 0.0070 0.0670 ;
    END
  END B1
  PIN B2
    DIRECTION INPUT ;
    USE SIGNAL ;
    PORT
      LAYER M1 ;
        RECT 0.0350 0.0530 0.0490 0.0670 ;
    END
  END B2
  PIN A
    DIRECTION INPUT ;
    USE SIGNAL ;
    PORT
      LAYER M1 ;
        RECT 0.0770 0.0330 0.0910 0.0470 ;
    END
  END A
  PIN C1
    DIRECTION INPUT ;
    USE SIGNAL ;
    PORT
      LAYER M1 ;
        RECT 0.1190 0.0330 0.1330 0.0470 ;
    END
  END C1
  PIN ZN
    DIRECTION OUTPUT ;
    USE SIGNAL ;
    PORT
      LAYER M1 ;
        RECT 0.1610 0.0330 0.1750 0.0670 ;
    END
  END ZN
  PIN C2
    DIRECTION INPUT ;
    USE SIGNAL ;
    PORT
      LAYER M1 ;
        RECT 0.2030 0.0730 0.2170 0.0870 ;
    END
  END C2
  PIN VSS
    DIRECTION INOUT ;
    USE GROUND ;
    PORT
      LAYER M0 ;
        RECT -0.0370 -0.0050 0.2470 0.0050 ;
    END
  END VSS
  PIN VDD
    DIRECTION INOUT ;
    USE POWER ;
    PORT
      LAYER M0 ;
        RECT -0.0370 0.0950 0.2470 0.1050 ;
    END
  END VDD
  OBS
    LAYER M0 ;
      RECT -0.0050 0.0150 0.0260 0.0250 ;
      RECT 0.0160 0.0150 0.0470 0.0250 ;
      RECT 0.0370 0.0150 0.0680 0.0250 ;
      RECT 0.0580 0.0150 0.0890 0.0250 ;
      RECT 0.1210 0.0150 0.1520 0.0250 ;
      RECT 0.1420 0.0150 0.1730 0.0250 ;
      RECT 0.1630 0.0150 0.1940 0.0250 ;
      RECT 0.1840 0.0150 0.2150 0.0250 ;
      RECT 0.0790 0.0550 0.1100 0.0650 ;
      RECT 0.1000 0.0550 0.1310 0.0650 ;
      RECT 0.1210 0.0550 0.1520 0.0650 ;
      RECT 0.1420 0.0550 0.1730 0.0650 ;
      RECT 0.1630 0.0550 0.1940 0.0650 ;
      RECT 0.1840 0.0550 0.2150 0.0650 ;
      RECT 0.1630 0.0350 0.1730 0.0450 ;
      RECT -0.0050 0.0550 0.0260 0.0650 ;
      RECT 0.0370 0.0550 0.0680 0.0650 ;
      RECT 0.0790 0.0350 0.1100 0.0450 ;
      RECT 0.1210 0.0350 0.1520 0.0450 ;
      RECT 0.1840 0.0750 0.2150 0.0850 ;
  END
END OAI221_X1

MACRO OAI222_X1
  CLASS CORE ;
  FOREIGN OAI222_X1 0 0 ;
  ORIGIN -0.0210 -0.1000 ;
  SIZE 0.2100 BY 0.2000 ;
  SITE NSFET ;
  SYMMETRY X Y ;
  PIN ZN
    DIRECTION OUTPUT ;
    USE SIGNAL ;
    PORT
      LAYER M1 ;
        RECT 0.0770 -0.0070 0.0910 0.0270 ;
        RECT 0.0770 -0.0270 0.0910 0.0070 ;
        RECT 0.1190 -0.0670 0.1330 -0.0330 ;
        RECT 0.0770 -0.0070 0.0910 0.0270 ;
        RECT 0.0770 -0.0270 0.0910 0.0070 ;
        RECT 0.1190 -0.0670 0.1330 -0.0330 ;
    END
  END ZN
  PIN B1
    DIRECTION INPUT ;
    USE SIGNAL ;
    PORT
      LAYER M1 ;
        RECT -0.0070 0.0530 0.0070 0.0870 ;
    END
  END B1
  PIN B2
    DIRECTION INPUT ;
    USE SIGNAL ;
    PORT
      LAYER M1 ;
        RECT 0.0350 0.0530 0.0490 0.0870 ;
    END
  END B2
  PIN C2
    DIRECTION INPUT ;
    USE SIGNAL ;
    PORT
      LAYER M1 ;
        RECT 0.1610 0.0330 0.1750 0.0670 ;
    END
  END C2
  PIN C1
    DIRECTION INPUT ;
    USE SIGNAL ;
    PORT
      LAYER M1 ;
        RECT 0.1190 0.0330 0.1330 0.0670 ;
    END
  END C1
  PIN A2
    DIRECTION INPUT ;
    USE SIGNAL ;
    PORT
      LAYER M1 ;
        RECT 0.1610 -0.0670 0.1750 -0.0330 ;
    END
  END A2
  PIN A1
    DIRECTION INPUT ;
    USE SIGNAL ;
    PORT
      LAYER M1 ;
        RECT 0.0760 -0.0870 0.0900 -0.0730 ;
    END
  END A1
  PIN VSS
    DIRECTION INOUT ;
    USE GROUND ;
    PORT
      LAYER M0 ;
        RECT -0.0370 -0.0050 0.2050 0.0050 ;
    END
  END VSS
  PIN VDD
    DIRECTION INOUT ;
    USE POWER ;
    PORT
      LAYER M0 ;
        RECT -0.0370 0.0950 0.2050 0.1050 ;
    END
  END VDD
  PIN VDD
    DIRECTION INOUT ;
    USE POWER ;
    PORT
      LAYER M0 ;
        RECT -0.0370 -0.1050 0.2050 -0.0950 ;
    END
  END VDD
  OBS
    LAYER M1 ;
      RECT 0.0770 0.0330 0.0910 0.0670 ;
      RECT 0.0770 0.0130 0.0910 0.0470 ;
      RECT 0.0770 -0.0470 0.0910 -0.0130 ;
      RECT 0.0350 -0.0070 0.0490 0.0270 ;
      RECT 0.0350 -0.0270 0.0490 0.0070 ;
      RECT 0.0770 0.0330 0.0910 0.0670 ;
      RECT 0.0770 0.0130 0.0910 0.0470 ;
      RECT 0.0770 -0.0470 0.0910 -0.0130 ;
      RECT 0.0350 -0.0070 0.0490 0.0270 ;
      RECT 0.0350 -0.0270 0.0490 0.0070 ;
    LAYER M0 ;
      RECT 0.0790 -0.0450 0.1100 -0.0350 ;
      RECT 0.1000 -0.0450 0.1310 -0.0350 ;
      RECT 0.1210 -0.0650 0.1520 -0.0550 ;
      RECT 0.1420 -0.0650 0.1730 -0.0550 ;
      RECT -0.0050 0.0350 0.0260 0.0450 ;
      RECT 0.0160 0.0350 0.0470 0.0450 ;
      RECT 0.0370 0.0350 0.0680 0.0450 ;
      RECT 0.0580 0.0350 0.0890 0.0450 ;
      RECT 0.0790 0.0350 0.1100 0.0450 ;
      RECT 0.1000 0.0350 0.1310 0.0450 ;
      RECT 0.1210 0.0350 0.1520 0.0450 ;
      RECT 0.1420 0.0350 0.1730 0.0450 ;
      RECT 0.0370 -0.0250 0.0680 -0.0150 ;
      RECT 0.0580 -0.0250 0.0890 -0.0150 ;
      RECT 0.0790 -0.0250 0.1100 -0.0150 ;
      RECT 0.1000 -0.0250 0.1310 -0.0150 ;
      RECT 0.1210 -0.0250 0.1520 -0.0150 ;
      RECT 0.1420 -0.0250 0.1730 -0.0150 ;
      RECT 0.0790 0.0550 0.0890 0.0650 ;
      RECT 0.0370 0.0150 0.0470 0.0250 ;
      RECT 0.0790 -0.0450 0.1100 -0.0350 ;
      RECT 0.1000 -0.0450 0.1310 -0.0350 ;
      RECT 0.1210 -0.0650 0.1520 -0.0550 ;
      RECT 0.1420 -0.0650 0.1730 -0.0550 ;
      RECT -0.0050 0.0350 0.0260 0.0450 ;
      RECT 0.0160 0.0350 0.0470 0.0450 ;
      RECT 0.0370 0.0350 0.0680 0.0450 ;
      RECT 0.0580 0.0350 0.0890 0.0450 ;
      RECT 0.0790 0.0350 0.1100 0.0450 ;
      RECT 0.1000 0.0350 0.1310 0.0450 ;
      RECT 0.1210 0.0350 0.1520 0.0450 ;
      RECT 0.1420 0.0350 0.1730 0.0450 ;
      RECT 0.0370 -0.0250 0.0680 -0.0150 ;
      RECT 0.0580 -0.0250 0.0890 -0.0150 ;
      RECT 0.0790 -0.0250 0.1100 -0.0150 ;
      RECT 0.1000 -0.0250 0.1310 -0.0150 ;
      RECT 0.1210 -0.0250 0.1520 -0.0150 ;
      RECT 0.1420 -0.0250 0.1730 -0.0150 ;
      RECT 0.0790 0.0550 0.0890 0.0650 ;
      RECT 0.0370 0.0150 0.0470 0.0250 ;
      RECT -0.0060 0.0750 0.0260 0.0850 ;
      RECT 0.0360 0.0750 0.0680 0.0850 ;
      RECT 0.1420 0.0550 0.1740 0.0650 ;
      RECT 0.1000 0.0550 0.1320 0.0650 ;
      RECT 0.1420 -0.0450 0.1740 -0.0350 ;
      RECT 0.0780 -0.0850 0.1100 -0.0750 ;
  END
END OAI222_X1

MACRO OAI22_X1
  CLASS CORE ;
  FOREIGN OAI22_X1 0 0 ;
  ORIGIN -0.0210 0.0000 ;
  SIZE 0.2100 BY 0.1000 ;
  SITE NSFET ;
  SYMMETRY X Y ;
  PIN ZN
    DIRECTION OUTPUT ;
    USE SIGNAL ;
    PORT
      LAYER M1 ;
        RECT 0.1190 0.0330 0.1330 0.0670 ;
        RECT 0.1190 0.0330 0.1330 0.0670 ;
    END
  END ZN
  PIN A1
    DIRECTION INPUT ;
    USE SIGNAL ;
    PORT
      LAYER M1 ;
        RECT -0.0070 0.0330 0.0070 0.0670 ;
    END
  END A1
  PIN A2
    DIRECTION INPUT ;
    USE SIGNAL ;
    PORT
      LAYER M1 ;
        RECT 0.0350 0.0330 0.0490 0.0670 ;
    END
  END A2
  PIN B1
    DIRECTION INPUT ;
    USE SIGNAL ;
    PORT
      LAYER M1 ;
        RECT 0.0770 0.0530 0.0910 0.0870 ;
    END
  END B1
  PIN B2
    DIRECTION INPUT ;
    USE SIGNAL ;
    PORT
      LAYER M1 ;
        RECT 0.1610 0.0330 0.1750 0.0670 ;
    END
  END B2
  PIN VSS
    DIRECTION INOUT ;
    USE GROUND ;
    PORT
      LAYER M0 ;
        RECT -0.0370 -0.0050 0.2050 0.0050 ;
    END
  END VSS
  PIN VDD
    DIRECTION INOUT ;
    USE POWER ;
    PORT
      LAYER M0 ;
        RECT -0.0370 0.0950 0.2050 0.1050 ;
    END
  END VDD
  OBS
    LAYER M0 ;
      RECT -0.0050 0.0150 0.0260 0.0250 ;
      RECT 0.0160 0.0150 0.0470 0.0250 ;
      RECT 0.0370 0.0150 0.0680 0.0250 ;
      RECT 0.0580 0.0150 0.0890 0.0250 ;
      RECT 0.0790 0.0150 0.1100 0.0250 ;
      RECT 0.1000 0.0150 0.1310 0.0250 ;
      RECT 0.1210 0.0150 0.1520 0.0250 ;
      RECT 0.1420 0.0150 0.1730 0.0250 ;
      RECT 0.0790 0.0550 0.1100 0.0650 ;
      RECT 0.1000 0.0550 0.1310 0.0650 ;
      RECT 0.1210 0.0350 0.1310 0.0450 ;
      RECT -0.0050 0.0150 0.0260 0.0250 ;
      RECT 0.0160 0.0150 0.0470 0.0250 ;
      RECT 0.0370 0.0150 0.0680 0.0250 ;
      RECT 0.0580 0.0150 0.0890 0.0250 ;
      RECT 0.0790 0.0150 0.1100 0.0250 ;
      RECT 0.1000 0.0150 0.1310 0.0250 ;
      RECT 0.1210 0.0150 0.1520 0.0250 ;
      RECT 0.1420 0.0150 0.1730 0.0250 ;
      RECT 0.0790 0.0750 0.1100 0.0850 ;
      RECT 0.1000 0.0550 0.1310 0.0650 ;
      RECT 0.1210 0.0350 0.1310 0.0450 ;
      RECT -0.0050 0.0550 0.0270 0.0650 ;
      RECT 0.0370 0.0550 0.0690 0.0650 ;
      RECT 0.0790 0.0550 0.1110 0.0650 ;
      RECT 0.1420 0.0550 0.1740 0.0650 ;
  END
END OAI22_X1

MACRO OR2_X1
  CLASS CORE ;
  FOREIGN OR2_X1 0 0 ;
  ORIGIN -0.0210 0.0000 ;
  SIZE 0.1680 BY 0.1000 ;
  SITE NSFET ;
  SYMMETRY X Y ;
  PIN A1
    DIRECTION INPUT ;
    USE SIGNAL ;
    PORT
      LAYER M1 ;
        RECT -0.0070 0.0330 0.0070 0.0670 ;
    END
  END A1
  PIN A2
    DIRECTION INPUT ;
    USE SIGNAL ;
    PORT
      LAYER M1 ;
        RECT 0.0770 0.0330 0.0910 0.0670 ;
    END
  END A2
  PIN ZN
    DIRECTION OUTPUT ;
    USE SIGNAL ;
    PORT
      LAYER M1 ;
        RECT 0.1190 0.0330 0.1330 0.0670 ;
        RECT 0.1190 0.0330 0.1330 0.0670 ;
    END
  END ZN
  PIN VDD
    DIRECTION INOUT ;
    USE POWER ;
    PORT
      LAYER M0 ;
        RECT -0.0370 0.0950 0.1630 0.1050 ;
    END
  END VDD
  PIN VSS
    DIRECTION INOUT ;
    USE GROUND ;
    PORT
      LAYER M0 ;
        RECT -0.0370 -0.0050 0.1630 0.0050 ;
    END
  END VSS
  OBS
    LAYER M1 ;
      RECT 0.0350 0.0330 0.0490 0.0670 ;
      RECT 0.0350 0.0330 0.0490 0.0670 ;
    LAYER M0 ;
      RECT -0.0050 0.0550 0.0260 0.0650 ;
      RECT 0.0160 0.0550 0.0470 0.0650 ;
      RECT 0.0370 0.0350 0.0680 0.0450 ;
      RECT 0.0580 0.0350 0.0890 0.0450 ;
      RECT 0.0790 0.0350 0.1100 0.0450 ;
      RECT 0.1210 0.0550 0.1310 0.0650 ;
      RECT 0.1210 0.0350 0.1310 0.0450 ;
      RECT -0.0050 0.0550 0.0260 0.0650 ;
      RECT 0.0160 0.0550 0.0470 0.0650 ;
      RECT 0.0370 0.0350 0.0680 0.0450 ;
      RECT 0.0580 0.0350 0.0890 0.0450 ;
      RECT 0.0790 0.0350 0.1100 0.0450 ;
      RECT 0.1210 0.0550 0.1310 0.0650 ;
      RECT 0.1210 0.0350 0.1310 0.0450 ;
      RECT -0.0060 0.0350 0.0270 0.0450 ;
      RECT 0.0570 0.0550 0.0900 0.0650 ;
  END
END OR2_X1

MACRO OR2_X2
  CLASS CORE ;
  FOREIGN OR2_X2 0 0 ;
  ORIGIN -0.0210 0.0000 ;
  SIZE 0.2520 BY 0.1000 ;
  SITE NSFET ;
  SYMMETRY X Y ;
  PIN ZN
    DIRECTION OUTPUT ;
    USE SIGNAL ;
    PORT
      LAYER M1 ;
        RECT 0.1610 0.0330 0.1750 0.0670 ;
        RECT 0.1610 0.0330 0.1750 0.0670 ;
    END
  END ZN
  PIN A1
    DIRECTION INPUT ;
    USE SIGNAL ;
    PORT
      LAYER M1 ;
        RECT 0.0350 0.0330 0.0490 0.0670 ;
    END
  END A1
  PIN A2
    DIRECTION INPUT ;
    USE SIGNAL ;
    PORT
      LAYER M1 ;
        RECT -0.0070 0.0330 0.0070 0.0670 ;
    END
  END A2
  PIN VSS
    DIRECTION INOUT ;
    USE GROUND ;
    PORT
      LAYER M0 ;
        RECT -0.0370 -0.0050 0.2470 0.0050 ;
    END
  END VSS
  PIN VDD
    DIRECTION INOUT ;
    USE POWER ;
    PORT
      LAYER M0 ;
        RECT -0.0370 0.0950 0.2470 0.1050 ;
    END
  END VDD
  OBS
    LAYER M1 ;
      RECT 0.0770 0.0330 0.0910 0.0670 ;
      RECT 0.1190 0.0530 0.1330 0.0870 ;
      RECT 0.0770 0.0330 0.0910 0.0670 ;
      RECT 0.1190 0.0530 0.1330 0.0870 ;
    LAYER M0 ;
      RECT 0.1210 0.0750 0.1520 0.0850 ;
      RECT 0.1420 0.0750 0.1730 0.0850 ;
      RECT 0.1630 0.0750 0.1940 0.0850 ;
      RECT 0.0790 0.0550 0.1100 0.0650 ;
      RECT 0.1000 0.0550 0.1310 0.0650 ;
      RECT 0.0370 0.0350 0.0680 0.0450 ;
      RECT 0.0580 0.0350 0.0890 0.0450 ;
      RECT 0.1630 0.0550 0.1730 0.0650 ;
      RECT 0.1630 0.0350 0.1730 0.0450 ;
      RECT 0.1210 0.0750 0.1520 0.0850 ;
      RECT 0.1420 0.0750 0.1730 0.0850 ;
      RECT 0.1630 0.0750 0.1940 0.0850 ;
      RECT 0.0790 0.0550 0.1100 0.0650 ;
      RECT 0.1000 0.0550 0.1310 0.0650 ;
      RECT 0.0370 0.0350 0.0680 0.0450 ;
      RECT 0.0580 0.0350 0.0890 0.0450 ;
      RECT 0.1630 0.0550 0.1730 0.0650 ;
      RECT 0.1630 0.0350 0.1730 0.0450 ;
      RECT 0.0360 0.0550 0.0690 0.0650 ;
      RECT -0.0060 0.0550 0.0260 0.0650 ;
  END
END OR2_X2

MACRO OR2_X4
  CLASS CORE ;
  FOREIGN OR2_X4 0 0 ;
  ORIGIN 0.0240 0.0210 ;
  SIZE 0.3360 BY 0.1000 ;
  SITE NSFET ;
  SYMMETRY X Y ;
  PIN A1
    DIRECTION INPUT ;
    USE SIGNAL ;
    PORT
      LAYER M1 ;
        RECT 0.0370 0.0540 0.0510 0.0880 ;
    END
  END A1
  PIN A2
    DIRECTION INPUT ;
    USE SIGNAL ;
    PORT
      LAYER M1 ;
        RECT 0.1220 0.0540 0.1360 0.0880 ;
    END
  END A2
  PIN ZN
    DIRECTION OUTPUT ;
    USE SIGNAL ;
    PORT
      LAYER M1 ;
        RECT 0.3320 0.0540 0.3460 0.0880 ;
        RECT 0.2480 0.0540 0.2620 0.0880 ;
        RECT 0.2480 0.0540 0.2620 0.0880 ;
        RECT 0.3320 0.0540 0.3460 0.0880 ;
    END
  END ZN
  PIN VSS
    DIRECTION INOUT ;
    USE GROUND ;
    PORT
      LAYER M0 ;
        RECT 0.0080 0.0160 0.3760 0.0260 ;
    END
  END VSS
  PIN VDD
    DIRECTION INOUT ;
    USE POWER ;
    PORT
      LAYER M0 ;
        RECT 0.0080 0.1160 0.3760 0.1260 ;
    END
  END VDD
  OBS
    LAYER M1 ;
      RECT 0.1640 0.0540 0.1780 0.0880 ;
      RECT 0.1640 0.0540 0.1780 0.0880 ;
    LAYER M0 ;
      RECT 0.0400 0.0960 0.0710 0.1060 ;
      RECT 0.3130 0.0760 0.3440 0.0860 ;
      RECT 0.2920 0.0760 0.3230 0.0860 ;
      RECT 0.2710 0.0760 0.3020 0.0860 ;
      RECT 0.2500 0.0760 0.2810 0.0860 ;
      RECT 0.2080 0.0560 0.2390 0.0660 ;
      RECT 0.1870 0.0560 0.2180 0.0660 ;
      RECT 0.1660 0.0560 0.1970 0.0660 ;
      RECT 0.3340 0.0560 0.3440 0.0660 ;
      RECT 0.2500 0.0560 0.2600 0.0660 ;
      RECT 0.1660 0.0760 0.1760 0.0860 ;
      RECT 0.0820 0.0760 0.1130 0.0860 ;
      RECT 0.0610 0.0760 0.0920 0.0860 ;
      RECT 0.1660 0.0360 0.1970 0.0460 ;
      RECT 0.1450 0.0360 0.1760 0.0460 ;
      RECT 0.1870 0.0960 0.2180 0.1060 ;
      RECT 0.1660 0.0960 0.1970 0.1060 ;
      RECT 0.1450 0.0960 0.1760 0.1060 ;
      RECT 0.1240 0.0960 0.1550 0.1060 ;
      RECT 0.1030 0.0960 0.1340 0.1060 ;
      RECT 0.0820 0.0960 0.1130 0.1060 ;
      RECT 0.0610 0.0960 0.0920 0.1060 ;
      RECT 0.1450 0.0560 0.1760 0.0660 ;
      RECT 0.1240 0.0560 0.1550 0.0660 ;
      RECT 0.1030 0.0560 0.1340 0.0660 ;
      RECT 0.0820 0.0560 0.1130 0.0660 ;
      RECT 0.0610 0.0560 0.0920 0.0660 ;
      RECT 0.0400 0.0560 0.0710 0.0660 ;
      RECT 0.2920 0.0960 0.3230 0.1060 ;
      RECT 0.2710 0.0960 0.3020 0.1060 ;
      RECT 0.2500 0.0960 0.2810 0.1060 ;
      RECT 0.2290 0.0960 0.2600 0.1060 ;
      RECT 0.2290 0.0960 0.2600 0.1060 ;
      RECT 0.2500 0.0960 0.2810 0.1060 ;
      RECT 0.2710 0.0960 0.3020 0.1060 ;
      RECT 0.2920 0.0960 0.3230 0.1060 ;
      RECT 0.0400 0.0560 0.0710 0.0660 ;
      RECT 0.0610 0.0560 0.0920 0.0660 ;
      RECT 0.0820 0.0560 0.1130 0.0660 ;
      RECT 0.1030 0.0560 0.1340 0.0660 ;
      RECT 0.1240 0.0560 0.1550 0.0660 ;
      RECT 0.1450 0.0560 0.1760 0.0660 ;
      RECT 0.1660 0.0560 0.1970 0.0660 ;
      RECT 0.1870 0.0560 0.2180 0.0660 ;
      RECT 0.2080 0.0560 0.2390 0.0660 ;
      RECT 0.2500 0.0760 0.2810 0.0860 ;
      RECT 0.2710 0.0760 0.3020 0.0860 ;
      RECT 0.2920 0.0760 0.3230 0.0860 ;
      RECT 0.3130 0.0760 0.3440 0.0860 ;
      RECT 0.0400 0.0960 0.0710 0.1060 ;
      RECT 0.0610 0.0960 0.0920 0.1060 ;
      RECT 0.0820 0.0960 0.1130 0.1060 ;
      RECT 0.1030 0.0960 0.1340 0.1060 ;
      RECT 0.1240 0.0960 0.1550 0.1060 ;
      RECT 0.1450 0.0960 0.1760 0.1060 ;
      RECT 0.1660 0.0960 0.1970 0.1060 ;
      RECT 0.1870 0.0960 0.2180 0.1060 ;
      RECT 0.1450 0.0360 0.1760 0.0460 ;
      RECT 0.1660 0.0360 0.1970 0.0460 ;
      RECT 0.0610 0.0760 0.0920 0.0860 ;
      RECT 0.0820 0.0760 0.1130 0.0860 ;
      RECT 0.1660 0.0760 0.1760 0.0860 ;
      RECT 0.2500 0.0560 0.2600 0.0660 ;
      RECT 0.3340 0.0560 0.3440 0.0660 ;
      RECT 0.0380 0.0760 0.0690 0.0860 ;
      RECT 0.1240 0.0760 0.1550 0.0860 ;
  END
END OR2_X4

MACRO OR3_X1
  CLASS CORE ;
  FOREIGN OR3_X1 0 0 ;
  ORIGIN -0.0210 0.0000 ;
  SIZE 0.2520 BY 0.1000 ;
  SITE NSFET ;
  SYMMETRY X Y ;
  PIN A1
    DIRECTION INPUT ;
    USE SIGNAL ;
    PORT
      LAYER M1 ;
        RECT 0.1190 0.0330 0.1330 0.0670 ;
        RECT 0.1190 0.0330 0.1330 0.0670 ;
    END
  END A1
  PIN A2
    DIRECTION INPUT ;
    USE SIGNAL ;
    PORT
      LAYER M1 ;
        RECT 0.1610 0.0330 0.1750 0.0670 ;
        RECT 0.1610 0.0330 0.1750 0.0670 ;
    END
  END A2
  PIN A3
    DIRECTION INPUT ;
    USE SIGNAL ;
    PORT
      LAYER M1 ;
        RECT 0.0770 0.0330 0.0910 0.0670 ;
    END
  END A3
  PIN ZN
    DIRECTION OUTPUT ;
    USE SIGNAL ;
    PORT
      LAYER M1 ;
        RECT 0.0350 0.0330 0.0490 0.0670 ;
        RECT 0.0350 0.0330 0.0490 0.0670 ;
    END
  END ZN
  PIN VSS
    DIRECTION INOUT ;
    USE GROUND ;
    PORT
      LAYER M0 ;
        RECT -0.0370 -0.0050 0.2470 0.0050 ;
    END
  END VSS
  PIN VDD
    DIRECTION INOUT ;
    USE POWER ;
    PORT
      LAYER M0 ;
        RECT -0.0370 0.0950 0.2470 0.1050 ;
    END
  END VDD
  OBS
    LAYER M1 ;
      RECT 0.2030 0.0330 0.2170 0.0670 ;
      RECT 0.2030 0.0130 0.2170 0.0470 ;
      RECT 0.1190 0.0530 0.1330 0.0870 ;
      RECT 0.2030 0.0330 0.2170 0.0670 ;
      RECT 0.2030 0.0130 0.2170 0.0470 ;
      RECT 0.1190 0.0530 0.1330 0.0870 ;
    LAYER M0 ;
      RECT -0.0050 0.0550 0.0260 0.0650 ;
      RECT 0.0160 0.0550 0.0470 0.0650 ;
      RECT 0.0160 0.0150 0.0470 0.0250 ;
      RECT 0.0370 0.0150 0.0680 0.0250 ;
      RECT 0.0580 0.0150 0.0890 0.0250 ;
      RECT 0.0790 0.0150 0.1100 0.0250 ;
      RECT 0.1000 0.0150 0.1310 0.0250 ;
      RECT 0.1210 0.0150 0.1520 0.0250 ;
      RECT 0.1420 0.0150 0.1730 0.0250 ;
      RECT 0.1630 0.0150 0.1940 0.0250 ;
      RECT 0.1840 0.0150 0.2150 0.0250 ;
      RECT 0.1420 0.0550 0.1730 0.0650 ;
      RECT 0.1630 0.0350 0.1940 0.0450 ;
      RECT 0.1210 0.0750 0.1520 0.0850 ;
      RECT 0.1420 0.0750 0.1730 0.0850 ;
      RECT 0.1630 0.0750 0.1940 0.0850 ;
      RECT 0.1210 0.0350 0.1520 0.0450 ;
      RECT 0.0370 0.0350 0.0470 0.0450 ;
      RECT 0.2050 0.0550 0.2150 0.0650 ;
      RECT 0.2050 0.0350 0.2150 0.0450 ;
      RECT -0.0050 0.0550 0.0260 0.0650 ;
      RECT 0.0160 0.0550 0.0470 0.0650 ;
      RECT 0.0160 0.0150 0.0470 0.0250 ;
      RECT 0.0370 0.0150 0.0680 0.0250 ;
      RECT 0.0580 0.0150 0.0890 0.0250 ;
      RECT 0.0790 0.0150 0.1100 0.0250 ;
      RECT 0.1000 0.0150 0.1310 0.0250 ;
      RECT 0.1210 0.0150 0.1520 0.0250 ;
      RECT 0.1420 0.0150 0.1730 0.0250 ;
      RECT 0.1630 0.0150 0.1940 0.0250 ;
      RECT 0.1840 0.0150 0.2150 0.0250 ;
      RECT 0.1420 0.0550 0.1730 0.0650 ;
      RECT 0.1630 0.0350 0.1940 0.0450 ;
      RECT 0.1210 0.0750 0.1520 0.0850 ;
      RECT 0.1420 0.0750 0.1730 0.0850 ;
      RECT 0.1630 0.0750 0.1940 0.0850 ;
      RECT 0.1210 0.0350 0.1520 0.0450 ;
      RECT 0.0370 0.0350 0.0470 0.0450 ;
      RECT 0.2050 0.0550 0.2150 0.0650 ;
      RECT 0.2050 0.0350 0.2150 0.0450 ;
      RECT 0.0790 0.0350 0.1100 0.0450 ;
  END
END OR3_X1

MACRO SDFF_X1
  CLASS CORE ;
  FOREIGN SDFF_X1 0 0 ;
  ORIGIN 0.0000 0.0000 ;
  SIZE 0.4200 BY 0.3000 ;
  SITE NSFET ;
  SYMMETRY X Y ;
  PIN SI
    DIRECTION INPUT ;
    USE SIGNAL ;
    PORT
      LAYER M1 ;
        RECT 0.3920 0.2730 0.4060 0.2870 ;
    END
  END SI
  PIN SE
    DIRECTION INPUT ;
    USE SIGNAL ;
    PORT
      LAYER M1 ;
        RECT 0.0140 0.2730 0.0280 0.2870 ;
    END
  END SE
  PIN D
    DIRECTION INPUT ;
    USE SIGNAL ;
    PORT
      LAYER M1 ;
        RECT 0.1820 0.2530 0.1960 0.2670 ;
    END
  END D
  PIN CK
    DIRECTION INPUT ;
    USE CLOCK ;
    PORT
      LAYER M1 ;
        RECT 0.3500 0.0490 0.3640 0.0830 ;
    END
  END CK
  PIN QN
    DIRECTION OUTPUT ;
    USE SIGNAL ;
    PORT
      LAYER M1 ;
        RECT 0.0560 0.0330 0.0700 0.0670 ;
    END
  END QN
  PIN Q
    DIRECTION OUTPUT ;
    USE SIGNAL ;
    PORT
      LAYER M1 ;
        RECT 0.1820 0.0330 0.1960 0.0670 ;
        RECT 0.1820 0.0330 0.1960 0.0670 ;
    END
  END Q
  PIN VSS_1
    DIRECTION INOUT ;
    USE GROUND ;
    PORT
      LAYER M0 ;
        RECT -0.0160 0.0950 0.4360 0.1050 ;
    END
  END VSS_1
  PIN VDD
    DIRECTION INOUT ;
    USE POWER ;
    PORT
      LAYER M0 ;
        RECT -0.0160 -0.0050 0.4360 0.0050 ;
    END
  END VDD
  PIN VDD
    DIRECTION INOUT ;
    USE POWER ;
    PORT
      LAYER M0 ;
        RECT -0.0160 0.1950 0.4360 0.2050 ;
    END
  END VDD
  PIN VSS_2
    DIRECTION INOUT ;
    USE GROUND ;
    PORT
      LAYER M0 ;
        RECT -0.0160 0.2950 0.4360 0.3050 ;
    END
  END VSS_2
  OBS
    LAYER M1 ;
      RECT 0.2240 0.2130 0.2380 0.2870 ;
      RECT 0.0560 0.2330 0.0700 0.2670 ;
      RECT 0.3080 0.2130 0.3220 0.2670 ;
      RECT 0.2660 0.2330 0.2800 0.2670 ;
      RECT 0.0980 0.0330 0.1120 0.0670 ;
      RECT 0.0980 0.1330 0.1120 0.1670 ;
      RECT 0.0980 0.1330 0.1120 0.1670 ;
      RECT 0.1400 0.1330 0.1540 0.1670 ;
      RECT 0.3080 0.0330 0.3220 0.0670 ;
      RECT 0.3920 0.0330 0.4060 0.1470 ;
      RECT 0.3920 0.0330 0.4060 0.0670 ;
      RECT 0.3080 0.0330 0.3220 0.0670 ;
      RECT 0.0560 0.0730 0.0700 0.1270 ;
      RECT 0.2240 0.0330 0.2380 0.0670 ;
      RECT 0.3080 0.1330 0.3220 0.1670 ;
      RECT 0.3080 0.1330 0.3220 0.1670 ;
      RECT 0.0560 0.1330 0.0700 0.2270 ;
      RECT 0.1820 0.1530 0.1960 0.2270 ;
      RECT 0.2240 0.0330 0.2380 0.0670 ;
      RECT 0.2240 0.0650 0.2380 0.1270 ;
      RECT 0.0140 0.0130 0.0280 0.1470 ;
      RECT 0.0980 0.0330 0.1120 0.0870 ;
      RECT 0.3080 0.0660 0.3220 0.1430 ;
      RECT 0.1400 0.0530 0.1540 0.1870 ;
      RECT 0.1820 0.0730 0.1960 0.1270 ;
      RECT 0.3920 0.1730 0.4060 0.2270 ;
      RECT 0.3500 0.1130 0.3640 0.1870 ;
      RECT 0.2660 0.0730 0.2800 0.1270 ;
    LAYER M0 ;
      RECT 0.0580 0.2350 0.2780 0.2450 ;
      RECT 0.3720 0.2750 0.4040 0.2850 ;
      RECT 0.0580 0.2550 0.0680 0.2650 ;
      RECT 0.0370 0.2750 0.3410 0.2850 ;
      RECT 0.3100 0.2150 0.4040 0.2250 ;
      RECT 0.2680 0.2350 0.3410 0.2450 ;
      RECT 0.0160 0.2750 0.0470 0.2850 ;
      RECT 0.3730 0.1750 0.4040 0.1850 ;
      RECT 0.2260 0.2150 0.2990 0.2250 ;
      RECT 0.2680 0.2550 0.2990 0.2650 ;
      RECT 0.1840 0.2550 0.2570 0.2650 ;
      RECT 0.3100 0.2550 0.3200 0.2650 ;
      RECT 0.3310 0.1350 0.4040 0.1450 ;
      RECT 0.1630 0.1150 0.1940 0.1250 ;
      RECT 0.1840 0.0350 0.1940 0.0450 ;
      RECT 0.3310 0.0150 0.4040 0.0250 ;
      RECT 0.3520 0.0550 0.3830 0.0650 ;
      RECT 0.3940 0.0350 0.4040 0.0450 ;
      RECT 0.3100 0.0350 0.3200 0.0450 ;
      RECT 0.3100 0.0350 0.3200 0.0450 ;
      RECT 0.3940 0.0350 0.4040 0.0450 ;
      RECT 0.3100 0.0550 0.3200 0.0650 ;
      RECT 0.3100 0.0550 0.3200 0.0650 ;
      RECT 0.1840 0.0550 0.1940 0.0650 ;
      RECT 0.2260 0.0350 0.2360 0.0450 ;
      RECT 0.2260 0.0550 0.2360 0.0650 ;
      RECT 0.1840 0.0750 0.2570 0.0850 ;
      RECT 0.1210 0.0550 0.1730 0.0650 ;
      RECT 0.0160 0.0150 0.3410 0.0250 ;
      RECT 0.0370 0.0750 0.0890 0.0850 ;
      RECT 0.2260 0.0550 0.2360 0.0650 ;
      RECT 0.0580 0.2150 0.1940 0.2250 ;
      RECT 0.0160 0.0550 0.0680 0.0650 ;
      RECT 0.0580 0.2350 0.0680 0.2450 ;
      RECT 0.2260 0.1150 0.2570 0.1250 ;
      RECT 0.1000 0.1350 0.2900 0.1450 ;
      RECT 0.0160 0.0350 0.0680 0.0450 ;
      RECT 0.2680 0.1150 0.3620 0.1250 ;
      RECT 0.0790 0.1550 0.1100 0.1650 ;
      RECT 0.0370 0.1150 0.0680 0.1250 ;
      RECT 0.3100 0.1550 0.3410 0.1650 ;
      RECT 0.1000 0.1150 0.1520 0.1250 ;
      RECT 0.1000 0.0350 0.1100 0.0450 ;
      RECT 0.2050 0.0750 0.2780 0.0850 ;
      RECT 0.0580 0.0750 0.1100 0.0850 ;
      RECT 0.2890 0.1350 0.3200 0.1450 ;
      RECT 0.0160 0.1350 0.0890 0.1450 ;
      RECT 0.1840 0.0350 0.1940 0.0450 ;
      RECT 0.1840 0.0550 0.1940 0.0650 ;
      RECT 0.1000 0.0350 0.1100 0.0450 ;
      RECT 0.0160 0.0550 0.0260 0.0650 ;
      RECT 0.3100 0.1750 0.3620 0.1850 ;
      RECT 0.1000 0.1750 0.1520 0.1850 ;
      RECT 0.1210 0.1550 0.2990 0.1650 ;
      RECT 0.1000 0.0550 0.1100 0.0650 ;
      RECT 0.3940 0.0550 0.4040 0.0650 ;
  END
END SDFF_X1

MACRO SDFF_X2
  CLASS CORE ;
  FOREIGN SDFF_X2 0 0 ;
  ORIGIN 0.0920 0.0780 ;
  SIZE 0.4200 BY 0.3000 ;
  SITE NSFET ;
  SYMMETRY X Y ;
  PIN SI
    DIRECTION INPUT ;
    USE SIGNAL ;
    PORT
      LAYER M1 ;
        RECT 0.4840 0.3510 0.4980 0.3650 ;
    END
  END SI
  PIN SE
    DIRECTION INPUT ;
    USE SIGNAL ;
    PORT
      LAYER M1 ;
        RECT 0.1060 0.3510 0.1200 0.3650 ;
    END
  END SE
  PIN D
    DIRECTION INPUT ;
    USE SIGNAL ;
    PORT
      LAYER M1 ;
        RECT 0.2740 0.3310 0.2880 0.3450 ;
    END
  END D
  PIN CK
    DIRECTION INPUT ;
    USE CLOCK ;
    PORT
      LAYER M1 ;
        RECT 0.4420 0.1270 0.4560 0.1610 ;
    END
  END CK
  PIN QN
    DIRECTION OUTPUT ;
    USE SIGNAL ;
    PORT
      LAYER M1 ;
        RECT 0.1480 0.1110 0.1620 0.1450 ;
    END
  END QN
  PIN Q
    DIRECTION OUTPUT ;
    USE SIGNAL ;
    PORT
      LAYER M1 ;
        RECT 0.2320 0.1110 0.2460 0.1450 ;
    END
  END Q
  PIN VSS_1
    DIRECTION INOUT ;
    USE GROUND ;
    PORT
      LAYER M0 ;
        RECT 0.0760 0.1730 0.5280 0.1830 ;
    END
  END VSS_1
  PIN VDD
    DIRECTION INOUT ;
    USE POWER ;
    PORT
      LAYER M0 ;
        RECT 0.0760 0.0730 0.5280 0.0830 ;
    END
  END VDD
  PIN VDD
    DIRECTION INOUT ;
    USE POWER ;
    PORT
      LAYER M0 ;
        RECT 0.0760 0.2730 0.5280 0.2830 ;
    END
  END VDD
  PIN VSS_2
    DIRECTION INOUT ;
    USE GROUND ;
    PORT
      LAYER M0 ;
        RECT 0.0760 0.3730 0.5280 0.3830 ;
    END
  END VSS_2
  OBS
    LAYER M1 ;
      RECT 0.2320 0.1510 0.2460 0.2050 ;
      RECT 0.3160 0.2910 0.3300 0.3650 ;
      RECT 0.1480 0.3110 0.1620 0.3450 ;
      RECT 0.4000 0.2910 0.4140 0.3450 ;
      RECT 0.3580 0.3110 0.3720 0.3450 ;
      RECT 0.1900 0.1920 0.2040 0.2450 ;
      RECT 0.1900 0.2110 0.2040 0.2450 ;
      RECT 0.2320 0.2110 0.2460 0.2450 ;
      RECT 0.4000 0.1110 0.4140 0.1450 ;
      RECT 0.4840 0.1110 0.4980 0.2250 ;
      RECT 0.4840 0.1110 0.4980 0.1450 ;
      RECT 0.4000 0.1110 0.4140 0.1450 ;
      RECT 0.1480 0.1510 0.1620 0.2050 ;
      RECT 0.3160 0.1110 0.3300 0.1450 ;
      RECT 0.4000 0.2110 0.4140 0.2450 ;
      RECT 0.4000 0.2110 0.4140 0.2450 ;
      RECT 0.1480 0.2110 0.1620 0.3050 ;
      RECT 0.2740 0.2310 0.2880 0.3050 ;
      RECT 0.3160 0.1110 0.3300 0.1450 ;
      RECT 0.3160 0.1430 0.3300 0.2050 ;
      RECT 0.1060 0.0910 0.1200 0.2250 ;
      RECT 0.4000 0.1440 0.4140 0.2210 ;
      RECT 0.2320 0.2110 0.2460 0.2650 ;
      RECT 0.2740 0.1510 0.2880 0.2050 ;
      RECT 0.4840 0.2510 0.4980 0.3050 ;
      RECT 0.4420 0.1910 0.4560 0.2650 ;
      RECT 0.3580 0.1510 0.3720 0.2050 ;
    LAYER M0 ;
      RECT 0.1500 0.1130 0.1600 0.1230 ;
      RECT 0.1500 0.1330 0.1600 0.1430 ;
      RECT 0.1920 0.2130 0.2020 0.2230 ;
      RECT 0.2340 0.1330 0.2440 0.1430 ;
      RECT 0.2340 0.1130 0.2440 0.1230 ;
      RECT 0.2130 0.1530 0.2650 0.1630 ;
      RECT 0.1920 0.2330 0.2020 0.2430 ;
      RECT 0.1500 0.3130 0.3700 0.3230 ;
      RECT 0.4640 0.3530 0.4960 0.3630 ;
      RECT 0.1500 0.3330 0.1600 0.3430 ;
      RECT 0.1290 0.3530 0.4330 0.3630 ;
      RECT 0.4020 0.2930 0.4960 0.3030 ;
      RECT 0.3600 0.3130 0.4330 0.3230 ;
      RECT 0.1080 0.3530 0.1390 0.3630 ;
      RECT 0.4650 0.2530 0.4960 0.2630 ;
      RECT 0.3180 0.2930 0.3910 0.3030 ;
      RECT 0.3600 0.3330 0.3910 0.3430 ;
      RECT 0.2760 0.3330 0.3490 0.3430 ;
      RECT 0.4020 0.3330 0.4120 0.3430 ;
      RECT 0.1080 0.2130 0.1810 0.2230 ;
      RECT 0.3810 0.2130 0.4120 0.2230 ;
      RECT 0.1710 0.2530 0.2440 0.2630 ;
      RECT 0.4020 0.2530 0.4540 0.2630 ;
      RECT 0.1500 0.2930 0.2860 0.3030 ;
      RECT 0.1500 0.3130 0.1600 0.3230 ;
      RECT 0.4860 0.1330 0.4960 0.1430 ;
      RECT 0.4020 0.2330 0.4330 0.2430 ;
      RECT 0.2130 0.2330 0.3910 0.2430 ;
      RECT 0.4860 0.1130 0.4960 0.1230 ;
      RECT 0.4020 0.1130 0.4120 0.1230 ;
      RECT 0.4020 0.1130 0.4120 0.1230 ;
      RECT 0.4860 0.1130 0.4960 0.1230 ;
      RECT 0.4020 0.1330 0.4120 0.1430 ;
      RECT 0.4020 0.1330 0.4120 0.1430 ;
      RECT 0.3180 0.1130 0.3280 0.1230 ;
      RECT 0.3180 0.1330 0.3280 0.1430 ;
      RECT 0.3180 0.1330 0.3280 0.1430 ;
      RECT 0.2550 0.1930 0.2860 0.2030 ;
      RECT 0.4440 0.1330 0.4750 0.1430 ;
      RECT 0.3180 0.1930 0.3490 0.2030 ;
      RECT 0.1290 0.1930 0.1600 0.2030 ;
      RECT 0.1290 0.1530 0.1810 0.1630 ;
      RECT 0.1920 0.1930 0.2440 0.2030 ;
      RECT 0.4230 0.2130 0.4960 0.2230 ;
      RECT 0.4230 0.0930 0.4960 0.1030 ;
      RECT 0.2760 0.1530 0.3490 0.1630 ;
      RECT 0.2970 0.1530 0.3700 0.1630 ;
      RECT 0.3600 0.1930 0.4540 0.2030 ;
      RECT 0.2130 0.2130 0.3820 0.2230 ;
      RECT 0.1080 0.0930 0.4330 0.1030 ;
      RECT 0.1710 0.1330 0.2440 0.1430 ;
  END
END SDFF_X2

MACRO XNOR2_X1
  CLASS CORE ;
  FOREIGN XNOR2_X1 0 0 ;
  ORIGIN -0.0210 0.0000 ;
  SIZE 0.2520 BY 0.1000 ;
  SITE NSFET ;
  SYMMETRY X Y ;
  PIN ZN
    DIRECTION OUTPUT ;
    USE SIGNAL ;
    PORT
      LAYER M1 ;
        RECT 0.1610 0.0330 0.1750 0.0670 ;
        RECT 0.1610 0.0330 0.1750 0.0670 ;
    END
  END ZN
  PIN A
    DIRECTION INPUT ;
    USE SIGNAL ;
    PORT
      LAYER M1 ;
        RECT 0.0350 0.0130 0.0490 0.0470 ;
    END
  END A
  PIN B
    DIRECTION INPUT ;
    USE SIGNAL ;
    PORT
      LAYER M1 ;
        RECT 0.0770 0.0130 0.0910 0.0470 ;
    END
  END B
  PIN VSS
    DIRECTION INOUT ;
    USE GROUND ;
    PORT
      LAYER M0 ;
        RECT -0.0370 -0.0050 0.2470 0.0050 ;
    END
  END VSS
  PIN VDD
    DIRECTION INOUT ;
    USE POWER ;
    PORT
      LAYER M0 ;
        RECT -0.0370 0.0950 0.2470 0.1050 ;
    END
  END VDD
  OBS
    LAYER M1 ;
      RECT -0.0070 0.0330 0.0070 0.0670 ;
      RECT -0.0070 0.0330 0.0070 0.0670 ;
    LAYER M0 ;
      RECT -0.0050 0.0550 0.0260 0.0650 ;
      RECT 0.0160 0.0550 0.0470 0.0650 ;
      RECT 0.0370 0.0550 0.0680 0.0650 ;
      RECT 0.0580 0.0550 0.0890 0.0650 ;
      RECT 0.0790 0.0550 0.1100 0.0650 ;
      RECT 0.1210 0.0150 0.1520 0.0250 ;
      RECT 0.1420 0.0150 0.1730 0.0250 ;
      RECT 0.1630 0.0150 0.1940 0.0250 ;
      RECT 0.1840 0.0150 0.2150 0.0250 ;
      RECT 0.1210 0.0550 0.1520 0.0650 ;
      RECT 0.1420 0.0550 0.1730 0.0650 ;
      RECT 0.0580 0.0750 0.0890 0.0850 ;
      RECT 0.0790 0.0750 0.1100 0.0850 ;
      RECT 0.1000 0.0750 0.1310 0.0850 ;
      RECT 0.1210 0.0750 0.1520 0.0850 ;
      RECT 0.1420 0.0750 0.1730 0.0850 ;
      RECT 0.1630 0.0750 0.1940 0.0850 ;
      RECT 0.0160 0.0350 0.0470 0.0450 ;
      RECT 0.0370 0.0350 0.0680 0.0450 ;
      RECT 0.0580 0.0350 0.0890 0.0450 ;
      RECT 0.0790 0.0350 0.1100 0.0450 ;
      RECT 0.1000 0.0350 0.1310 0.0450 ;
      RECT 0.1210 0.0350 0.1520 0.0450 ;
      RECT -0.0050 0.0350 0.0050 0.0450 ;
      RECT 0.1630 0.0350 0.1730 0.0450 ;
      RECT -0.0050 0.0550 0.0260 0.0650 ;
      RECT 0.0160 0.0550 0.0470 0.0650 ;
      RECT 0.0370 0.0550 0.0680 0.0650 ;
      RECT 0.0580 0.0550 0.0890 0.0650 ;
      RECT 0.0790 0.0550 0.1100 0.0650 ;
      RECT 0.1210 0.0150 0.1520 0.0250 ;
      RECT 0.1420 0.0150 0.1730 0.0250 ;
      RECT 0.1630 0.0150 0.1940 0.0250 ;
      RECT 0.1840 0.0150 0.2150 0.0250 ;
      RECT 0.1210 0.0550 0.1520 0.0650 ;
      RECT 0.1420 0.0550 0.1730 0.0650 ;
      RECT 0.0580 0.0750 0.0890 0.0850 ;
      RECT 0.0790 0.0750 0.1100 0.0850 ;
      RECT 0.1000 0.0750 0.1310 0.0850 ;
      RECT 0.1210 0.0750 0.1520 0.0850 ;
      RECT 0.1420 0.0750 0.1730 0.0850 ;
      RECT 0.1630 0.0750 0.1940 0.0850 ;
      RECT 0.0160 0.0350 0.0470 0.0450 ;
      RECT 0.0370 0.0350 0.0680 0.0450 ;
      RECT 0.0580 0.0350 0.0890 0.0450 ;
      RECT 0.0790 0.0350 0.1100 0.0450 ;
      RECT 0.1000 0.0350 0.1310 0.0450 ;
      RECT 0.1210 0.0350 0.1520 0.0450 ;
      RECT -0.0050 0.0350 0.0050 0.0450 ;
      RECT 0.1630 0.0350 0.1730 0.0450 ;
      RECT 0.0160 0.0150 0.0480 0.0250 ;
      RECT 0.0580 0.0150 0.0900 0.0250 ;
  END
END XNOR2_X1

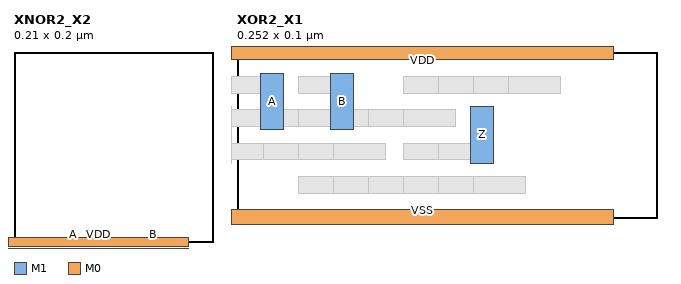
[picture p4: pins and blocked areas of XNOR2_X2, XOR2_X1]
MACRO XNOR2_X2
  CLASS CORE ;
  FOREIGN XNOR2_X2 0 0 ;
  ORIGIN -0.0210 -0.1000 ;
  SIZE 0.2100 BY 0.2000 ;
  SITE NSFET ;
  SYMMETRY X Y ;
  PIN A
    DIRECTION INPUT ;
    USE SIGNAL ;
    PORT
      LAYER M1 ;
        RECT 0.0770 -0.0070 0.0910 0.0270 ;
        RECT 0.0770 -0.0270 0.0910 0.0070 ;
    END
  END A
  PIN B
    DIRECTION INPUT ;
    USE SIGNAL ;
    PORT
      LAYER M1 ;
        RECT 0.1610 0.0330 0.1750 0.0670 ;
    END
  END B
  PIN ZN
    DIRECTION OUTPUT ;
    USE SIGNAL ;
    PORT
      LAYER M1 ;
        RECT 0.0770 -0.0670 0.0910 -0.0330 ;
    END
  END ZN
  PIN VDD
    DIRECTION INOUT ;
    USE POWER ;
    PORT
      LAYER M0 ;
        RECT -0.0370 -0.1050 0.2050 -0.0950 ;
    END
  END VDD
  PIN VSS
    DIRECTION INOUT ;
    USE GROUND ;
    PORT
      LAYER M0 ;
        RECT -0.0370 -0.0050 0.2050 0.0050 ;
    END
  END VSS
  PIN VDD
    DIRECTION INOUT ;
    USE POWER ;
    PORT
      LAYER M0 ;
        RECT -0.0370 0.0950 0.2050 0.1050 ;
    END
  END VDD
  OBS
    LAYER M1 ;
      RECT 0.0350 0.0330 0.0490 0.0670 ;
      RECT 0.0350 0.0130 0.0490 0.0470 ;
      RECT 0.0350 -0.0070 0.0490 0.0270 ;
      RECT 0.0350 -0.0270 0.0490 0.0070 ;
      RECT 0.1190 0.0330 0.1330 0.0670 ;
      RECT 0.0350 -0.0670 0.0490 -0.0330 ;
      RECT 0.0350 -0.0870 0.0490 -0.0530 ;
      RECT 0.1190 -0.0670 0.1330 -0.0330 ;
      RECT 0.1190 -0.0870 0.1330 -0.0530 ;
      RECT 0.1610 0.0530 0.1750 0.0870 ;
      RECT 0.1610 0.0130 0.1750 0.0470 ;
      RECT 0.1610 -0.0070 0.1750 0.0270 ;
      RECT 0.1610 -0.0270 0.1750 0.0070 ;
      RECT 0.0770 0.0130 0.0910 0.0470 ;
    LAYER M0 ;
      RECT 0.0370 0.0550 0.0680 0.0650 ;
      RECT 0.0580 0.0550 0.0890 0.0650 ;
      RECT 0.0790 0.0550 0.1100 0.0650 ;
      RECT 0.1000 0.0550 0.1310 0.0650 ;
      RECT 0.0160 -0.0250 0.0470 -0.0150 ;
      RECT -0.0050 0.0150 0.0260 0.0250 ;
      RECT 0.0160 0.0150 0.0470 0.0250 ;
      RECT 0.0370 0.0150 0.0680 0.0250 ;
      RECT 0.0580 0.0150 0.0890 0.0250 ;
      RECT 0.0790 0.0150 0.1100 0.0250 ;
      RECT 0.1000 0.0150 0.1310 0.0250 ;
      RECT 0.1210 0.0150 0.1520 0.0250 ;
      RECT 0.1420 0.0150 0.1730 0.0250 ;
      RECT 0.0370 -0.0650 0.0680 -0.0550 ;
      RECT 0.0580 -0.0650 0.0890 -0.0550 ;
      RECT 0.0370 -0.0850 0.0680 -0.0750 ;
      RECT 0.0580 -0.0850 0.0890 -0.0750 ;
      RECT 0.0790 -0.0850 0.1100 -0.0750 ;
      RECT 0.1000 -0.0850 0.1310 -0.0750 ;
      RECT 0.1000 0.0750 0.1310 0.0850 ;
      RECT 0.1210 0.0750 0.1520 0.0850 ;
      RECT 0.1420 0.0750 0.1730 0.0850 ;
      RECT 0.1000 -0.0250 0.1310 -0.0150 ;
      RECT 0.1210 -0.0250 0.1520 -0.0150 ;
      RECT 0.1420 -0.0250 0.1730 -0.0150 ;
      RECT 0.0160 0.0350 0.0470 0.0450 ;
      RECT 0.0370 0.0350 0.0680 0.0450 ;
      RECT 0.0580 0.0350 0.0890 0.0450 ;
      RECT 0.0580 -0.0250 0.0890 -0.0150 ;
      RECT 0.1210 0.0350 0.1310 0.0450 ;
      RECT 0.0790 -0.0450 0.0890 -0.0350 ;
      RECT 0.0370 -0.0450 0.0470 -0.0350 ;
      RECT 0.1210 -0.0450 0.1310 -0.0350 ;
  END
END XNOR2_X2

MACRO XOR2_X1
  CLASS CORE ;
  FOREIGN XOR2_X1 0 0 ;
  ORIGIN -0.0210 0.0000 ;
  SIZE 0.2520 BY 0.1000 ;
  SITE NSFET ;
  SYMMETRY X Y ;
  PIN A
    DIRECTION INPUT ;
    USE SIGNAL ;
    PORT
      LAYER M1 ;
        RECT 0.0350 0.0530 0.0490 0.0870 ;
    END
  END A
  PIN B
    DIRECTION INPUT ;
    USE SIGNAL ;
    PORT
      LAYER M1 ;
        RECT 0.0770 0.0530 0.0910 0.0870 ;
    END
  END B
  PIN Z
    DIRECTION OUTPUT ;
    USE SIGNAL ;
    PORT
      LAYER M1 ;
        RECT 0.1610 0.0330 0.1750 0.0670 ;
        RECT 0.1610 0.0330 0.1750 0.0670 ;
    END
  END Z
  PIN VSS
    DIRECTION INOUT ;
    USE GROUND ;
    PORT
      LAYER M0 ;
        RECT -0.0370 -0.0050 0.2470 0.0050 ;
    END
  END VSS
  PIN VDD
    DIRECTION INOUT ;
    USE POWER ;
    PORT
      LAYER M0 ;
        RECT -0.0370 0.0950 0.2470 0.1050 ;
    END
  END VDD
  OBS
    LAYER M1 ;
      RECT -0.0070 0.0330 0.0070 0.0670 ;
      RECT -0.0070 0.0330 0.0070 0.0670 ;
    LAYER M0 ;
      RECT -0.0050 0.0350 0.0260 0.0450 ;
      RECT 0.0160 0.0350 0.0470 0.0450 ;
      RECT 0.0370 0.0350 0.0680 0.0450 ;
      RECT 0.0580 0.0350 0.0890 0.0450 ;
      RECT 0.0790 0.0350 0.1100 0.0450 ;
      RECT 0.1210 0.0750 0.1520 0.0850 ;
      RECT 0.1420 0.0750 0.1730 0.0850 ;
      RECT 0.1630 0.0750 0.1940 0.0850 ;
      RECT 0.1840 0.0750 0.2150 0.0850 ;
      RECT 0.1210 0.0350 0.1520 0.0450 ;
      RECT 0.1420 0.0350 0.1730 0.0450 ;
      RECT 0.0580 0.0150 0.0890 0.0250 ;
      RECT 0.0790 0.0150 0.1100 0.0250 ;
      RECT 0.1000 0.0150 0.1310 0.0250 ;
      RECT 0.1210 0.0150 0.1520 0.0250 ;
      RECT 0.1420 0.0150 0.1730 0.0250 ;
      RECT 0.1630 0.0150 0.1940 0.0250 ;
      RECT 0.0160 0.0550 0.0470 0.0650 ;
      RECT 0.0370 0.0550 0.0680 0.0650 ;
      RECT 0.0580 0.0550 0.0890 0.0650 ;
      RECT 0.0790 0.0550 0.1100 0.0650 ;
      RECT 0.1000 0.0550 0.1310 0.0650 ;
      RECT 0.1210 0.0550 0.1520 0.0650 ;
      RECT -0.0050 0.0550 0.0050 0.0650 ;
      RECT 0.1630 0.0550 0.1730 0.0650 ;
      RECT -0.0050 0.0350 0.0260 0.0450 ;
      RECT 0.0160 0.0350 0.0470 0.0450 ;
      RECT 0.0370 0.0350 0.0680 0.0450 ;
      RECT 0.0580 0.0350 0.0890 0.0450 ;
      RECT 0.0790 0.0350 0.1100 0.0450 ;
      RECT 0.1210 0.0750 0.1520 0.0850 ;
      RECT 0.1420 0.0750 0.1730 0.0850 ;
      RECT 0.1630 0.0750 0.1940 0.0850 ;
      RECT 0.1840 0.0750 0.2150 0.0850 ;
      RECT 0.1210 0.0350 0.1520 0.0450 ;
      RECT 0.1420 0.0350 0.1730 0.0450 ;
      RECT 0.0580 0.0150 0.0890 0.0250 ;
      RECT 0.0790 0.0150 0.1100 0.0250 ;
      RECT 0.1000 0.0150 0.1310 0.0250 ;
      RECT 0.1210 0.0150 0.1520 0.0250 ;
      RECT 0.1420 0.0150 0.1730 0.0250 ;
      RECT 0.1630 0.0150 0.1940 0.0250 ;
      RECT 0.0160 0.0550 0.0470 0.0650 ;
      RECT 0.0370 0.0550 0.0680 0.0650 ;
      RECT 0.0580 0.0550 0.0890 0.0650 ;
      RECT 0.0790 0.0550 0.1100 0.0650 ;
      RECT 0.1000 0.0550 0.1310 0.0650 ;
      RECT 0.1210 0.0550 0.1520 0.0650 ;
      RECT -0.0050 0.0550 0.0050 0.0650 ;
      RECT 0.1630 0.0550 0.1730 0.0650 ;
      RECT 0.0160 0.0750 0.0470 0.0850 ;
      RECT 0.0580 0.0750 0.0890 0.0850 ;
  END
END XOR2_X1

END LIBRARY
